VERSION 5.8 ;
BUSBITCHARS "[]" ;
DIVIDERCHAR "/" ;
UNITS
    DATABASE MICRONS 1000 ;
END UNITS

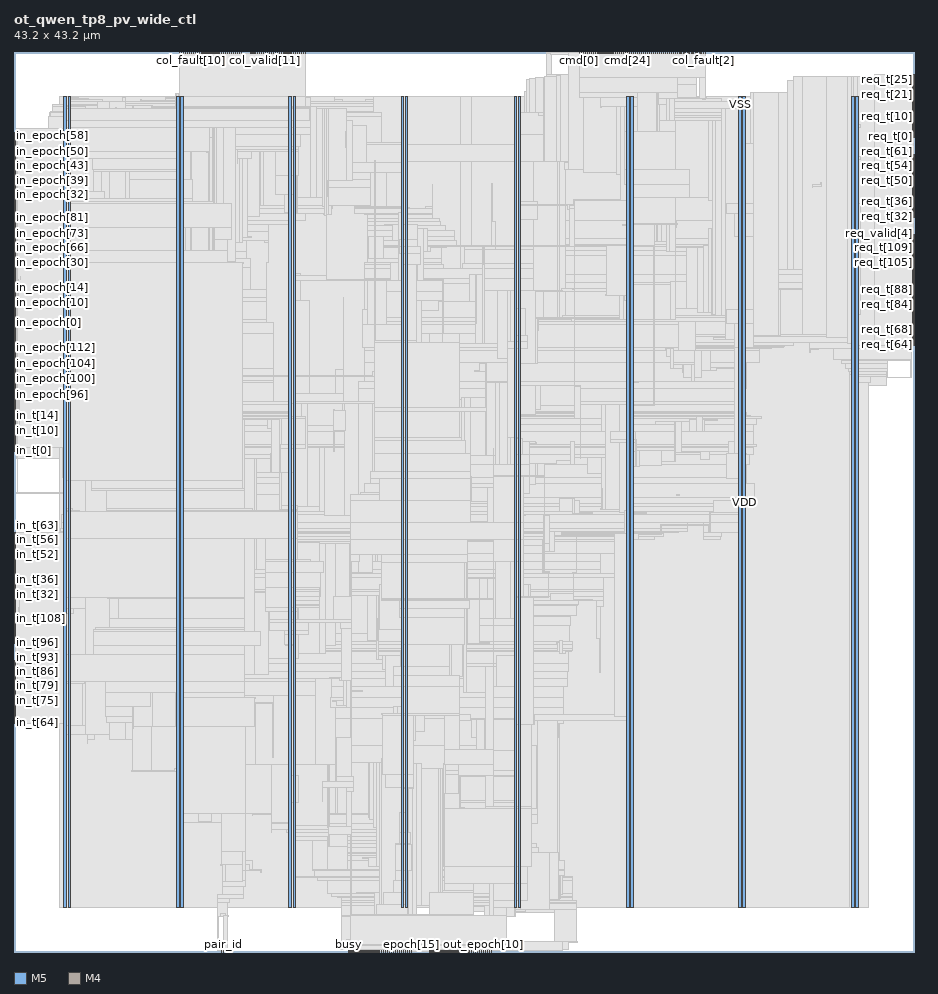
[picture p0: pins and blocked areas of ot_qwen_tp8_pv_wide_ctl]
MACRO ot_qwen_tp8_pv_wide_ctl
  FOREIGN ot_qwen_tp8_pv_wide_ctl 0 0 ;
  CLASS BLOCK ;
  SIZE 43.2 BY 43.2 ;
  PIN busy
    DIRECTION OUTPUT ;
    USE SIGNAL ;
    PORT
      LAYER M5 ;
        RECT  16.08 0 16.104 0.084 ;
    END
  END busy
  PIN clk
    DIRECTION INPUT ;
    USE SIGNAL ;
    PORT
      LAYER M5 ;
        RECT  16.176 0 16.2 0.084 ;
    END
  END clk
  PIN cmd[0]
    DIRECTION OUTPUT ;
    USE SIGNAL ;
    PORT
      LAYER M5 ;
        RECT  27.12 43.116 27.144 43.2 ;
    END
  END cmd[0]
  PIN cmd[10]
    DIRECTION OUTPUT ;
    USE SIGNAL ;
    PORT
      LAYER M5 ;
        RECT  28.08 43.116 28.104 43.2 ;
    END
  END cmd[10]
  PIN cmd[11]
    DIRECTION OUTPUT ;
    USE SIGNAL ;
    PORT
      LAYER M5 ;
        RECT  28.176 43.116 28.2 43.2 ;
    END
  END cmd[11]
  PIN cmd[12]
    DIRECTION OUTPUT ;
    USE SIGNAL ;
    PORT
      LAYER M5 ;
        RECT  28.272 43.116 28.296 43.2 ;
    END
  END cmd[12]
  PIN cmd[13]
    DIRECTION OUTPUT ;
    USE SIGNAL ;
    PORT
      LAYER M5 ;
        RECT  28.368 43.116 28.392 43.2 ;
    END
  END cmd[13]
  PIN cmd[14]
    DIRECTION OUTPUT ;
    USE SIGNAL ;
    PORT
      LAYER M5 ;
        RECT  28.464 43.116 28.488 43.2 ;
    END
  END cmd[14]
  PIN cmd[15]
    DIRECTION OUTPUT ;
    USE SIGNAL ;
    PORT
      LAYER M5 ;
        RECT  28.56 43.116 28.584 43.2 ;
    END
  END cmd[15]
  PIN cmd[16]
    DIRECTION OUTPUT ;
    USE SIGNAL ;
    PORT
      LAYER M5 ;
        RECT  28.656 43.116 28.68 43.2 ;
    END
  END cmd[16]
  PIN cmd[17]
    DIRECTION OUTPUT ;
    USE SIGNAL ;
    PORT
      LAYER M5 ;
        RECT  28.752 43.116 28.776 43.2 ;
    END
  END cmd[17]
  PIN cmd[18]
    DIRECTION OUTPUT ;
    USE SIGNAL ;
    PORT
      LAYER M5 ;
        RECT  28.848 43.116 28.872 43.2 ;
    END
  END cmd[18]
  PIN cmd[19]
    DIRECTION OUTPUT ;
    USE SIGNAL ;
    PORT
      LAYER M5 ;
        RECT  28.944 43.116 28.968 43.2 ;
    END
  END cmd[19]
  PIN cmd[1]
    DIRECTION OUTPUT ;
    USE SIGNAL ;
    PORT
      LAYER M5 ;
        RECT  27.216 43.116 27.24 43.2 ;
    END
  END cmd[1]
  PIN cmd[20]
    DIRECTION OUTPUT ;
    USE SIGNAL ;
    PORT
      LAYER M5 ;
        RECT  29.04 43.116 29.064 43.2 ;
    END
  END cmd[20]
  PIN cmd[21]
    DIRECTION OUTPUT ;
    USE SIGNAL ;
    PORT
      LAYER M5 ;
        RECT  29.136 43.116 29.16 43.2 ;
    END
  END cmd[21]
  PIN cmd[22]
    DIRECTION OUTPUT ;
    USE SIGNAL ;
    PORT
      LAYER M5 ;
        RECT  29.232 43.116 29.256 43.2 ;
    END
  END cmd[22]
  PIN cmd[23]
    DIRECTION OUTPUT ;
    USE SIGNAL ;
    PORT
      LAYER M5 ;
        RECT  29.328 43.116 29.352 43.2 ;
    END
  END cmd[23]
  PIN cmd[24]
    DIRECTION OUTPUT ;
    USE SIGNAL ;
    PORT
      LAYER M5 ;
        RECT  29.424 43.116 29.448 43.2 ;
    END
  END cmd[24]
  PIN cmd[25]
    DIRECTION OUTPUT ;
    USE SIGNAL ;
    PORT
      LAYER M5 ;
        RECT  29.52 43.116 29.544 43.2 ;
    END
  END cmd[25]
  PIN cmd[26]
    DIRECTION OUTPUT ;
    USE SIGNAL ;
    PORT
      LAYER M5 ;
        RECT  29.616 43.116 29.64 43.2 ;
    END
  END cmd[26]
  PIN cmd[27]
    DIRECTION OUTPUT ;
    USE SIGNAL ;
    PORT
      LAYER M5 ;
        RECT  29.712 43.116 29.736 43.2 ;
    END
  END cmd[27]
  PIN cmd[28]
    DIRECTION OUTPUT ;
    USE SIGNAL ;
    PORT
      LAYER M5 ;
        RECT  29.808 43.116 29.832 43.2 ;
    END
  END cmd[28]
  PIN cmd[29]
    DIRECTION OUTPUT ;
    USE SIGNAL ;
    PORT
      LAYER M5 ;
        RECT  29.904 43.116 29.928 43.2 ;
    END
  END cmd[29]
  PIN cmd[2]
    DIRECTION OUTPUT ;
    USE SIGNAL ;
    PORT
      LAYER M5 ;
        RECT  27.312 43.116 27.336 43.2 ;
    END
  END cmd[2]
  PIN cmd[30]
    DIRECTION OUTPUT ;
    USE SIGNAL ;
    PORT
      LAYER M5 ;
        RECT  30 43.116 30.024 43.2 ;
    END
  END cmd[30]
  PIN cmd[31]
    DIRECTION OUTPUT ;
    USE SIGNAL ;
    PORT
      LAYER M5 ;
        RECT  30.096 43.116 30.12 43.2 ;
    END
  END cmd[31]
  PIN cmd[32]
    DIRECTION OUTPUT ;
    USE SIGNAL ;
    PORT
      LAYER M5 ;
        RECT  30.192 43.116 30.216 43.2 ;
    END
  END cmd[32]
  PIN cmd[33]
    DIRECTION OUTPUT ;
    USE SIGNAL ;
    PORT
      LAYER M5 ;
        RECT  30.288 43.116 30.312 43.2 ;
    END
  END cmd[33]
  PIN cmd[34]
    DIRECTION OUTPUT ;
    USE SIGNAL ;
    PORT
      LAYER M5 ;
        RECT  30.384 43.116 30.408 43.2 ;
    END
  END cmd[34]
  PIN cmd[35]
    DIRECTION OUTPUT ;
    USE SIGNAL ;
    PORT
      LAYER M5 ;
        RECT  30.48 43.116 30.504 43.2 ;
    END
  END cmd[35]
  PIN cmd[36]
    DIRECTION OUTPUT ;
    USE SIGNAL ;
    PORT
      LAYER M5 ;
        RECT  30.576 43.116 30.6 43.2 ;
    END
  END cmd[36]
  PIN cmd[37]
    DIRECTION OUTPUT ;
    USE SIGNAL ;
    PORT
      LAYER M5 ;
        RECT  30.672 43.116 30.696 43.2 ;
    END
  END cmd[37]
  PIN cmd[38]
    DIRECTION OUTPUT ;
    USE SIGNAL ;
    PORT
      LAYER M5 ;
        RECT  30.768 43.116 30.792 43.2 ;
    END
  END cmd[38]
  PIN cmd[39]
    DIRECTION OUTPUT ;
    USE SIGNAL ;
    PORT
      LAYER M5 ;
        RECT  30.864 43.116 30.888 43.2 ;
    END
  END cmd[39]
  PIN cmd[3]
    DIRECTION OUTPUT ;
    USE SIGNAL ;
    PORT
      LAYER M5 ;
        RECT  27.408 43.116 27.432 43.2 ;
    END
  END cmd[3]
  PIN cmd[40]
    DIRECTION OUTPUT ;
    USE SIGNAL ;
    PORT
      LAYER M5 ;
        RECT  30.96 43.116 30.984 43.2 ;
    END
  END cmd[40]
  PIN cmd[41]
    DIRECTION OUTPUT ;
    USE SIGNAL ;
    PORT
      LAYER M5 ;
        RECT  31.056 43.116 31.08 43.2 ;
    END
  END cmd[41]
  PIN cmd[42]
    DIRECTION OUTPUT ;
    USE SIGNAL ;
    PORT
      LAYER M5 ;
        RECT  31.152 43.116 31.176 43.2 ;
    END
  END cmd[42]
  PIN cmd[43]
    DIRECTION OUTPUT ;
    USE SIGNAL ;
    PORT
      LAYER M5 ;
        RECT  31.248 43.116 31.272 43.2 ;
    END
  END cmd[43]
  PIN cmd[44]
    DIRECTION OUTPUT ;
    USE SIGNAL ;
    PORT
      LAYER M5 ;
        RECT  31.344 43.116 31.368 43.2 ;
    END
  END cmd[44]
  PIN cmd[45]
    DIRECTION OUTPUT ;
    USE SIGNAL ;
    PORT
      LAYER M5 ;
        RECT  31.44 43.116 31.464 43.2 ;
    END
  END cmd[45]
  PIN cmd[46]
    DIRECTION OUTPUT ;
    USE SIGNAL ;
    PORT
      LAYER M5 ;
        RECT  31.536 43.116 31.56 43.2 ;
    END
  END cmd[46]
  PIN cmd[47]
    DIRECTION OUTPUT ;
    USE SIGNAL ;
    PORT
      LAYER M5 ;
        RECT  31.632 43.116 31.656 43.2 ;
    END
  END cmd[47]
  PIN cmd[48]
    DIRECTION OUTPUT ;
    USE SIGNAL ;
    PORT
      LAYER M5 ;
        RECT  31.728 43.116 31.752 43.2 ;
    END
  END cmd[48]
  PIN cmd[49]
    DIRECTION OUTPUT ;
    USE SIGNAL ;
    PORT
      LAYER M5 ;
        RECT  31.824 43.116 31.848 43.2 ;
    END
  END cmd[49]
  PIN cmd[4]
    DIRECTION OUTPUT ;
    USE SIGNAL ;
    PORT
      LAYER M5 ;
        RECT  27.504 43.116 27.528 43.2 ;
    END
  END cmd[4]
  PIN cmd[50]
    DIRECTION OUTPUT ;
    USE SIGNAL ;
    PORT
      LAYER M5 ;
        RECT  31.92 43.116 31.944 43.2 ;
    END
  END cmd[50]
  PIN cmd[51]
    DIRECTION OUTPUT ;
    USE SIGNAL ;
    PORT
      LAYER M5 ;
        RECT  32.016 43.116 32.04 43.2 ;
    END
  END cmd[51]
  PIN cmd[52]
    DIRECTION OUTPUT ;
    USE SIGNAL ;
    PORT
      LAYER M5 ;
        RECT  32.112 43.116 32.136 43.2 ;
    END
  END cmd[52]
  PIN cmd[53]
    DIRECTION OUTPUT ;
    USE SIGNAL ;
    PORT
      LAYER M5 ;
        RECT  32.208 43.116 32.232 43.2 ;
    END
  END cmd[53]
  PIN cmd[54]
    DIRECTION OUTPUT ;
    USE SIGNAL ;
    PORT
      LAYER M5 ;
        RECT  32.304 43.116 32.328 43.2 ;
    END
  END cmd[54]
  PIN cmd[55]
    DIRECTION OUTPUT ;
    USE SIGNAL ;
    PORT
      LAYER M5 ;
        RECT  32.4 43.116 32.424 43.2 ;
    END
  END cmd[55]
  PIN cmd[56]
    DIRECTION OUTPUT ;
    USE SIGNAL ;
    PORT
      LAYER M5 ;
        RECT  32.496 43.116 32.52 43.2 ;
    END
  END cmd[56]
  PIN cmd[57]
    DIRECTION OUTPUT ;
    USE SIGNAL ;
    PORT
      LAYER M5 ;
        RECT  32.592 43.116 32.616 43.2 ;
    END
  END cmd[57]
  PIN cmd[58]
    DIRECTION OUTPUT ;
    USE SIGNAL ;
    PORT
      LAYER M5 ;
        RECT  32.688 43.116 32.712 43.2 ;
    END
  END cmd[58]
  PIN cmd[59]
    DIRECTION OUTPUT ;
    USE SIGNAL ;
    PORT
      LAYER M5 ;
        RECT  32.784 43.116 32.808 43.2 ;
    END
  END cmd[59]
  PIN cmd[5]
    DIRECTION OUTPUT ;
    USE SIGNAL ;
    PORT
      LAYER M5 ;
        RECT  27.6 43.116 27.624 43.2 ;
    END
  END cmd[5]
  PIN cmd[6]
    DIRECTION OUTPUT ;
    USE SIGNAL ;
    PORT
      LAYER M5 ;
        RECT  27.696 43.116 27.72 43.2 ;
    END
  END cmd[6]
  PIN cmd[7]
    DIRECTION OUTPUT ;
    USE SIGNAL ;
    PORT
      LAYER M5 ;
        RECT  27.792 43.116 27.816 43.2 ;
    END
  END cmd[7]
  PIN cmd[8]
    DIRECTION OUTPUT ;
    USE SIGNAL ;
    PORT
      LAYER M5 ;
        RECT  27.888 43.116 27.912 43.2 ;
    END
  END cmd[8]
  PIN cmd[9]
    DIRECTION OUTPUT ;
    USE SIGNAL ;
    PORT
      LAYER M5 ;
        RECT  27.984 43.116 28.008 43.2 ;
    END
  END cmd[9]
  PIN col_fault[0]
    DIRECTION INPUT ;
    USE SIGNAL ;
    PORT
      LAYER M5 ;
        RECT  32.88 43.116 32.904 43.2 ;
    END
  END col_fault[0]
  PIN col_fault[10]
    DIRECTION INPUT ;
    USE SIGNAL ;
    PORT
      LAYER M5 ;
        RECT  8.496 43.116 8.52 43.2 ;
    END
  END col_fault[10]
  PIN col_fault[11]
    DIRECTION INPUT ;
    USE SIGNAL ;
    PORT
      LAYER M5 ;
        RECT  8.592 43.116 8.616 43.2 ;
    END
  END col_fault[11]
  PIN col_fault[12]
    DIRECTION INPUT ;
    USE SIGNAL ;
    PORT
      LAYER M5 ;
        RECT  8.688 43.116 8.712 43.2 ;
    END
  END col_fault[12]
  PIN col_fault[13]
    DIRECTION INPUT ;
    USE SIGNAL ;
    PORT
      LAYER M5 ;
        RECT  8.784 43.116 8.808 43.2 ;
    END
  END col_fault[13]
  PIN col_fault[14]
    DIRECTION INPUT ;
    USE SIGNAL ;
    PORT
      LAYER M5 ;
        RECT  8.88 43.116 8.904 43.2 ;
    END
  END col_fault[14]
  PIN col_fault[15]
    DIRECTION INPUT ;
    USE SIGNAL ;
    PORT
      LAYER M5 ;
        RECT  8.976 43.116 9 43.2 ;
    END
  END col_fault[15]
  PIN col_fault[16]
    DIRECTION INPUT ;
    USE SIGNAL ;
    PORT
      LAYER M5 ;
        RECT  9.072 43.116 9.096 43.2 ;
    END
  END col_fault[16]
  PIN col_fault[17]
    DIRECTION INPUT ;
    USE SIGNAL ;
    PORT
      LAYER M5 ;
        RECT  9.168 43.116 9.192 43.2 ;
    END
  END col_fault[17]
  PIN col_fault[18]
    DIRECTION INPUT ;
    USE SIGNAL ;
    PORT
      LAYER M5 ;
        RECT  9.264 43.116 9.288 43.2 ;
    END
  END col_fault[18]
  PIN col_fault[19]
    DIRECTION INPUT ;
    USE SIGNAL ;
    PORT
      LAYER M5 ;
        RECT  9.36 43.116 9.384 43.2 ;
    END
  END col_fault[19]
  PIN col_fault[1]
    DIRECTION INPUT ;
    USE SIGNAL ;
    PORT
      LAYER M5 ;
        RECT  32.976 43.116 33 43.2 ;
    END
  END col_fault[1]
  PIN col_fault[20]
    DIRECTION INPUT ;
    USE SIGNAL ;
    PORT
      LAYER M5 ;
        RECT  9.456 43.116 9.48 43.2 ;
    END
  END col_fault[20]
  PIN col_fault[21]
    DIRECTION INPUT ;
    USE SIGNAL ;
    PORT
      LAYER M5 ;
        RECT  9.552 43.116 9.576 43.2 ;
    END
  END col_fault[21]
  PIN col_fault[22]
    DIRECTION INPUT ;
    USE SIGNAL ;
    PORT
      LAYER M5 ;
        RECT  9.648 43.116 9.672 43.2 ;
    END
  END col_fault[22]
  PIN col_fault[23]
    DIRECTION INPUT ;
    USE SIGNAL ;
    PORT
      LAYER M5 ;
        RECT  9.744 43.116 9.768 43.2 ;
    END
  END col_fault[23]
  PIN col_fault[24]
    DIRECTION INPUT ;
    USE SIGNAL ;
    PORT
      LAYER M5 ;
        RECT  9.84 43.116 9.864 43.2 ;
    END
  END col_fault[24]
  PIN col_fault[25]
    DIRECTION INPUT ;
    USE SIGNAL ;
    PORT
      LAYER M5 ;
        RECT  9.936 43.116 9.96 43.2 ;
    END
  END col_fault[25]
  PIN col_fault[26]
    DIRECTION INPUT ;
    USE SIGNAL ;
    PORT
      LAYER M5 ;
        RECT  10.032 43.116 10.056 43.2 ;
    END
  END col_fault[26]
  PIN col_fault[27]
    DIRECTION INPUT ;
    USE SIGNAL ;
    PORT
      LAYER M5 ;
        RECT  10.128 43.116 10.152 43.2 ;
    END
  END col_fault[27]
  PIN col_fault[28]
    DIRECTION INPUT ;
    USE SIGNAL ;
    PORT
      LAYER M5 ;
        RECT  10.224 43.116 10.248 43.2 ;
    END
  END col_fault[28]
  PIN col_fault[29]
    DIRECTION INPUT ;
    USE SIGNAL ;
    PORT
      LAYER M5 ;
        RECT  10.32 43.116 10.344 43.2 ;
    END
  END col_fault[29]
  PIN col_fault[2]
    DIRECTION INPUT ;
    USE SIGNAL ;
    PORT
      LAYER M5 ;
        RECT  33.072 43.116 33.096 43.2 ;
    END
  END col_fault[2]
  PIN col_fault[30]
    DIRECTION INPUT ;
    USE SIGNAL ;
    PORT
      LAYER M5 ;
        RECT  10.416 43.116 10.44 43.2 ;
    END
  END col_fault[30]
  PIN col_fault[31]
    DIRECTION INPUT ;
    USE SIGNAL ;
    PORT
      LAYER M5 ;
        RECT  10.512 43.116 10.536 43.2 ;
    END
  END col_fault[31]
  PIN col_fault[3]
    DIRECTION INPUT ;
    USE SIGNAL ;
    PORT
      LAYER M5 ;
        RECT  33.168 43.116 33.192 43.2 ;
    END
  END col_fault[3]
  PIN col_fault[4]
    DIRECTION INPUT ;
    USE SIGNAL ;
    PORT
      LAYER M5 ;
        RECT  7.92 43.116 7.944 43.2 ;
    END
  END col_fault[4]
  PIN col_fault[5]
    DIRECTION INPUT ;
    USE SIGNAL ;
    PORT
      LAYER M5 ;
        RECT  8.016 43.116 8.04 43.2 ;
    END
  END col_fault[5]
  PIN col_fault[6]
    DIRECTION INPUT ;
    USE SIGNAL ;
    PORT
      LAYER M5 ;
        RECT  8.112 43.116 8.136 43.2 ;
    END
  END col_fault[6]
  PIN col_fault[7]
    DIRECTION INPUT ;
    USE SIGNAL ;
    PORT
      LAYER M5 ;
        RECT  8.208 43.116 8.232 43.2 ;
    END
  END col_fault[7]
  PIN col_fault[8]
    DIRECTION INPUT ;
    USE SIGNAL ;
    PORT
      LAYER M5 ;
        RECT  8.304 43.116 8.328 43.2 ;
    END
  END col_fault[8]
  PIN col_fault[9]
    DIRECTION INPUT ;
    USE SIGNAL ;
    PORT
      LAYER M5 ;
        RECT  8.4 43.116 8.424 43.2 ;
    END
  END col_fault[9]
  PIN col_valid[0]
    DIRECTION INPUT ;
    USE SIGNAL ;
    PORT
      LAYER M5 ;
        RECT  10.608 43.116 10.632 43.2 ;
    END
  END col_valid[0]
  PIN col_valid[10]
    DIRECTION INPUT ;
    USE SIGNAL ;
    PORT
      LAYER M5 ;
        RECT  11.952 43.116 11.976 43.2 ;
    END
  END col_valid[10]
  PIN col_valid[11]
    DIRECTION INPUT ;
    USE SIGNAL ;
    PORT
      LAYER M5 ;
        RECT  12.048 43.116 12.072 43.2 ;
    END
  END col_valid[11]
  PIN col_valid[12]
    DIRECTION INPUT ;
    USE SIGNAL ;
    PORT
      LAYER M5 ;
        RECT  12.144 43.116 12.168 43.2 ;
    END
  END col_valid[12]
  PIN col_valid[13]
    DIRECTION INPUT ;
    USE SIGNAL ;
    PORT
      LAYER M5 ;
        RECT  12.24 43.116 12.264 43.2 ;
    END
  END col_valid[13]
  PIN col_valid[14]
    DIRECTION INPUT ;
    USE SIGNAL ;
    PORT
      LAYER M5 ;
        RECT  12.336 43.116 12.36 43.2 ;
    END
  END col_valid[14]
  PIN col_valid[15]
    DIRECTION INPUT ;
    USE SIGNAL ;
    PORT
      LAYER M5 ;
        RECT  12.432 43.116 12.456 43.2 ;
    END
  END col_valid[15]
  PIN col_valid[16]
    DIRECTION INPUT ;
    USE SIGNAL ;
    PORT
      LAYER M5 ;
        RECT  12.528 43.116 12.552 43.2 ;
    END
  END col_valid[16]
  PIN col_valid[17]
    DIRECTION INPUT ;
    USE SIGNAL ;
    PORT
      LAYER M5 ;
        RECT  12.624 43.116 12.648 43.2 ;
    END
  END col_valid[17]
  PIN col_valid[18]
    DIRECTION INPUT ;
    USE SIGNAL ;
    PORT
      LAYER M5 ;
        RECT  12.72 43.116 12.744 43.2 ;
    END
  END col_valid[18]
  PIN col_valid[19]
    DIRECTION INPUT ;
    USE SIGNAL ;
    PORT
      LAYER M5 ;
        RECT  12.816 43.116 12.84 43.2 ;
    END
  END col_valid[19]
  PIN col_valid[1]
    DIRECTION INPUT ;
    USE SIGNAL ;
    PORT
      LAYER M5 ;
        RECT  10.704 43.116 10.728 43.2 ;
    END
  END col_valid[1]
  PIN col_valid[20]
    DIRECTION INPUT ;
    USE SIGNAL ;
    PORT
      LAYER M5 ;
        RECT  12.912 43.116 12.936 43.2 ;
    END
  END col_valid[20]
  PIN col_valid[21]
    DIRECTION INPUT ;
    USE SIGNAL ;
    PORT
      LAYER M5 ;
        RECT  13.008 43.116 13.032 43.2 ;
    END
  END col_valid[21]
  PIN col_valid[22]
    DIRECTION INPUT ;
    USE SIGNAL ;
    PORT
      LAYER M5 ;
        RECT  13.104 43.116 13.128 43.2 ;
    END
  END col_valid[22]
  PIN col_valid[23]
    DIRECTION INPUT ;
    USE SIGNAL ;
    PORT
      LAYER M5 ;
        RECT  13.2 43.116 13.224 43.2 ;
    END
  END col_valid[23]
  PIN col_valid[24]
    DIRECTION INPUT ;
    USE SIGNAL ;
    PORT
      LAYER M5 ;
        RECT  13.296 43.116 13.32 43.2 ;
    END
  END col_valid[24]
  PIN col_valid[25]
    DIRECTION INPUT ;
    USE SIGNAL ;
    PORT
      LAYER M5 ;
        RECT  13.392 43.116 13.416 43.2 ;
    END
  END col_valid[25]
  PIN col_valid[26]
    DIRECTION INPUT ;
    USE SIGNAL ;
    PORT
      LAYER M5 ;
        RECT  13.488 43.116 13.512 43.2 ;
    END
  END col_valid[26]
  PIN col_valid[27]
    DIRECTION INPUT ;
    USE SIGNAL ;
    PORT
      LAYER M5 ;
        RECT  13.584 43.116 13.608 43.2 ;
    END
  END col_valid[27]
  PIN col_valid[28]
    DIRECTION INPUT ;
    USE SIGNAL ;
    PORT
      LAYER M5 ;
        RECT  13.68 43.116 13.704 43.2 ;
    END
  END col_valid[28]
  PIN col_valid[29]
    DIRECTION INPUT ;
    USE SIGNAL ;
    PORT
      LAYER M5 ;
        RECT  13.776 43.116 13.8 43.2 ;
    END
  END col_valid[29]
  PIN col_valid[2]
    DIRECTION INPUT ;
    USE SIGNAL ;
    PORT
      LAYER M5 ;
        RECT  10.8 43.116 10.824 43.2 ;
    END
  END col_valid[2]
  PIN col_valid[30]
    DIRECTION INPUT ;
    USE SIGNAL ;
    PORT
      LAYER M5 ;
        RECT  13.872 43.116 13.896 43.2 ;
    END
  END col_valid[30]
  PIN col_valid[31]
    DIRECTION INPUT ;
    USE SIGNAL ;
    PORT
      LAYER M5 ;
        RECT  13.968 43.116 13.992 43.2 ;
    END
  END col_valid[31]
  PIN col_valid[3]
    DIRECTION INPUT ;
    USE SIGNAL ;
    PORT
      LAYER M5 ;
        RECT  10.896 43.116 10.92 43.2 ;
    END
  END col_valid[3]
  PIN col_valid[4]
    DIRECTION INPUT ;
    USE SIGNAL ;
    PORT
      LAYER M5 ;
        RECT  11.376 43.116 11.4 43.2 ;
    END
  END col_valid[4]
  PIN col_valid[5]
    DIRECTION INPUT ;
    USE SIGNAL ;
    PORT
      LAYER M5 ;
        RECT  11.472 43.116 11.496 43.2 ;
    END
  END col_valid[5]
  PIN col_valid[6]
    DIRECTION INPUT ;
    USE SIGNAL ;
    PORT
      LAYER M5 ;
        RECT  11.568 43.116 11.592 43.2 ;
    END
  END col_valid[6]
  PIN col_valid[7]
    DIRECTION INPUT ;
    USE SIGNAL ;
    PORT
      LAYER M5 ;
        RECT  11.664 43.116 11.688 43.2 ;
    END
  END col_valid[7]
  PIN col_valid[8]
    DIRECTION INPUT ;
    USE SIGNAL ;
    PORT
      LAYER M5 ;
        RECT  11.76 43.116 11.784 43.2 ;
    END
  END col_valid[8]
  PIN col_valid[9]
    DIRECTION INPUT ;
    USE SIGNAL ;
    PORT
      LAYER M5 ;
        RECT  11.856 43.116 11.88 43.2 ;
    END
  END col_valid[9]
  PIN context_len[0]
    DIRECTION INPUT ;
    USE SIGNAL ;
    PORT
      LAYER M5 ;
        RECT  16.272 0 16.296 0.084 ;
    END
  END context_len[0]
  PIN context_len[10]
    DIRECTION INPUT ;
    USE SIGNAL ;
    PORT
      LAYER M5 ;
        RECT  17.232 0 17.256 0.084 ;
    END
  END context_len[10]
  PIN context_len[11]
    DIRECTION INPUT ;
    USE SIGNAL ;
    PORT
      LAYER M5 ;
        RECT  17.328 0 17.352 0.084 ;
    END
  END context_len[11]
  PIN context_len[12]
    DIRECTION INPUT ;
    USE SIGNAL ;
    PORT
      LAYER M5 ;
        RECT  17.424 0 17.448 0.084 ;
    END
  END context_len[12]
  PIN context_len[13]
    DIRECTION INPUT ;
    USE SIGNAL ;
    PORT
      LAYER M5 ;
        RECT  17.52 0 17.544 0.084 ;
    END
  END context_len[13]
  PIN context_len[1]
    DIRECTION INPUT ;
    USE SIGNAL ;
    PORT
      LAYER M5 ;
        RECT  16.368 0 16.392 0.084 ;
    END
  END context_len[1]
  PIN context_len[2]
    DIRECTION INPUT ;
    USE SIGNAL ;
    PORT
      LAYER M5 ;
        RECT  16.464 0 16.488 0.084 ;
    END
  END context_len[2]
  PIN context_len[3]
    DIRECTION INPUT ;
    USE SIGNAL ;
    PORT
      LAYER M5 ;
        RECT  16.56 0 16.584 0.084 ;
    END
  END context_len[3]
  PIN context_len[4]
    DIRECTION INPUT ;
    USE SIGNAL ;
    PORT
      LAYER M5 ;
        RECT  16.656 0 16.68 0.084 ;
    END
  END context_len[4]
  PIN context_len[5]
    DIRECTION INPUT ;
    USE SIGNAL ;
    PORT
      LAYER M5 ;
        RECT  16.752 0 16.776 0.084 ;
    END
  END context_len[5]
  PIN context_len[6]
    DIRECTION INPUT ;
    USE SIGNAL ;
    PORT
      LAYER M5 ;
        RECT  16.848 0 16.872 0.084 ;
    END
  END context_len[6]
  PIN context_len[7]
    DIRECTION INPUT ;
    USE SIGNAL ;
    PORT
      LAYER M5 ;
        RECT  16.944 0 16.968 0.084 ;
    END
  END context_len[7]
  PIN context_len[8]
    DIRECTION INPUT ;
    USE SIGNAL ;
    PORT
      LAYER M5 ;
        RECT  17.04 0 17.064 0.084 ;
    END
  END context_len[8]
  PIN context_len[9]
    DIRECTION INPUT ;
    USE SIGNAL ;
    PORT
      LAYER M5 ;
        RECT  17.136 0 17.16 0.084 ;
    END
  END context_len[9]
  PIN epoch[0]
    DIRECTION INPUT ;
    USE SIGNAL ;
    PORT
      LAYER M5 ;
        RECT  17.616 0 17.64 0.084 ;
    END
  END epoch[0]
  PIN epoch[10]
    DIRECTION INPUT ;
    USE SIGNAL ;
    PORT
      LAYER M5 ;
        RECT  18.576 0 18.6 0.084 ;
    END
  END epoch[10]
  PIN epoch[11]
    DIRECTION INPUT ;
    USE SIGNAL ;
    PORT
      LAYER M5 ;
        RECT  18.672 0 18.696 0.084 ;
    END
  END epoch[11]
  PIN epoch[12]
    DIRECTION INPUT ;
    USE SIGNAL ;
    PORT
      LAYER M5 ;
        RECT  18.768 0 18.792 0.084 ;
    END
  END epoch[12]
  PIN epoch[13]
    DIRECTION INPUT ;
    USE SIGNAL ;
    PORT
      LAYER M5 ;
        RECT  18.864 0 18.888 0.084 ;
    END
  END epoch[13]
  PIN epoch[14]
    DIRECTION INPUT ;
    USE SIGNAL ;
    PORT
      LAYER M5 ;
        RECT  18.96 0 18.984 0.084 ;
    END
  END epoch[14]
  PIN epoch[15]
    DIRECTION INPUT ;
    USE SIGNAL ;
    PORT
      LAYER M5 ;
        RECT  19.056 0 19.08 0.084 ;
    END
  END epoch[15]
  PIN epoch[1]
    DIRECTION INPUT ;
    USE SIGNAL ;
    PORT
      LAYER M5 ;
        RECT  17.712 0 17.736 0.084 ;
    END
  END epoch[1]
  PIN epoch[2]
    DIRECTION INPUT ;
    USE SIGNAL ;
    PORT
      LAYER M5 ;
        RECT  17.808 0 17.832 0.084 ;
    END
  END epoch[2]
  PIN epoch[3]
    DIRECTION INPUT ;
    USE SIGNAL ;
    PORT
      LAYER M5 ;
        RECT  17.904 0 17.928 0.084 ;
    END
  END epoch[3]
  PIN epoch[4]
    DIRECTION INPUT ;
    USE SIGNAL ;
    PORT
      LAYER M5 ;
        RECT  18 0 18.024 0.084 ;
    END
  END epoch[4]
  PIN epoch[5]
    DIRECTION INPUT ;
    USE SIGNAL ;
    PORT
      LAYER M5 ;
        RECT  18.096 0 18.12 0.084 ;
    END
  END epoch[5]
  PIN epoch[6]
    DIRECTION INPUT ;
    USE SIGNAL ;
    PORT
      LAYER M5 ;
        RECT  18.192 0 18.216 0.084 ;
    END
  END epoch[6]
  PIN epoch[7]
    DIRECTION INPUT ;
    USE SIGNAL ;
    PORT
      LAYER M5 ;
        RECT  18.288 0 18.312 0.084 ;
    END
  END epoch[7]
  PIN epoch[8]
    DIRECTION INPUT ;
    USE SIGNAL ;
    PORT
      LAYER M5 ;
        RECT  18.384 0 18.408 0.084 ;
    END
  END epoch[8]
  PIN epoch[9]
    DIRECTION INPUT ;
    USE SIGNAL ;
    PORT
      LAYER M5 ;
        RECT  18.48 0 18.504 0.084 ;
    END
  END epoch[9]
  PIN fault
    DIRECTION OUTPUT ;
    USE SIGNAL ;
    PORT
      LAYER M5 ;
        RECT  19.92 0 19.944 0.084 ;
    END
  END fault
  PIN in_epoch[0]
    DIRECTION INPUT ;
    USE SIGNAL ;
    PORT
      LAYER M4 ;
        RECT  0 30.192 0.084 30.216 ;
    END
  END in_epoch[0]
  PIN in_epoch[100]
    DIRECTION INPUT ;
    USE SIGNAL ;
    PORT
      LAYER M4 ;
        RECT  0 27.504 0.084 27.528 ;
    END
  END in_epoch[100]
  PIN in_epoch[101]
    DIRECTION INPUT ;
    USE SIGNAL ;
    PORT
      LAYER M4 ;
        RECT  0 27.6 0.084 27.624 ;
    END
  END in_epoch[101]
  PIN in_epoch[102]
    DIRECTION INPUT ;
    USE SIGNAL ;
    PORT
      LAYER M4 ;
        RECT  0 27.696 0.084 27.72 ;
    END
  END in_epoch[102]
  PIN in_epoch[103]
    DIRECTION INPUT ;
    USE SIGNAL ;
    PORT
      LAYER M4 ;
        RECT  0 27.792 0.084 27.816 ;
    END
  END in_epoch[103]
  PIN in_epoch[104]
    DIRECTION INPUT ;
    USE SIGNAL ;
    PORT
      LAYER M4 ;
        RECT  0 27.888 0.084 27.912 ;
    END
  END in_epoch[104]
  PIN in_epoch[105]
    DIRECTION INPUT ;
    USE SIGNAL ;
    PORT
      LAYER M4 ;
        RECT  0 27.984 0.084 28.008 ;
    END
  END in_epoch[105]
  PIN in_epoch[106]
    DIRECTION INPUT ;
    USE SIGNAL ;
    PORT
      LAYER M4 ;
        RECT  0 28.08 0.084 28.104 ;
    END
  END in_epoch[106]
  PIN in_epoch[107]
    DIRECTION INPUT ;
    USE SIGNAL ;
    PORT
      LAYER M4 ;
        RECT  0 28.176 0.084 28.2 ;
    END
  END in_epoch[107]
  PIN in_epoch[108]
    DIRECTION INPUT ;
    USE SIGNAL ;
    PORT
      LAYER M4 ;
        RECT  0 28.272 0.084 28.296 ;
    END
  END in_epoch[108]
  PIN in_epoch[109]
    DIRECTION INPUT ;
    USE SIGNAL ;
    PORT
      LAYER M4 ;
        RECT  0 28.368 0.084 28.392 ;
    END
  END in_epoch[109]
  PIN in_epoch[10]
    DIRECTION INPUT ;
    USE SIGNAL ;
    PORT
      LAYER M4 ;
        RECT  0 31.152 0.084 31.176 ;
    END
  END in_epoch[10]
  PIN in_epoch[110]
    DIRECTION INPUT ;
    USE SIGNAL ;
    PORT
      LAYER M4 ;
        RECT  0 28.464 0.084 28.488 ;
    END
  END in_epoch[110]
  PIN in_epoch[111]
    DIRECTION INPUT ;
    USE SIGNAL ;
    PORT
      LAYER M4 ;
        RECT  0 28.56 0.084 28.584 ;
    END
  END in_epoch[111]
  PIN in_epoch[112]
    DIRECTION INPUT ;
    USE SIGNAL ;
    PORT
      LAYER M4 ;
        RECT  0 28.656 0.084 28.68 ;
    END
  END in_epoch[112]
  PIN in_epoch[113]
    DIRECTION INPUT ;
    USE SIGNAL ;
    PORT
      LAYER M4 ;
        RECT  0 28.752 0.084 28.776 ;
    END
  END in_epoch[113]
  PIN in_epoch[114]
    DIRECTION INPUT ;
    USE SIGNAL ;
    PORT
      LAYER M4 ;
        RECT  0 28.848 0.084 28.872 ;
    END
  END in_epoch[114]
  PIN in_epoch[115]
    DIRECTION INPUT ;
    USE SIGNAL ;
    PORT
      LAYER M4 ;
        RECT  0 28.944 0.084 28.968 ;
    END
  END in_epoch[115]
  PIN in_epoch[116]
    DIRECTION INPUT ;
    USE SIGNAL ;
    PORT
      LAYER M4 ;
        RECT  0 29.04 0.084 29.064 ;
    END
  END in_epoch[116]
  PIN in_epoch[117]
    DIRECTION INPUT ;
    USE SIGNAL ;
    PORT
      LAYER M4 ;
        RECT  0 29.136 0.084 29.16 ;
    END
  END in_epoch[117]
  PIN in_epoch[118]
    DIRECTION INPUT ;
    USE SIGNAL ;
    PORT
      LAYER M4 ;
        RECT  0 29.232 0.084 29.256 ;
    END
  END in_epoch[118]
  PIN in_epoch[119]
    DIRECTION INPUT ;
    USE SIGNAL ;
    PORT
      LAYER M4 ;
        RECT  0 29.328 0.084 29.352 ;
    END
  END in_epoch[119]
  PIN in_epoch[11]
    DIRECTION INPUT ;
    USE SIGNAL ;
    PORT
      LAYER M4 ;
        RECT  0 31.248 0.084 31.272 ;
    END
  END in_epoch[11]
  PIN in_epoch[120]
    DIRECTION INPUT ;
    USE SIGNAL ;
    PORT
      LAYER M4 ;
        RECT  0 29.424 0.084 29.448 ;
    END
  END in_epoch[120]
  PIN in_epoch[121]
    DIRECTION INPUT ;
    USE SIGNAL ;
    PORT
      LAYER M4 ;
        RECT  0 29.52 0.084 29.544 ;
    END
  END in_epoch[121]
  PIN in_epoch[122]
    DIRECTION INPUT ;
    USE SIGNAL ;
    PORT
      LAYER M4 ;
        RECT  0 29.616 0.084 29.64 ;
    END
  END in_epoch[122]
  PIN in_epoch[123]
    DIRECTION INPUT ;
    USE SIGNAL ;
    PORT
      LAYER M4 ;
        RECT  0 29.712 0.084 29.736 ;
    END
  END in_epoch[123]
  PIN in_epoch[124]
    DIRECTION INPUT ;
    USE SIGNAL ;
    PORT
      LAYER M4 ;
        RECT  0 29.808 0.084 29.832 ;
    END
  END in_epoch[124]
  PIN in_epoch[125]
    DIRECTION INPUT ;
    USE SIGNAL ;
    PORT
      LAYER M4 ;
        RECT  0 29.904 0.084 29.928 ;
    END
  END in_epoch[125]
  PIN in_epoch[126]
    DIRECTION INPUT ;
    USE SIGNAL ;
    PORT
      LAYER M4 ;
        RECT  0 30 0.084 30.024 ;
    END
  END in_epoch[126]
  PIN in_epoch[127]
    DIRECTION INPUT ;
    USE SIGNAL ;
    PORT
      LAYER M4 ;
        RECT  0 30.096 0.084 30.12 ;
    END
  END in_epoch[127]
  PIN in_epoch[12]
    DIRECTION INPUT ;
    USE SIGNAL ;
    PORT
      LAYER M4 ;
        RECT  0 31.344 0.084 31.368 ;
    END
  END in_epoch[12]
  PIN in_epoch[13]
    DIRECTION INPUT ;
    USE SIGNAL ;
    PORT
      LAYER M4 ;
        RECT  0 31.44 0.084 31.464 ;
    END
  END in_epoch[13]
  PIN in_epoch[14]
    DIRECTION INPUT ;
    USE SIGNAL ;
    PORT
      LAYER M4 ;
        RECT  0 31.536 0.084 31.56 ;
    END
  END in_epoch[14]
  PIN in_epoch[15]
    DIRECTION INPUT ;
    USE SIGNAL ;
    PORT
      LAYER M4 ;
        RECT  0 31.632 0.084 31.656 ;
    END
  END in_epoch[15]
  PIN in_epoch[16]
    DIRECTION INPUT ;
    USE SIGNAL ;
    PORT
      LAYER M4 ;
        RECT  0 31.728 0.084 31.752 ;
    END
  END in_epoch[16]
  PIN in_epoch[17]
    DIRECTION INPUT ;
    USE SIGNAL ;
    PORT
      LAYER M4 ;
        RECT  0 31.824 0.084 31.848 ;
    END
  END in_epoch[17]
  PIN in_epoch[18]
    DIRECTION INPUT ;
    USE SIGNAL ;
    PORT
      LAYER M4 ;
        RECT  0 31.92 0.084 31.944 ;
    END
  END in_epoch[18]
  PIN in_epoch[19]
    DIRECTION INPUT ;
    USE SIGNAL ;
    PORT
      LAYER M4 ;
        RECT  0 32.016 0.084 32.04 ;
    END
  END in_epoch[19]
  PIN in_epoch[1]
    DIRECTION INPUT ;
    USE SIGNAL ;
    PORT
      LAYER M4 ;
        RECT  0 30.288 0.084 30.312 ;
    END
  END in_epoch[1]
  PIN in_epoch[20]
    DIRECTION INPUT ;
    USE SIGNAL ;
    PORT
      LAYER M4 ;
        RECT  0 32.112 0.084 32.136 ;
    END
  END in_epoch[20]
  PIN in_epoch[21]
    DIRECTION INPUT ;
    USE SIGNAL ;
    PORT
      LAYER M4 ;
        RECT  0 32.208 0.084 32.232 ;
    END
  END in_epoch[21]
  PIN in_epoch[22]
    DIRECTION INPUT ;
    USE SIGNAL ;
    PORT
      LAYER M4 ;
        RECT  0 32.304 0.084 32.328 ;
    END
  END in_epoch[22]
  PIN in_epoch[23]
    DIRECTION INPUT ;
    USE SIGNAL ;
    PORT
      LAYER M4 ;
        RECT  0 32.4 0.084 32.424 ;
    END
  END in_epoch[23]
  PIN in_epoch[24]
    DIRECTION INPUT ;
    USE SIGNAL ;
    PORT
      LAYER M4 ;
        RECT  0 32.496 0.084 32.52 ;
    END
  END in_epoch[24]
  PIN in_epoch[25]
    DIRECTION INPUT ;
    USE SIGNAL ;
    PORT
      LAYER M4 ;
        RECT  0 32.592 0.084 32.616 ;
    END
  END in_epoch[25]
  PIN in_epoch[26]
    DIRECTION INPUT ;
    USE SIGNAL ;
    PORT
      LAYER M4 ;
        RECT  0 32.688 0.084 32.712 ;
    END
  END in_epoch[26]
  PIN in_epoch[27]
    DIRECTION INPUT ;
    USE SIGNAL ;
    PORT
      LAYER M4 ;
        RECT  0 32.784 0.084 32.808 ;
    END
  END in_epoch[27]
  PIN in_epoch[28]
    DIRECTION INPUT ;
    USE SIGNAL ;
    PORT
      LAYER M4 ;
        RECT  0 32.88 0.084 32.904 ;
    END
  END in_epoch[28]
  PIN in_epoch[29]
    DIRECTION INPUT ;
    USE SIGNAL ;
    PORT
      LAYER M4 ;
        RECT  0 32.976 0.084 33 ;
    END
  END in_epoch[29]
  PIN in_epoch[2]
    DIRECTION INPUT ;
    USE SIGNAL ;
    PORT
      LAYER M4 ;
        RECT  0 30.384 0.084 30.408 ;
    END
  END in_epoch[2]
  PIN in_epoch[30]
    DIRECTION INPUT ;
    USE SIGNAL ;
    PORT
      LAYER M4 ;
        RECT  0 33.072 0.084 33.096 ;
    END
  END in_epoch[30]
  PIN in_epoch[31]
    DIRECTION INPUT ;
    USE SIGNAL ;
    PORT
      LAYER M4 ;
        RECT  0 33.168 0.084 33.192 ;
    END
  END in_epoch[31]
  PIN in_epoch[32]
    DIRECTION INPUT ;
    USE SIGNAL ;
    PORT
      LAYER M4 ;
        RECT  0 36.336 0.084 36.36 ;
    END
  END in_epoch[32]
  PIN in_epoch[33]
    DIRECTION INPUT ;
    USE SIGNAL ;
    PORT
      LAYER M4 ;
        RECT  0 36.432 0.084 36.456 ;
    END
  END in_epoch[33]
  PIN in_epoch[34]
    DIRECTION INPUT ;
    USE SIGNAL ;
    PORT
      LAYER M4 ;
        RECT  0 36.528 0.084 36.552 ;
    END
  END in_epoch[34]
  PIN in_epoch[35]
    DIRECTION INPUT ;
    USE SIGNAL ;
    PORT
      LAYER M4 ;
        RECT  0 36.624 0.084 36.648 ;
    END
  END in_epoch[35]
  PIN in_epoch[36]
    DIRECTION INPUT ;
    USE SIGNAL ;
    PORT
      LAYER M4 ;
        RECT  0 36.72 0.084 36.744 ;
    END
  END in_epoch[36]
  PIN in_epoch[37]
    DIRECTION INPUT ;
    USE SIGNAL ;
    PORT
      LAYER M4 ;
        RECT  0 36.816 0.084 36.84 ;
    END
  END in_epoch[37]
  PIN in_epoch[38]
    DIRECTION INPUT ;
    USE SIGNAL ;
    PORT
      LAYER M4 ;
        RECT  0 36.912 0.084 36.936 ;
    END
  END in_epoch[38]
  PIN in_epoch[39]
    DIRECTION INPUT ;
    USE SIGNAL ;
    PORT
      LAYER M4 ;
        RECT  0 37.008 0.084 37.032 ;
    END
  END in_epoch[39]
  PIN in_epoch[3]
    DIRECTION INPUT ;
    USE SIGNAL ;
    PORT
      LAYER M4 ;
        RECT  0 30.48 0.084 30.504 ;
    END
  END in_epoch[3]
  PIN in_epoch[40]
    DIRECTION INPUT ;
    USE SIGNAL ;
    PORT
      LAYER M4 ;
        RECT  0 37.104 0.084 37.128 ;
    END
  END in_epoch[40]
  PIN in_epoch[41]
    DIRECTION INPUT ;
    USE SIGNAL ;
    PORT
      LAYER M4 ;
        RECT  0 37.2 0.084 37.224 ;
    END
  END in_epoch[41]
  PIN in_epoch[42]
    DIRECTION INPUT ;
    USE SIGNAL ;
    PORT
      LAYER M4 ;
        RECT  0 37.296 0.084 37.32 ;
    END
  END in_epoch[42]
  PIN in_epoch[43]
    DIRECTION INPUT ;
    USE SIGNAL ;
    PORT
      LAYER M4 ;
        RECT  0 37.392 0.084 37.416 ;
    END
  END in_epoch[43]
  PIN in_epoch[44]
    DIRECTION INPUT ;
    USE SIGNAL ;
    PORT
      LAYER M4 ;
        RECT  0 37.488 0.084 37.512 ;
    END
  END in_epoch[44]
  PIN in_epoch[45]
    DIRECTION INPUT ;
    USE SIGNAL ;
    PORT
      LAYER M4 ;
        RECT  0 37.584 0.084 37.608 ;
    END
  END in_epoch[45]
  PIN in_epoch[46]
    DIRECTION INPUT ;
    USE SIGNAL ;
    PORT
      LAYER M4 ;
        RECT  0 37.68 0.084 37.704 ;
    END
  END in_epoch[46]
  PIN in_epoch[47]
    DIRECTION INPUT ;
    USE SIGNAL ;
    PORT
      LAYER M4 ;
        RECT  0 37.776 0.084 37.8 ;
    END
  END in_epoch[47]
  PIN in_epoch[48]
    DIRECTION INPUT ;
    USE SIGNAL ;
    PORT
      LAYER M4 ;
        RECT  0 37.872 0.084 37.896 ;
    END
  END in_epoch[48]
  PIN in_epoch[49]
    DIRECTION INPUT ;
    USE SIGNAL ;
    PORT
      LAYER M4 ;
        RECT  0 37.968 0.084 37.992 ;
    END
  END in_epoch[49]
  PIN in_epoch[4]
    DIRECTION INPUT ;
    USE SIGNAL ;
    PORT
      LAYER M4 ;
        RECT  0 30.576 0.084 30.6 ;
    END
  END in_epoch[4]
  PIN in_epoch[50]
    DIRECTION INPUT ;
    USE SIGNAL ;
    PORT
      LAYER M4 ;
        RECT  0 38.064 0.084 38.088 ;
    END
  END in_epoch[50]
  PIN in_epoch[51]
    DIRECTION INPUT ;
    USE SIGNAL ;
    PORT
      LAYER M4 ;
        RECT  0 38.16 0.084 38.184 ;
    END
  END in_epoch[51]
  PIN in_epoch[52]
    DIRECTION INPUT ;
    USE SIGNAL ;
    PORT
      LAYER M4 ;
        RECT  0 38.256 0.084 38.28 ;
    END
  END in_epoch[52]
  PIN in_epoch[53]
    DIRECTION INPUT ;
    USE SIGNAL ;
    PORT
      LAYER M4 ;
        RECT  0 38.352 0.084 38.376 ;
    END
  END in_epoch[53]
  PIN in_epoch[54]
    DIRECTION INPUT ;
    USE SIGNAL ;
    PORT
      LAYER M4 ;
        RECT  0 38.448 0.084 38.472 ;
    END
  END in_epoch[54]
  PIN in_epoch[55]
    DIRECTION INPUT ;
    USE SIGNAL ;
    PORT
      LAYER M4 ;
        RECT  0 38.544 0.084 38.568 ;
    END
  END in_epoch[55]
  PIN in_epoch[56]
    DIRECTION INPUT ;
    USE SIGNAL ;
    PORT
      LAYER M4 ;
        RECT  0 38.64 0.084 38.664 ;
    END
  END in_epoch[56]
  PIN in_epoch[57]
    DIRECTION INPUT ;
    USE SIGNAL ;
    PORT
      LAYER M4 ;
        RECT  0 38.736 0.084 38.76 ;
    END
  END in_epoch[57]
  PIN in_epoch[58]
    DIRECTION INPUT ;
    USE SIGNAL ;
    PORT
      LAYER M4 ;
        RECT  0 38.832 0.084 38.856 ;
    END
  END in_epoch[58]
  PIN in_epoch[59]
    DIRECTION INPUT ;
    USE SIGNAL ;
    PORT
      LAYER M4 ;
        RECT  0 38.928 0.084 38.952 ;
    END
  END in_epoch[59]
  PIN in_epoch[5]
    DIRECTION INPUT ;
    USE SIGNAL ;
    PORT
      LAYER M4 ;
        RECT  0 30.672 0.084 30.696 ;
    END
  END in_epoch[5]
  PIN in_epoch[60]
    DIRECTION INPUT ;
    USE SIGNAL ;
    PORT
      LAYER M4 ;
        RECT  0 39.024 0.084 39.048 ;
    END
  END in_epoch[60]
  PIN in_epoch[61]
    DIRECTION INPUT ;
    USE SIGNAL ;
    PORT
      LAYER M4 ;
        RECT  0 39.12 0.084 39.144 ;
    END
  END in_epoch[61]
  PIN in_epoch[62]
    DIRECTION INPUT ;
    USE SIGNAL ;
    PORT
      LAYER M4 ;
        RECT  0 39.216 0.084 39.24 ;
    END
  END in_epoch[62]
  PIN in_epoch[63]
    DIRECTION INPUT ;
    USE SIGNAL ;
    PORT
      LAYER M4 ;
        RECT  0 39.312 0.084 39.336 ;
    END
  END in_epoch[63]
  PIN in_epoch[64]
    DIRECTION INPUT ;
    USE SIGNAL ;
    PORT
      LAYER M4 ;
        RECT  0 33.264 0.084 33.288 ;
    END
  END in_epoch[64]
  PIN in_epoch[65]
    DIRECTION INPUT ;
    USE SIGNAL ;
    PORT
      LAYER M4 ;
        RECT  0 33.36 0.084 33.384 ;
    END
  END in_epoch[65]
  PIN in_epoch[66]
    DIRECTION INPUT ;
    USE SIGNAL ;
    PORT
      LAYER M4 ;
        RECT  0 33.456 0.084 33.48 ;
    END
  END in_epoch[66]
  PIN in_epoch[67]
    DIRECTION INPUT ;
    USE SIGNAL ;
    PORT
      LAYER M4 ;
        RECT  0 33.552 0.084 33.576 ;
    END
  END in_epoch[67]
  PIN in_epoch[68]
    DIRECTION INPUT ;
    USE SIGNAL ;
    PORT
      LAYER M4 ;
        RECT  0 33.648 0.084 33.672 ;
    END
  END in_epoch[68]
  PIN in_epoch[69]
    DIRECTION INPUT ;
    USE SIGNAL ;
    PORT
      LAYER M4 ;
        RECT  0 33.744 0.084 33.768 ;
    END
  END in_epoch[69]
  PIN in_epoch[6]
    DIRECTION INPUT ;
    USE SIGNAL ;
    PORT
      LAYER M4 ;
        RECT  0 30.768 0.084 30.792 ;
    END
  END in_epoch[6]
  PIN in_epoch[70]
    DIRECTION INPUT ;
    USE SIGNAL ;
    PORT
      LAYER M4 ;
        RECT  0 33.84 0.084 33.864 ;
    END
  END in_epoch[70]
  PIN in_epoch[71]
    DIRECTION INPUT ;
    USE SIGNAL ;
    PORT
      LAYER M4 ;
        RECT  0 33.936 0.084 33.96 ;
    END
  END in_epoch[71]
  PIN in_epoch[72]
    DIRECTION INPUT ;
    USE SIGNAL ;
    PORT
      LAYER M4 ;
        RECT  0 34.032 0.084 34.056 ;
    END
  END in_epoch[72]
  PIN in_epoch[73]
    DIRECTION INPUT ;
    USE SIGNAL ;
    PORT
      LAYER M4 ;
        RECT  0 34.128 0.084 34.152 ;
    END
  END in_epoch[73]
  PIN in_epoch[74]
    DIRECTION INPUT ;
    USE SIGNAL ;
    PORT
      LAYER M4 ;
        RECT  0 34.224 0.084 34.248 ;
    END
  END in_epoch[74]
  PIN in_epoch[75]
    DIRECTION INPUT ;
    USE SIGNAL ;
    PORT
      LAYER M4 ;
        RECT  0 34.32 0.084 34.344 ;
    END
  END in_epoch[75]
  PIN in_epoch[76]
    DIRECTION INPUT ;
    USE SIGNAL ;
    PORT
      LAYER M4 ;
        RECT  0 34.416 0.084 34.44 ;
    END
  END in_epoch[76]
  PIN in_epoch[77]
    DIRECTION INPUT ;
    USE SIGNAL ;
    PORT
      LAYER M4 ;
        RECT  0 34.512 0.084 34.536 ;
    END
  END in_epoch[77]
  PIN in_epoch[78]
    DIRECTION INPUT ;
    USE SIGNAL ;
    PORT
      LAYER M4 ;
        RECT  0 34.608 0.084 34.632 ;
    END
  END in_epoch[78]
  PIN in_epoch[79]
    DIRECTION INPUT ;
    USE SIGNAL ;
    PORT
      LAYER M4 ;
        RECT  0 34.704 0.084 34.728 ;
    END
  END in_epoch[79]
  PIN in_epoch[7]
    DIRECTION INPUT ;
    USE SIGNAL ;
    PORT
      LAYER M4 ;
        RECT  0 30.864 0.084 30.888 ;
    END
  END in_epoch[7]
  PIN in_epoch[80]
    DIRECTION INPUT ;
    USE SIGNAL ;
    PORT
      LAYER M4 ;
        RECT  0 34.8 0.084 34.824 ;
    END
  END in_epoch[80]
  PIN in_epoch[81]
    DIRECTION INPUT ;
    USE SIGNAL ;
    PORT
      LAYER M4 ;
        RECT  0 34.896 0.084 34.92 ;
    END
  END in_epoch[81]
  PIN in_epoch[82]
    DIRECTION INPUT ;
    USE SIGNAL ;
    PORT
      LAYER M4 ;
        RECT  0 34.992 0.084 35.016 ;
    END
  END in_epoch[82]
  PIN in_epoch[83]
    DIRECTION INPUT ;
    USE SIGNAL ;
    PORT
      LAYER M4 ;
        RECT  0 35.088 0.084 35.112 ;
    END
  END in_epoch[83]
  PIN in_epoch[84]
    DIRECTION INPUT ;
    USE SIGNAL ;
    PORT
      LAYER M4 ;
        RECT  0 35.184 0.084 35.208 ;
    END
  END in_epoch[84]
  PIN in_epoch[85]
    DIRECTION INPUT ;
    USE SIGNAL ;
    PORT
      LAYER M4 ;
        RECT  0 35.28 0.084 35.304 ;
    END
  END in_epoch[85]
  PIN in_epoch[86]
    DIRECTION INPUT ;
    USE SIGNAL ;
    PORT
      LAYER M4 ;
        RECT  0 35.376 0.084 35.4 ;
    END
  END in_epoch[86]
  PIN in_epoch[87]
    DIRECTION INPUT ;
    USE SIGNAL ;
    PORT
      LAYER M4 ;
        RECT  0 35.472 0.084 35.496 ;
    END
  END in_epoch[87]
  PIN in_epoch[88]
    DIRECTION INPUT ;
    USE SIGNAL ;
    PORT
      LAYER M4 ;
        RECT  0 35.568 0.084 35.592 ;
    END
  END in_epoch[88]
  PIN in_epoch[89]
    DIRECTION INPUT ;
    USE SIGNAL ;
    PORT
      LAYER M4 ;
        RECT  0 35.664 0.084 35.688 ;
    END
  END in_epoch[89]
  PIN in_epoch[8]
    DIRECTION INPUT ;
    USE SIGNAL ;
    PORT
      LAYER M4 ;
        RECT  0 30.96 0.084 30.984 ;
    END
  END in_epoch[8]
  PIN in_epoch[90]
    DIRECTION INPUT ;
    USE SIGNAL ;
    PORT
      LAYER M4 ;
        RECT  0 35.76 0.084 35.784 ;
    END
  END in_epoch[90]
  PIN in_epoch[91]
    DIRECTION INPUT ;
    USE SIGNAL ;
    PORT
      LAYER M4 ;
        RECT  0 35.856 0.084 35.88 ;
    END
  END in_epoch[91]
  PIN in_epoch[92]
    DIRECTION INPUT ;
    USE SIGNAL ;
    PORT
      LAYER M4 ;
        RECT  0 35.952 0.084 35.976 ;
    END
  END in_epoch[92]
  PIN in_epoch[93]
    DIRECTION INPUT ;
    USE SIGNAL ;
    PORT
      LAYER M4 ;
        RECT  0 36.048 0.084 36.072 ;
    END
  END in_epoch[93]
  PIN in_epoch[94]
    DIRECTION INPUT ;
    USE SIGNAL ;
    PORT
      LAYER M4 ;
        RECT  0 36.144 0.084 36.168 ;
    END
  END in_epoch[94]
  PIN in_epoch[95]
    DIRECTION INPUT ;
    USE SIGNAL ;
    PORT
      LAYER M4 ;
        RECT  0 36.24 0.084 36.264 ;
    END
  END in_epoch[95]
  PIN in_epoch[96]
    DIRECTION INPUT ;
    USE SIGNAL ;
    PORT
      LAYER M4 ;
        RECT  0 27.12 0.084 27.144 ;
    END
  END in_epoch[96]
  PIN in_epoch[97]
    DIRECTION INPUT ;
    USE SIGNAL ;
    PORT
      LAYER M4 ;
        RECT  0 27.216 0.084 27.24 ;
    END
  END in_epoch[97]
  PIN in_epoch[98]
    DIRECTION INPUT ;
    USE SIGNAL ;
    PORT
      LAYER M4 ;
        RECT  0 27.312 0.084 27.336 ;
    END
  END in_epoch[98]
  PIN in_epoch[99]
    DIRECTION INPUT ;
    USE SIGNAL ;
    PORT
      LAYER M4 ;
        RECT  0 27.408 0.084 27.432 ;
    END
  END in_epoch[99]
  PIN in_epoch[9]
    DIRECTION INPUT ;
    USE SIGNAL ;
    PORT
      LAYER M4 ;
        RECT  0 31.056 0.084 31.08 ;
    END
  END in_epoch[9]
  PIN in_t[0]
    DIRECTION INPUT ;
    USE SIGNAL ;
    PORT
      LAYER M4 ;
        RECT  0 24.048 0.084 24.072 ;
    END
  END in_t[0]
  PIN in_t[100]
    DIRECTION INPUT ;
    USE SIGNAL ;
    PORT
      LAYER M4 ;
        RECT  0 15.216 0.084 15.24 ;
    END
  END in_t[100]
  PIN in_t[101]
    DIRECTION INPUT ;
    USE SIGNAL ;
    PORT
      LAYER M4 ;
        RECT  0 15.312 0.084 15.336 ;
    END
  END in_t[101]
  PIN in_t[102]
    DIRECTION INPUT ;
    USE SIGNAL ;
    PORT
      LAYER M4 ;
        RECT  0 15.408 0.084 15.432 ;
    END
  END in_t[102]
  PIN in_t[103]
    DIRECTION INPUT ;
    USE SIGNAL ;
    PORT
      LAYER M4 ;
        RECT  0 15.504 0.084 15.528 ;
    END
  END in_t[103]
  PIN in_t[104]
    DIRECTION INPUT ;
    USE SIGNAL ;
    PORT
      LAYER M4 ;
        RECT  0 15.6 0.084 15.624 ;
    END
  END in_t[104]
  PIN in_t[105]
    DIRECTION INPUT ;
    USE SIGNAL ;
    PORT
      LAYER M4 ;
        RECT  0 15.696 0.084 15.72 ;
    END
  END in_t[105]
  PIN in_t[106]
    DIRECTION INPUT ;
    USE SIGNAL ;
    PORT
      LAYER M4 ;
        RECT  0 15.792 0.084 15.816 ;
    END
  END in_t[106]
  PIN in_t[107]
    DIRECTION INPUT ;
    USE SIGNAL ;
    PORT
      LAYER M4 ;
        RECT  0 15.888 0.084 15.912 ;
    END
  END in_t[107]
  PIN in_t[108]
    DIRECTION INPUT ;
    USE SIGNAL ;
    PORT
      LAYER M4 ;
        RECT  0 15.984 0.084 16.008 ;
    END
  END in_t[108]
  PIN in_t[109]
    DIRECTION INPUT ;
    USE SIGNAL ;
    PORT
      LAYER M4 ;
        RECT  0 16.08 0.084 16.104 ;
    END
  END in_t[109]
  PIN in_t[10]
    DIRECTION INPUT ;
    USE SIGNAL ;
    PORT
      LAYER M4 ;
        RECT  0 25.008 0.084 25.032 ;
    END
  END in_t[10]
  PIN in_t[110]
    DIRECTION INPUT ;
    USE SIGNAL ;
    PORT
      LAYER M4 ;
        RECT  0 16.176 0.084 16.2 ;
    END
  END in_t[110]
  PIN in_t[111]
    DIRECTION INPUT ;
    USE SIGNAL ;
    PORT
      LAYER M4 ;
        RECT  0 16.272 0.084 16.296 ;
    END
  END in_t[111]
  PIN in_t[11]
    DIRECTION INPUT ;
    USE SIGNAL ;
    PORT
      LAYER M4 ;
        RECT  0 25.104 0.084 25.128 ;
    END
  END in_t[11]
  PIN in_t[12]
    DIRECTION INPUT ;
    USE SIGNAL ;
    PORT
      LAYER M4 ;
        RECT  0 25.2 0.084 25.224 ;
    END
  END in_t[12]
  PIN in_t[13]
    DIRECTION INPUT ;
    USE SIGNAL ;
    PORT
      LAYER M4 ;
        RECT  0 25.296 0.084 25.32 ;
    END
  END in_t[13]
  PIN in_t[14]
    DIRECTION INPUT ;
    USE SIGNAL ;
    PORT
      LAYER M4 ;
        RECT  0 25.392 0.084 25.416 ;
    END
  END in_t[14]
  PIN in_t[15]
    DIRECTION INPUT ;
    USE SIGNAL ;
    PORT
      LAYER M4 ;
        RECT  0 25.488 0.084 25.512 ;
    END
  END in_t[15]
  PIN in_t[16]
    DIRECTION INPUT ;
    USE SIGNAL ;
    PORT
      LAYER M4 ;
        RECT  0 25.584 0.084 25.608 ;
    END
  END in_t[16]
  PIN in_t[17]
    DIRECTION INPUT ;
    USE SIGNAL ;
    PORT
      LAYER M4 ;
        RECT  0 25.68 0.084 25.704 ;
    END
  END in_t[17]
  PIN in_t[18]
    DIRECTION INPUT ;
    USE SIGNAL ;
    PORT
      LAYER M4 ;
        RECT  0 25.776 0.084 25.8 ;
    END
  END in_t[18]
  PIN in_t[19]
    DIRECTION INPUT ;
    USE SIGNAL ;
    PORT
      LAYER M4 ;
        RECT  0 25.872 0.084 25.896 ;
    END
  END in_t[19]
  PIN in_t[1]
    DIRECTION INPUT ;
    USE SIGNAL ;
    PORT
      LAYER M4 ;
        RECT  0 24.144 0.084 24.168 ;
    END
  END in_t[1]
  PIN in_t[20]
    DIRECTION INPUT ;
    USE SIGNAL ;
    PORT
      LAYER M4 ;
        RECT  0 25.968 0.084 25.992 ;
    END
  END in_t[20]
  PIN in_t[21]
    DIRECTION INPUT ;
    USE SIGNAL ;
    PORT
      LAYER M4 ;
        RECT  0 26.064 0.084 26.088 ;
    END
  END in_t[21]
  PIN in_t[22]
    DIRECTION INPUT ;
    USE SIGNAL ;
    PORT
      LAYER M4 ;
        RECT  0 26.16 0.084 26.184 ;
    END
  END in_t[22]
  PIN in_t[23]
    DIRECTION INPUT ;
    USE SIGNAL ;
    PORT
      LAYER M4 ;
        RECT  0 26.256 0.084 26.28 ;
    END
  END in_t[23]
  PIN in_t[24]
    DIRECTION INPUT ;
    USE SIGNAL ;
    PORT
      LAYER M4 ;
        RECT  0 26.352 0.084 26.376 ;
    END
  END in_t[24]
  PIN in_t[25]
    DIRECTION INPUT ;
    USE SIGNAL ;
    PORT
      LAYER M4 ;
        RECT  0 26.448 0.084 26.472 ;
    END
  END in_t[25]
  PIN in_t[26]
    DIRECTION INPUT ;
    USE SIGNAL ;
    PORT
      LAYER M4 ;
        RECT  0 26.544 0.084 26.568 ;
    END
  END in_t[26]
  PIN in_t[27]
    DIRECTION INPUT ;
    USE SIGNAL ;
    PORT
      LAYER M4 ;
        RECT  0 26.64 0.084 26.664 ;
    END
  END in_t[27]
  PIN in_t[28]
    DIRECTION INPUT ;
    USE SIGNAL ;
    PORT
      LAYER M4 ;
        RECT  0 26.736 0.084 26.76 ;
    END
  END in_t[28]
  PIN in_t[29]
    DIRECTION INPUT ;
    USE SIGNAL ;
    PORT
      LAYER M4 ;
        RECT  0 26.832 0.084 26.856 ;
    END
  END in_t[29]
  PIN in_t[2]
    DIRECTION INPUT ;
    USE SIGNAL ;
    PORT
      LAYER M4 ;
        RECT  0 24.24 0.084 24.264 ;
    END
  END in_t[2]
  PIN in_t[30]
    DIRECTION INPUT ;
    USE SIGNAL ;
    PORT
      LAYER M4 ;
        RECT  0 26.928 0.084 26.952 ;
    END
  END in_t[30]
  PIN in_t[31]
    DIRECTION INPUT ;
    USE SIGNAL ;
    PORT
      LAYER M4 ;
        RECT  0 27.024 0.084 27.048 ;
    END
  END in_t[31]
  PIN in_t[32]
    DIRECTION INPUT ;
    USE SIGNAL ;
    PORT
      LAYER M4 ;
        RECT  0 17.136 0.084 17.16 ;
    END
  END in_t[32]
  PIN in_t[33]
    DIRECTION INPUT ;
    USE SIGNAL ;
    PORT
      LAYER M4 ;
        RECT  0 17.232 0.084 17.256 ;
    END
  END in_t[33]
  PIN in_t[34]
    DIRECTION INPUT ;
    USE SIGNAL ;
    PORT
      LAYER M4 ;
        RECT  0 17.328 0.084 17.352 ;
    END
  END in_t[34]
  PIN in_t[35]
    DIRECTION INPUT ;
    USE SIGNAL ;
    PORT
      LAYER M4 ;
        RECT  0 17.424 0.084 17.448 ;
    END
  END in_t[35]
  PIN in_t[36]
    DIRECTION INPUT ;
    USE SIGNAL ;
    PORT
      LAYER M4 ;
        RECT  0 17.52 0.084 17.544 ;
    END
  END in_t[36]
  PIN in_t[37]
    DIRECTION INPUT ;
    USE SIGNAL ;
    PORT
      LAYER M4 ;
        RECT  0 17.616 0.084 17.64 ;
    END
  END in_t[37]
  PIN in_t[38]
    DIRECTION INPUT ;
    USE SIGNAL ;
    PORT
      LAYER M4 ;
        RECT  0 17.712 0.084 17.736 ;
    END
  END in_t[38]
  PIN in_t[39]
    DIRECTION INPUT ;
    USE SIGNAL ;
    PORT
      LAYER M4 ;
        RECT  0 17.808 0.084 17.832 ;
    END
  END in_t[39]
  PIN in_t[3]
    DIRECTION INPUT ;
    USE SIGNAL ;
    PORT
      LAYER M4 ;
        RECT  0 24.336 0.084 24.36 ;
    END
  END in_t[3]
  PIN in_t[40]
    DIRECTION INPUT ;
    USE SIGNAL ;
    PORT
      LAYER M4 ;
        RECT  0 17.904 0.084 17.928 ;
    END
  END in_t[40]
  PIN in_t[41]
    DIRECTION INPUT ;
    USE SIGNAL ;
    PORT
      LAYER M4 ;
        RECT  0 18 0.084 18.024 ;
    END
  END in_t[41]
  PIN in_t[42]
    DIRECTION INPUT ;
    USE SIGNAL ;
    PORT
      LAYER M4 ;
        RECT  0 18.096 0.084 18.12 ;
    END
  END in_t[42]
  PIN in_t[43]
    DIRECTION INPUT ;
    USE SIGNAL ;
    PORT
      LAYER M4 ;
        RECT  0 18.192 0.084 18.216 ;
    END
  END in_t[43]
  PIN in_t[44]
    DIRECTION INPUT ;
    USE SIGNAL ;
    PORT
      LAYER M4 ;
        RECT  0 18.288 0.084 18.312 ;
    END
  END in_t[44]
  PIN in_t[45]
    DIRECTION INPUT ;
    USE SIGNAL ;
    PORT
      LAYER M4 ;
        RECT  0 18.384 0.084 18.408 ;
    END
  END in_t[45]
  PIN in_t[46]
    DIRECTION INPUT ;
    USE SIGNAL ;
    PORT
      LAYER M4 ;
        RECT  0 18.48 0.084 18.504 ;
    END
  END in_t[46]
  PIN in_t[47]
    DIRECTION INPUT ;
    USE SIGNAL ;
    PORT
      LAYER M4 ;
        RECT  0 18.576 0.084 18.6 ;
    END
  END in_t[47]
  PIN in_t[48]
    DIRECTION INPUT ;
    USE SIGNAL ;
    PORT
      LAYER M4 ;
        RECT  0 18.672 0.084 18.696 ;
    END
  END in_t[48]
  PIN in_t[49]
    DIRECTION INPUT ;
    USE SIGNAL ;
    PORT
      LAYER M4 ;
        RECT  0 18.768 0.084 18.792 ;
    END
  END in_t[49]
  PIN in_t[4]
    DIRECTION INPUT ;
    USE SIGNAL ;
    PORT
      LAYER M4 ;
        RECT  0 24.432 0.084 24.456 ;
    END
  END in_t[4]
  PIN in_t[50]
    DIRECTION INPUT ;
    USE SIGNAL ;
    PORT
      LAYER M4 ;
        RECT  0 18.864 0.084 18.888 ;
    END
  END in_t[50]
  PIN in_t[51]
    DIRECTION INPUT ;
    USE SIGNAL ;
    PORT
      LAYER M4 ;
        RECT  0 18.96 0.084 18.984 ;
    END
  END in_t[51]
  PIN in_t[52]
    DIRECTION INPUT ;
    USE SIGNAL ;
    PORT
      LAYER M4 ;
        RECT  0 19.056 0.084 19.08 ;
    END
  END in_t[52]
  PIN in_t[53]
    DIRECTION INPUT ;
    USE SIGNAL ;
    PORT
      LAYER M4 ;
        RECT  0 19.152 0.084 19.176 ;
    END
  END in_t[53]
  PIN in_t[54]
    DIRECTION INPUT ;
    USE SIGNAL ;
    PORT
      LAYER M4 ;
        RECT  0 19.248 0.084 19.272 ;
    END
  END in_t[54]
  PIN in_t[55]
    DIRECTION INPUT ;
    USE SIGNAL ;
    PORT
      LAYER M4 ;
        RECT  0 19.344 0.084 19.368 ;
    END
  END in_t[55]
  PIN in_t[56]
    DIRECTION INPUT ;
    USE SIGNAL ;
    PORT
      LAYER M4 ;
        RECT  0 19.44 0.084 19.464 ;
    END
  END in_t[56]
  PIN in_t[57]
    DIRECTION INPUT ;
    USE SIGNAL ;
    PORT
      LAYER M4 ;
        RECT  0 19.536 0.084 19.56 ;
    END
  END in_t[57]
  PIN in_t[58]
    DIRECTION INPUT ;
    USE SIGNAL ;
    PORT
      LAYER M4 ;
        RECT  0 19.632 0.084 19.656 ;
    END
  END in_t[58]
  PIN in_t[59]
    DIRECTION INPUT ;
    USE SIGNAL ;
    PORT
      LAYER M4 ;
        RECT  0 19.728 0.084 19.752 ;
    END
  END in_t[59]
  PIN in_t[5]
    DIRECTION INPUT ;
    USE SIGNAL ;
    PORT
      LAYER M4 ;
        RECT  0 24.528 0.084 24.552 ;
    END
  END in_t[5]
  PIN in_t[60]
    DIRECTION INPUT ;
    USE SIGNAL ;
    PORT
      LAYER M4 ;
        RECT  0 19.824 0.084 19.848 ;
    END
  END in_t[60]
  PIN in_t[61]
    DIRECTION INPUT ;
    USE SIGNAL ;
    PORT
      LAYER M4 ;
        RECT  0 19.92 0.084 19.944 ;
    END
  END in_t[61]
  PIN in_t[62]
    DIRECTION INPUT ;
    USE SIGNAL ;
    PORT
      LAYER M4 ;
        RECT  0 20.016 0.084 20.04 ;
    END
  END in_t[62]
  PIN in_t[63]
    DIRECTION INPUT ;
    USE SIGNAL ;
    PORT
      LAYER M4 ;
        RECT  0 20.112 0.084 20.136 ;
    END
  END in_t[63]
  PIN in_t[64]
    DIRECTION INPUT ;
    USE SIGNAL ;
    PORT
      LAYER M4 ;
        RECT  0 10.992 0.084 11.016 ;
    END
  END in_t[64]
  PIN in_t[65]
    DIRECTION INPUT ;
    USE SIGNAL ;
    PORT
      LAYER M4 ;
        RECT  0 11.088 0.084 11.112 ;
    END
  END in_t[65]
  PIN in_t[66]
    DIRECTION INPUT ;
    USE SIGNAL ;
    PORT
      LAYER M4 ;
        RECT  0 11.184 0.084 11.208 ;
    END
  END in_t[66]
  PIN in_t[67]
    DIRECTION INPUT ;
    USE SIGNAL ;
    PORT
      LAYER M4 ;
        RECT  0 11.28 0.084 11.304 ;
    END
  END in_t[67]
  PIN in_t[68]
    DIRECTION INPUT ;
    USE SIGNAL ;
    PORT
      LAYER M4 ;
        RECT  0 11.376 0.084 11.4 ;
    END
  END in_t[68]
  PIN in_t[69]
    DIRECTION INPUT ;
    USE SIGNAL ;
    PORT
      LAYER M4 ;
        RECT  0 11.472 0.084 11.496 ;
    END
  END in_t[69]
  PIN in_t[6]
    DIRECTION INPUT ;
    USE SIGNAL ;
    PORT
      LAYER M4 ;
        RECT  0 24.624 0.084 24.648 ;
    END
  END in_t[6]
  PIN in_t[70]
    DIRECTION INPUT ;
    USE SIGNAL ;
    PORT
      LAYER M4 ;
        RECT  0 11.568 0.084 11.592 ;
    END
  END in_t[70]
  PIN in_t[71]
    DIRECTION INPUT ;
    USE SIGNAL ;
    PORT
      LAYER M4 ;
        RECT  0 11.664 0.084 11.688 ;
    END
  END in_t[71]
  PIN in_t[72]
    DIRECTION INPUT ;
    USE SIGNAL ;
    PORT
      LAYER M4 ;
        RECT  0 11.76 0.084 11.784 ;
    END
  END in_t[72]
  PIN in_t[73]
    DIRECTION INPUT ;
    USE SIGNAL ;
    PORT
      LAYER M4 ;
        RECT  0 11.856 0.084 11.88 ;
    END
  END in_t[73]
  PIN in_t[74]
    DIRECTION INPUT ;
    USE SIGNAL ;
    PORT
      LAYER M4 ;
        RECT  0 11.952 0.084 11.976 ;
    END
  END in_t[74]
  PIN in_t[75]
    DIRECTION INPUT ;
    USE SIGNAL ;
    PORT
      LAYER M4 ;
        RECT  0 12.048 0.084 12.072 ;
    END
  END in_t[75]
  PIN in_t[76]
    DIRECTION INPUT ;
    USE SIGNAL ;
    PORT
      LAYER M4 ;
        RECT  0 12.144 0.084 12.168 ;
    END
  END in_t[76]
  PIN in_t[77]
    DIRECTION INPUT ;
    USE SIGNAL ;
    PORT
      LAYER M4 ;
        RECT  0 12.24 0.084 12.264 ;
    END
  END in_t[77]
  PIN in_t[78]
    DIRECTION INPUT ;
    USE SIGNAL ;
    PORT
      LAYER M4 ;
        RECT  0 12.336 0.084 12.36 ;
    END
  END in_t[78]
  PIN in_t[79]
    DIRECTION INPUT ;
    USE SIGNAL ;
    PORT
      LAYER M4 ;
        RECT  0 12.432 0.084 12.456 ;
    END
  END in_t[79]
  PIN in_t[7]
    DIRECTION INPUT ;
    USE SIGNAL ;
    PORT
      LAYER M4 ;
        RECT  0 24.72 0.084 24.744 ;
    END
  END in_t[7]
  PIN in_t[80]
    DIRECTION INPUT ;
    USE SIGNAL ;
    PORT
      LAYER M4 ;
        RECT  0 12.528 0.084 12.552 ;
    END
  END in_t[80]
  PIN in_t[81]
    DIRECTION INPUT ;
    USE SIGNAL ;
    PORT
      LAYER M4 ;
        RECT  0 12.624 0.084 12.648 ;
    END
  END in_t[81]
  PIN in_t[82]
    DIRECTION INPUT ;
    USE SIGNAL ;
    PORT
      LAYER M4 ;
        RECT  0 12.72 0.084 12.744 ;
    END
  END in_t[82]
  PIN in_t[83]
    DIRECTION INPUT ;
    USE SIGNAL ;
    PORT
      LAYER M4 ;
        RECT  0 12.816 0.084 12.84 ;
    END
  END in_t[83]
  PIN in_t[84]
    DIRECTION INPUT ;
    USE SIGNAL ;
    PORT
      LAYER M4 ;
        RECT  0 12.912 0.084 12.936 ;
    END
  END in_t[84]
  PIN in_t[85]
    DIRECTION INPUT ;
    USE SIGNAL ;
    PORT
      LAYER M4 ;
        RECT  0 13.008 0.084 13.032 ;
    END
  END in_t[85]
  PIN in_t[86]
    DIRECTION INPUT ;
    USE SIGNAL ;
    PORT
      LAYER M4 ;
        RECT  0 13.104 0.084 13.128 ;
    END
  END in_t[86]
  PIN in_t[87]
    DIRECTION INPUT ;
    USE SIGNAL ;
    PORT
      LAYER M4 ;
        RECT  0 13.2 0.084 13.224 ;
    END
  END in_t[87]
  PIN in_t[88]
    DIRECTION INPUT ;
    USE SIGNAL ;
    PORT
      LAYER M4 ;
        RECT  0 13.296 0.084 13.32 ;
    END
  END in_t[88]
  PIN in_t[89]
    DIRECTION INPUT ;
    USE SIGNAL ;
    PORT
      LAYER M4 ;
        RECT  0 13.392 0.084 13.416 ;
    END
  END in_t[89]
  PIN in_t[8]
    DIRECTION INPUT ;
    USE SIGNAL ;
    PORT
      LAYER M4 ;
        RECT  0 24.816 0.084 24.84 ;
    END
  END in_t[8]
  PIN in_t[90]
    DIRECTION INPUT ;
    USE SIGNAL ;
    PORT
      LAYER M4 ;
        RECT  0 13.488 0.084 13.512 ;
    END
  END in_t[90]
  PIN in_t[91]
    DIRECTION INPUT ;
    USE SIGNAL ;
    PORT
      LAYER M4 ;
        RECT  0 13.584 0.084 13.608 ;
    END
  END in_t[91]
  PIN in_t[92]
    DIRECTION INPUT ;
    USE SIGNAL ;
    PORT
      LAYER M4 ;
        RECT  0 13.68 0.084 13.704 ;
    END
  END in_t[92]
  PIN in_t[93]
    DIRECTION INPUT ;
    USE SIGNAL ;
    PORT
      LAYER M4 ;
        RECT  0 13.776 0.084 13.8 ;
    END
  END in_t[93]
  PIN in_t[94]
    DIRECTION INPUT ;
    USE SIGNAL ;
    PORT
      LAYER M4 ;
        RECT  0 13.872 0.084 13.896 ;
    END
  END in_t[94]
  PIN in_t[95]
    DIRECTION INPUT ;
    USE SIGNAL ;
    PORT
      LAYER M4 ;
        RECT  0 13.968 0.084 13.992 ;
    END
  END in_t[95]
  PIN in_t[96]
    DIRECTION INPUT ;
    USE SIGNAL ;
    PORT
      LAYER M4 ;
        RECT  0 14.832 0.084 14.856 ;
    END
  END in_t[96]
  PIN in_t[97]
    DIRECTION INPUT ;
    USE SIGNAL ;
    PORT
      LAYER M4 ;
        RECT  0 14.928 0.084 14.952 ;
    END
  END in_t[97]
  PIN in_t[98]
    DIRECTION INPUT ;
    USE SIGNAL ;
    PORT
      LAYER M4 ;
        RECT  0 15.024 0.084 15.048 ;
    END
  END in_t[98]
  PIN in_t[99]
    DIRECTION INPUT ;
    USE SIGNAL ;
    PORT
      LAYER M4 ;
        RECT  0 15.12 0.084 15.144 ;
    END
  END in_t[99]
  PIN in_t[9]
    DIRECTION INPUT ;
    USE SIGNAL ;
    PORT
      LAYER M4 ;
        RECT  0 24.912 0.084 24.936 ;
    END
  END in_t[9]
  PIN in_valid[0]
    DIRECTION INPUT ;
    USE SIGNAL ;
    PORT
      LAYER M4 ;
        RECT  0 16.368 0.084 16.392 ;
    END
  END in_valid[0]
  PIN in_valid[1]
    DIRECTION INPUT ;
    USE SIGNAL ;
    PORT
      LAYER M4 ;
        RECT  0 16.464 0.084 16.488 ;
    END
  END in_valid[1]
  PIN in_valid[2]
    DIRECTION INPUT ;
    USE SIGNAL ;
    PORT
      LAYER M4 ;
        RECT  0 16.56 0.084 16.584 ;
    END
  END in_valid[2]
  PIN in_valid[3]
    DIRECTION INPUT ;
    USE SIGNAL ;
    PORT
      LAYER M4 ;
        RECT  0 16.656 0.084 16.68 ;
    END
  END in_valid[3]
  PIN in_valid[4]
    DIRECTION INPUT ;
    USE SIGNAL ;
    PORT
      LAYER M4 ;
        RECT  0 16.752 0.084 16.776 ;
    END
  END in_valid[4]
  PIN in_valid[5]
    DIRECTION INPUT ;
    USE SIGNAL ;
    PORT
      LAYER M4 ;
        RECT  0 16.848 0.084 16.872 ;
    END
  END in_valid[5]
  PIN in_valid[6]
    DIRECTION INPUT ;
    USE SIGNAL ;
    PORT
      LAYER M4 ;
        RECT  0 16.944 0.084 16.968 ;
    END
  END in_valid[6]
  PIN in_valid[7]
    DIRECTION INPUT ;
    USE SIGNAL ;
    PORT
      LAYER M4 ;
        RECT  0 17.04 0.084 17.064 ;
    END
  END in_valid[7]
  PIN out_age[0]
    DIRECTION OUTPUT ;
    USE SIGNAL ;
    PORT
      LAYER M5 ;
        RECT  20.016 0 20.04 0.084 ;
    END
  END out_age[0]
  PIN out_age[10]
    DIRECTION OUTPUT ;
    USE SIGNAL ;
    PORT
      LAYER M5 ;
        RECT  20.976 0 21 0.084 ;
    END
  END out_age[10]
  PIN out_age[11]
    DIRECTION OUTPUT ;
    USE SIGNAL ;
    PORT
      LAYER M5 ;
        RECT  21.072 0 21.096 0.084 ;
    END
  END out_age[11]
  PIN out_age[12]
    DIRECTION OUTPUT ;
    USE SIGNAL ;
    PORT
      LAYER M5 ;
        RECT  21.168 0 21.192 0.084 ;
    END
  END out_age[12]
  PIN out_age[13]
    DIRECTION OUTPUT ;
    USE SIGNAL ;
    PORT
      LAYER M5 ;
        RECT  21.264 0 21.288 0.084 ;
    END
  END out_age[13]
  PIN out_age[14]
    DIRECTION OUTPUT ;
    USE SIGNAL ;
    PORT
      LAYER M5 ;
        RECT  21.36 0 21.384 0.084 ;
    END
  END out_age[14]
  PIN out_age[15]
    DIRECTION OUTPUT ;
    USE SIGNAL ;
    PORT
      LAYER M5 ;
        RECT  21.456 0 21.48 0.084 ;
    END
  END out_age[15]
  PIN out_age[1]
    DIRECTION OUTPUT ;
    USE SIGNAL ;
    PORT
      LAYER M5 ;
        RECT  20.112 0 20.136 0.084 ;
    END
  END out_age[1]
  PIN out_age[2]
    DIRECTION OUTPUT ;
    USE SIGNAL ;
    PORT
      LAYER M5 ;
        RECT  20.208 0 20.232 0.084 ;
    END
  END out_age[2]
  PIN out_age[3]
    DIRECTION OUTPUT ;
    USE SIGNAL ;
    PORT
      LAYER M5 ;
        RECT  20.304 0 20.328 0.084 ;
    END
  END out_age[3]
  PIN out_age[4]
    DIRECTION OUTPUT ;
    USE SIGNAL ;
    PORT
      LAYER M5 ;
        RECT  20.4 0 20.424 0.084 ;
    END
  END out_age[4]
  PIN out_age[5]
    DIRECTION OUTPUT ;
    USE SIGNAL ;
    PORT
      LAYER M5 ;
        RECT  20.496 0 20.52 0.084 ;
    END
  END out_age[5]
  PIN out_age[6]
    DIRECTION OUTPUT ;
    USE SIGNAL ;
    PORT
      LAYER M5 ;
        RECT  20.592 0 20.616 0.084 ;
    END
  END out_age[6]
  PIN out_age[7]
    DIRECTION OUTPUT ;
    USE SIGNAL ;
    PORT
      LAYER M5 ;
        RECT  20.688 0 20.712 0.084 ;
    END
  END out_age[7]
  PIN out_age[8]
    DIRECTION OUTPUT ;
    USE SIGNAL ;
    PORT
      LAYER M5 ;
        RECT  20.784 0 20.808 0.084 ;
    END
  END out_age[8]
  PIN out_age[9]
    DIRECTION OUTPUT ;
    USE SIGNAL ;
    PORT
      LAYER M5 ;
        RECT  20.88 0 20.904 0.084 ;
    END
  END out_age[9]
  PIN out_epoch[0]
    DIRECTION OUTPUT ;
    USE SIGNAL ;
    PORT
      LAYER M5 ;
        RECT  21.552 0 21.576 0.084 ;
    END
  END out_epoch[0]
  PIN out_epoch[10]
    DIRECTION OUTPUT ;
    USE SIGNAL ;
    PORT
      LAYER M5 ;
        RECT  22.512 0 22.536 0.084 ;
    END
  END out_epoch[10]
  PIN out_epoch[11]
    DIRECTION OUTPUT ;
    USE SIGNAL ;
    PORT
      LAYER M5 ;
        RECT  22.608 0 22.632 0.084 ;
    END
  END out_epoch[11]
  PIN out_epoch[12]
    DIRECTION OUTPUT ;
    USE SIGNAL ;
    PORT
      LAYER M5 ;
        RECT  22.704 0 22.728 0.084 ;
    END
  END out_epoch[12]
  PIN out_epoch[13]
    DIRECTION OUTPUT ;
    USE SIGNAL ;
    PORT
      LAYER M5 ;
        RECT  22.8 0 22.824 0.084 ;
    END
  END out_epoch[13]
  PIN out_epoch[14]
    DIRECTION OUTPUT ;
    USE SIGNAL ;
    PORT
      LAYER M5 ;
        RECT  22.896 0 22.92 0.084 ;
    END
  END out_epoch[14]
  PIN out_epoch[15]
    DIRECTION OUTPUT ;
    USE SIGNAL ;
    PORT
      LAYER M5 ;
        RECT  9.936 0 9.96 0.084 ;
    END
  END out_epoch[15]
  PIN out_epoch[1]
    DIRECTION OUTPUT ;
    USE SIGNAL ;
    PORT
      LAYER M5 ;
        RECT  21.648 0 21.672 0.084 ;
    END
  END out_epoch[1]
  PIN out_epoch[2]
    DIRECTION OUTPUT ;
    USE SIGNAL ;
    PORT
      LAYER M5 ;
        RECT  21.744 0 21.768 0.084 ;
    END
  END out_epoch[2]
  PIN out_epoch[3]
    DIRECTION OUTPUT ;
    USE SIGNAL ;
    PORT
      LAYER M5 ;
        RECT  21.84 0 21.864 0.084 ;
    END
  END out_epoch[3]
  PIN out_epoch[4]
    DIRECTION OUTPUT ;
    USE SIGNAL ;
    PORT
      LAYER M5 ;
        RECT  21.936 0 21.96 0.084 ;
    END
  END out_epoch[4]
  PIN out_epoch[5]
    DIRECTION OUTPUT ;
    USE SIGNAL ;
    PORT
      LAYER M5 ;
        RECT  22.032 0 22.056 0.084 ;
    END
  END out_epoch[5]
  PIN out_epoch[6]
    DIRECTION OUTPUT ;
    USE SIGNAL ;
    PORT
      LAYER M5 ;
        RECT  22.128 0 22.152 0.084 ;
    END
  END out_epoch[6]
  PIN out_epoch[7]
    DIRECTION OUTPUT ;
    USE SIGNAL ;
    PORT
      LAYER M5 ;
        RECT  22.224 0 22.248 0.084 ;
    END
  END out_epoch[7]
  PIN out_epoch[8]
    DIRECTION OUTPUT ;
    USE SIGNAL ;
    PORT
      LAYER M5 ;
        RECT  22.32 0 22.344 0.084 ;
    END
  END out_epoch[8]
  PIN out_epoch[9]
    DIRECTION OUTPUT ;
    USE SIGNAL ;
    PORT
      LAYER M5 ;
        RECT  22.416 0 22.44 0.084 ;
    END
  END out_epoch[9]
  PIN pair_id
    DIRECTION INPUT ;
    USE SIGNAL ;
    PORT
      LAYER M5 ;
        RECT  10.032 0 10.056 0.084 ;
    END
  END pair_id
  PIN req_t[0]
    DIRECTION OUTPUT ;
    USE SIGNAL ;
    PORT
      LAYER M4 ;
        RECT  43.116 39.12 43.2 39.144 ;
    END
  END req_t[0]
  PIN req_t[100]
    DIRECTION OUTPUT ;
    USE SIGNAL ;
    PORT
      LAYER M4 ;
        RECT  43.116 32.592 43.2 32.616 ;
    END
  END req_t[100]
  PIN req_t[101]
    DIRECTION OUTPUT ;
    USE SIGNAL ;
    PORT
      LAYER M4 ;
        RECT  43.116 32.688 43.2 32.712 ;
    END
  END req_t[101]
  PIN req_t[102]
    DIRECTION OUTPUT ;
    USE SIGNAL ;
    PORT
      LAYER M4 ;
        RECT  43.116 32.784 43.2 32.808 ;
    END
  END req_t[102]
  PIN req_t[103]
    DIRECTION OUTPUT ;
    USE SIGNAL ;
    PORT
      LAYER M4 ;
        RECT  43.116 32.88 43.2 32.904 ;
    END
  END req_t[103]
  PIN req_t[104]
    DIRECTION OUTPUT ;
    USE SIGNAL ;
    PORT
      LAYER M4 ;
        RECT  43.116 32.976 43.2 33 ;
    END
  END req_t[104]
  PIN req_t[105]
    DIRECTION OUTPUT ;
    USE SIGNAL ;
    PORT
      LAYER M4 ;
        RECT  43.116 33.072 43.2 33.096 ;
    END
  END req_t[105]
  PIN req_t[106]
    DIRECTION OUTPUT ;
    USE SIGNAL ;
    PORT
      LAYER M4 ;
        RECT  43.116 33.168 43.2 33.192 ;
    END
  END req_t[106]
  PIN req_t[107]
    DIRECTION OUTPUT ;
    USE SIGNAL ;
    PORT
      LAYER M4 ;
        RECT  43.116 33.264 43.2 33.288 ;
    END
  END req_t[107]
  PIN req_t[108]
    DIRECTION OUTPUT ;
    USE SIGNAL ;
    PORT
      LAYER M4 ;
        RECT  43.116 33.36 43.2 33.384 ;
    END
  END req_t[108]
  PIN req_t[109]
    DIRECTION OUTPUT ;
    USE SIGNAL ;
    PORT
      LAYER M4 ;
        RECT  43.116 33.456 43.2 33.48 ;
    END
  END req_t[109]
  PIN req_t[10]
    DIRECTION OUTPUT ;
    USE SIGNAL ;
    PORT
      LAYER M4 ;
        RECT  43.116 40.08 43.2 40.104 ;
    END
  END req_t[10]
  PIN req_t[110]
    DIRECTION OUTPUT ;
    USE SIGNAL ;
    PORT
      LAYER M4 ;
        RECT  43.116 33.552 43.2 33.576 ;
    END
  END req_t[110]
  PIN req_t[111]
    DIRECTION OUTPUT ;
    USE SIGNAL ;
    PORT
      LAYER M4 ;
        RECT  43.116 33.648 43.2 33.672 ;
    END
  END req_t[111]
  PIN req_t[11]
    DIRECTION OUTPUT ;
    USE SIGNAL ;
    PORT
      LAYER M4 ;
        RECT  43.116 40.176 43.2 40.2 ;
    END
  END req_t[11]
  PIN req_t[12]
    DIRECTION OUTPUT ;
    USE SIGNAL ;
    PORT
      LAYER M4 ;
        RECT  43.116 40.272 43.2 40.296 ;
    END
  END req_t[12]
  PIN req_t[13]
    DIRECTION OUTPUT ;
    USE SIGNAL ;
    PORT
      LAYER M4 ;
        RECT  43.116 40.368 43.2 40.392 ;
    END
  END req_t[13]
  PIN req_t[14]
    DIRECTION OUTPUT ;
    USE SIGNAL ;
    PORT
      LAYER M4 ;
        RECT  43.116 40.464 43.2 40.488 ;
    END
  END req_t[14]
  PIN req_t[15]
    DIRECTION OUTPUT ;
    USE SIGNAL ;
    PORT
      LAYER M4 ;
        RECT  43.116 40.56 43.2 40.584 ;
    END
  END req_t[15]
  PIN req_t[16]
    DIRECTION OUTPUT ;
    USE SIGNAL ;
    PORT
      LAYER M4 ;
        RECT  43.116 40.656 43.2 40.68 ;
    END
  END req_t[16]
  PIN req_t[17]
    DIRECTION OUTPUT ;
    USE SIGNAL ;
    PORT
      LAYER M4 ;
        RECT  43.116 40.752 43.2 40.776 ;
    END
  END req_t[17]
  PIN req_t[18]
    DIRECTION OUTPUT ;
    USE SIGNAL ;
    PORT
      LAYER M4 ;
        RECT  43.116 40.848 43.2 40.872 ;
    END
  END req_t[18]
  PIN req_t[19]
    DIRECTION OUTPUT ;
    USE SIGNAL ;
    PORT
      LAYER M4 ;
        RECT  43.116 40.944 43.2 40.968 ;
    END
  END req_t[19]
  PIN req_t[1]
    DIRECTION OUTPUT ;
    USE SIGNAL ;
    PORT
      LAYER M4 ;
        RECT  43.116 39.216 43.2 39.24 ;
    END
  END req_t[1]
  PIN req_t[20]
    DIRECTION OUTPUT ;
    USE SIGNAL ;
    PORT
      LAYER M4 ;
        RECT  43.116 41.04 43.2 41.064 ;
    END
  END req_t[20]
  PIN req_t[21]
    DIRECTION OUTPUT ;
    USE SIGNAL ;
    PORT
      LAYER M4 ;
        RECT  43.116 41.136 43.2 41.16 ;
    END
  END req_t[21]
  PIN req_t[22]
    DIRECTION OUTPUT ;
    USE SIGNAL ;
    PORT
      LAYER M4 ;
        RECT  43.116 41.232 43.2 41.256 ;
    END
  END req_t[22]
  PIN req_t[23]
    DIRECTION OUTPUT ;
    USE SIGNAL ;
    PORT
      LAYER M4 ;
        RECT  43.116 41.328 43.2 41.352 ;
    END
  END req_t[23]
  PIN req_t[24]
    DIRECTION OUTPUT ;
    USE SIGNAL ;
    PORT
      LAYER M4 ;
        RECT  43.116 41.424 43.2 41.448 ;
    END
  END req_t[24]
  PIN req_t[25]
    DIRECTION OUTPUT ;
    USE SIGNAL ;
    PORT
      LAYER M4 ;
        RECT  43.116 41.52 43.2 41.544 ;
    END
  END req_t[25]
  PIN req_t[26]
    DIRECTION OUTPUT ;
    USE SIGNAL ;
    PORT
      LAYER M4 ;
        RECT  43.116 41.616 43.2 41.64 ;
    END
  END req_t[26]
  PIN req_t[27]
    DIRECTION OUTPUT ;
    USE SIGNAL ;
    PORT
      LAYER M4 ;
        RECT  43.116 41.712 43.2 41.736 ;
    END
  END req_t[27]
  PIN req_t[28]
    DIRECTION OUTPUT ;
    USE SIGNAL ;
    PORT
      LAYER M4 ;
        RECT  43.116 41.808 43.2 41.832 ;
    END
  END req_t[28]
  PIN req_t[29]
    DIRECTION OUTPUT ;
    USE SIGNAL ;
    PORT
      LAYER M4 ;
        RECT  43.116 41.904 43.2 41.928 ;
    END
  END req_t[29]
  PIN req_t[2]
    DIRECTION OUTPUT ;
    USE SIGNAL ;
    PORT
      LAYER M4 ;
        RECT  43.116 39.312 43.2 39.336 ;
    END
  END req_t[2]
  PIN req_t[30]
    DIRECTION OUTPUT ;
    USE SIGNAL ;
    PORT
      LAYER M4 ;
        RECT  43.116 42 43.2 42.024 ;
    END
  END req_t[30]
  PIN req_t[31]
    DIRECTION OUTPUT ;
    USE SIGNAL ;
    PORT
      LAYER M4 ;
        RECT  43.116 42.096 43.2 42.12 ;
    END
  END req_t[31]
  PIN req_t[32]
    DIRECTION OUTPUT ;
    USE SIGNAL ;
    PORT
      LAYER M4 ;
        RECT  43.116 35.28 43.2 35.304 ;
    END
  END req_t[32]
  PIN req_t[33]
    DIRECTION OUTPUT ;
    USE SIGNAL ;
    PORT
      LAYER M4 ;
        RECT  43.116 35.376 43.2 35.4 ;
    END
  END req_t[33]
  PIN req_t[34]
    DIRECTION OUTPUT ;
    USE SIGNAL ;
    PORT
      LAYER M4 ;
        RECT  43.116 35.472 43.2 35.496 ;
    END
  END req_t[34]
  PIN req_t[35]
    DIRECTION OUTPUT ;
    USE SIGNAL ;
    PORT
      LAYER M4 ;
        RECT  43.116 35.568 43.2 35.592 ;
    END
  END req_t[35]
  PIN req_t[36]
    DIRECTION OUTPUT ;
    USE SIGNAL ;
    PORT
      LAYER M4 ;
        RECT  43.116 35.664 43.2 35.688 ;
    END
  END req_t[36]
  PIN req_t[37]
    DIRECTION OUTPUT ;
    USE SIGNAL ;
    PORT
      LAYER M4 ;
        RECT  43.116 35.76 43.2 35.784 ;
    END
  END req_t[37]
  PIN req_t[38]
    DIRECTION OUTPUT ;
    USE SIGNAL ;
    PORT
      LAYER M4 ;
        RECT  43.116 35.856 43.2 35.88 ;
    END
  END req_t[38]
  PIN req_t[39]
    DIRECTION OUTPUT ;
    USE SIGNAL ;
    PORT
      LAYER M4 ;
        RECT  43.116 35.952 43.2 35.976 ;
    END
  END req_t[39]
  PIN req_t[3]
    DIRECTION OUTPUT ;
    USE SIGNAL ;
    PORT
      LAYER M4 ;
        RECT  43.116 39.408 43.2 39.432 ;
    END
  END req_t[3]
  PIN req_t[40]
    DIRECTION OUTPUT ;
    USE SIGNAL ;
    PORT
      LAYER M4 ;
        RECT  43.116 36.048 43.2 36.072 ;
    END
  END req_t[40]
  PIN req_t[41]
    DIRECTION OUTPUT ;
    USE SIGNAL ;
    PORT
      LAYER M4 ;
        RECT  43.116 36.144 43.2 36.168 ;
    END
  END req_t[41]
  PIN req_t[42]
    DIRECTION OUTPUT ;
    USE SIGNAL ;
    PORT
      LAYER M4 ;
        RECT  43.116 36.24 43.2 36.264 ;
    END
  END req_t[42]
  PIN req_t[43]
    DIRECTION OUTPUT ;
    USE SIGNAL ;
    PORT
      LAYER M4 ;
        RECT  43.116 36.336 43.2 36.36 ;
    END
  END req_t[43]
  PIN req_t[44]
    DIRECTION OUTPUT ;
    USE SIGNAL ;
    PORT
      LAYER M4 ;
        RECT  43.116 36.432 43.2 36.456 ;
    END
  END req_t[44]
  PIN req_t[45]
    DIRECTION OUTPUT ;
    USE SIGNAL ;
    PORT
      LAYER M4 ;
        RECT  43.116 36.528 43.2 36.552 ;
    END
  END req_t[45]
  PIN req_t[46]
    DIRECTION OUTPUT ;
    USE SIGNAL ;
    PORT
      LAYER M4 ;
        RECT  43.116 36.624 43.2 36.648 ;
    END
  END req_t[46]
  PIN req_t[47]
    DIRECTION OUTPUT ;
    USE SIGNAL ;
    PORT
      LAYER M4 ;
        RECT  43.116 36.72 43.2 36.744 ;
    END
  END req_t[47]
  PIN req_t[48]
    DIRECTION OUTPUT ;
    USE SIGNAL ;
    PORT
      LAYER M4 ;
        RECT  43.116 36.816 43.2 36.84 ;
    END
  END req_t[48]
  PIN req_t[49]
    DIRECTION OUTPUT ;
    USE SIGNAL ;
    PORT
      LAYER M4 ;
        RECT  43.116 36.912 43.2 36.936 ;
    END
  END req_t[49]
  PIN req_t[4]
    DIRECTION OUTPUT ;
    USE SIGNAL ;
    PORT
      LAYER M4 ;
        RECT  43.116 39.504 43.2 39.528 ;
    END
  END req_t[4]
  PIN req_t[50]
    DIRECTION OUTPUT ;
    USE SIGNAL ;
    PORT
      LAYER M4 ;
        RECT  43.116 37.008 43.2 37.032 ;
    END
  END req_t[50]
  PIN req_t[51]
    DIRECTION OUTPUT ;
    USE SIGNAL ;
    PORT
      LAYER M4 ;
        RECT  43.116 37.104 43.2 37.128 ;
    END
  END req_t[51]
  PIN req_t[52]
    DIRECTION OUTPUT ;
    USE SIGNAL ;
    PORT
      LAYER M4 ;
        RECT  43.116 37.2 43.2 37.224 ;
    END
  END req_t[52]
  PIN req_t[53]
    DIRECTION OUTPUT ;
    USE SIGNAL ;
    PORT
      LAYER M4 ;
        RECT  43.116 37.296 43.2 37.32 ;
    END
  END req_t[53]
  PIN req_t[54]
    DIRECTION OUTPUT ;
    USE SIGNAL ;
    PORT
      LAYER M4 ;
        RECT  43.116 37.392 43.2 37.416 ;
    END
  END req_t[54]
  PIN req_t[55]
    DIRECTION OUTPUT ;
    USE SIGNAL ;
    PORT
      LAYER M4 ;
        RECT  43.116 37.488 43.2 37.512 ;
    END
  END req_t[55]
  PIN req_t[56]
    DIRECTION OUTPUT ;
    USE SIGNAL ;
    PORT
      LAYER M4 ;
        RECT  43.116 37.584 43.2 37.608 ;
    END
  END req_t[56]
  PIN req_t[57]
    DIRECTION OUTPUT ;
    USE SIGNAL ;
    PORT
      LAYER M4 ;
        RECT  43.116 37.68 43.2 37.704 ;
    END
  END req_t[57]
  PIN req_t[58]
    DIRECTION OUTPUT ;
    USE SIGNAL ;
    PORT
      LAYER M4 ;
        RECT  43.116 37.776 43.2 37.8 ;
    END
  END req_t[58]
  PIN req_t[59]
    DIRECTION OUTPUT ;
    USE SIGNAL ;
    PORT
      LAYER M4 ;
        RECT  43.116 37.872 43.2 37.896 ;
    END
  END req_t[59]
  PIN req_t[5]
    DIRECTION OUTPUT ;
    USE SIGNAL ;
    PORT
      LAYER M4 ;
        RECT  43.116 39.6 43.2 39.624 ;
    END
  END req_t[5]
  PIN req_t[60]
    DIRECTION OUTPUT ;
    USE SIGNAL ;
    PORT
      LAYER M4 ;
        RECT  43.116 37.968 43.2 37.992 ;
    END
  END req_t[60]
  PIN req_t[61]
    DIRECTION OUTPUT ;
    USE SIGNAL ;
    PORT
      LAYER M4 ;
        RECT  43.116 38.064 43.2 38.088 ;
    END
  END req_t[61]
  PIN req_t[62]
    DIRECTION OUTPUT ;
    USE SIGNAL ;
    PORT
      LAYER M4 ;
        RECT  43.116 38.16 43.2 38.184 ;
    END
  END req_t[62]
  PIN req_t[63]
    DIRECTION OUTPUT ;
    USE SIGNAL ;
    PORT
      LAYER M4 ;
        RECT  43.116 38.256 43.2 38.28 ;
    END
  END req_t[63]
  PIN req_t[64]
    DIRECTION OUTPUT ;
    USE SIGNAL ;
    PORT
      LAYER M4 ;
        RECT  43.116 29.136 43.2 29.16 ;
    END
  END req_t[64]
  PIN req_t[65]
    DIRECTION OUTPUT ;
    USE SIGNAL ;
    PORT
      LAYER M4 ;
        RECT  43.116 29.232 43.2 29.256 ;
    END
  END req_t[65]
  PIN req_t[66]
    DIRECTION OUTPUT ;
    USE SIGNAL ;
    PORT
      LAYER M4 ;
        RECT  43.116 29.328 43.2 29.352 ;
    END
  END req_t[66]
  PIN req_t[67]
    DIRECTION OUTPUT ;
    USE SIGNAL ;
    PORT
      LAYER M4 ;
        RECT  43.116 29.424 43.2 29.448 ;
    END
  END req_t[67]
  PIN req_t[68]
    DIRECTION OUTPUT ;
    USE SIGNAL ;
    PORT
      LAYER M4 ;
        RECT  43.116 29.52 43.2 29.544 ;
    END
  END req_t[68]
  PIN req_t[69]
    DIRECTION OUTPUT ;
    USE SIGNAL ;
    PORT
      LAYER M4 ;
        RECT  43.116 29.616 43.2 29.64 ;
    END
  END req_t[69]
  PIN req_t[6]
    DIRECTION OUTPUT ;
    USE SIGNAL ;
    PORT
      LAYER M4 ;
        RECT  43.116 39.696 43.2 39.72 ;
    END
  END req_t[6]
  PIN req_t[70]
    DIRECTION OUTPUT ;
    USE SIGNAL ;
    PORT
      LAYER M4 ;
        RECT  43.116 29.712 43.2 29.736 ;
    END
  END req_t[70]
  PIN req_t[71]
    DIRECTION OUTPUT ;
    USE SIGNAL ;
    PORT
      LAYER M4 ;
        RECT  43.116 29.808 43.2 29.832 ;
    END
  END req_t[71]
  PIN req_t[72]
    DIRECTION OUTPUT ;
    USE SIGNAL ;
    PORT
      LAYER M4 ;
        RECT  43.116 29.904 43.2 29.928 ;
    END
  END req_t[72]
  PIN req_t[73]
    DIRECTION OUTPUT ;
    USE SIGNAL ;
    PORT
      LAYER M4 ;
        RECT  43.116 30 43.2 30.024 ;
    END
  END req_t[73]
  PIN req_t[74]
    DIRECTION OUTPUT ;
    USE SIGNAL ;
    PORT
      LAYER M4 ;
        RECT  43.116 30.096 43.2 30.12 ;
    END
  END req_t[74]
  PIN req_t[75]
    DIRECTION OUTPUT ;
    USE SIGNAL ;
    PORT
      LAYER M4 ;
        RECT  43.116 30.192 43.2 30.216 ;
    END
  END req_t[75]
  PIN req_t[76]
    DIRECTION OUTPUT ;
    USE SIGNAL ;
    PORT
      LAYER M4 ;
        RECT  43.116 30.288 43.2 30.312 ;
    END
  END req_t[76]
  PIN req_t[77]
    DIRECTION OUTPUT ;
    USE SIGNAL ;
    PORT
      LAYER M4 ;
        RECT  43.116 30.384 43.2 30.408 ;
    END
  END req_t[77]
  PIN req_t[78]
    DIRECTION OUTPUT ;
    USE SIGNAL ;
    PORT
      LAYER M4 ;
        RECT  43.116 30.48 43.2 30.504 ;
    END
  END req_t[78]
  PIN req_t[79]
    DIRECTION OUTPUT ;
    USE SIGNAL ;
    PORT
      LAYER M4 ;
        RECT  43.116 30.576 43.2 30.6 ;
    END
  END req_t[79]
  PIN req_t[7]
    DIRECTION OUTPUT ;
    USE SIGNAL ;
    PORT
      LAYER M4 ;
        RECT  43.116 39.792 43.2 39.816 ;
    END
  END req_t[7]
  PIN req_t[80]
    DIRECTION OUTPUT ;
    USE SIGNAL ;
    PORT
      LAYER M4 ;
        RECT  43.116 30.672 43.2 30.696 ;
    END
  END req_t[80]
  PIN req_t[81]
    DIRECTION OUTPUT ;
    USE SIGNAL ;
    PORT
      LAYER M4 ;
        RECT  43.116 30.768 43.2 30.792 ;
    END
  END req_t[81]
  PIN req_t[82]
    DIRECTION OUTPUT ;
    USE SIGNAL ;
    PORT
      LAYER M4 ;
        RECT  43.116 30.864 43.2 30.888 ;
    END
  END req_t[82]
  PIN req_t[83]
    DIRECTION OUTPUT ;
    USE SIGNAL ;
    PORT
      LAYER M4 ;
        RECT  43.116 30.96 43.2 30.984 ;
    END
  END req_t[83]
  PIN req_t[84]
    DIRECTION OUTPUT ;
    USE SIGNAL ;
    PORT
      LAYER M4 ;
        RECT  43.116 31.056 43.2 31.08 ;
    END
  END req_t[84]
  PIN req_t[85]
    DIRECTION OUTPUT ;
    USE SIGNAL ;
    PORT
      LAYER M4 ;
        RECT  43.116 31.152 43.2 31.176 ;
    END
  END req_t[85]
  PIN req_t[86]
    DIRECTION OUTPUT ;
    USE SIGNAL ;
    PORT
      LAYER M4 ;
        RECT  43.116 31.248 43.2 31.272 ;
    END
  END req_t[86]
  PIN req_t[87]
    DIRECTION OUTPUT ;
    USE SIGNAL ;
    PORT
      LAYER M4 ;
        RECT  43.116 31.344 43.2 31.368 ;
    END
  END req_t[87]
  PIN req_t[88]
    DIRECTION OUTPUT ;
    USE SIGNAL ;
    PORT
      LAYER M4 ;
        RECT  43.116 31.44 43.2 31.464 ;
    END
  END req_t[88]
  PIN req_t[89]
    DIRECTION OUTPUT ;
    USE SIGNAL ;
    PORT
      LAYER M4 ;
        RECT  43.116 31.536 43.2 31.56 ;
    END
  END req_t[89]
  PIN req_t[8]
    DIRECTION OUTPUT ;
    USE SIGNAL ;
    PORT
      LAYER M4 ;
        RECT  43.116 39.888 43.2 39.912 ;
    END
  END req_t[8]
  PIN req_t[90]
    DIRECTION OUTPUT ;
    USE SIGNAL ;
    PORT
      LAYER M4 ;
        RECT  43.116 31.632 43.2 31.656 ;
    END
  END req_t[90]
  PIN req_t[91]
    DIRECTION OUTPUT ;
    USE SIGNAL ;
    PORT
      LAYER M4 ;
        RECT  43.116 31.728 43.2 31.752 ;
    END
  END req_t[91]
  PIN req_t[92]
    DIRECTION OUTPUT ;
    USE SIGNAL ;
    PORT
      LAYER M4 ;
        RECT  43.116 31.824 43.2 31.848 ;
    END
  END req_t[92]
  PIN req_t[93]
    DIRECTION OUTPUT ;
    USE SIGNAL ;
    PORT
      LAYER M4 ;
        RECT  43.116 31.92 43.2 31.944 ;
    END
  END req_t[93]
  PIN req_t[94]
    DIRECTION OUTPUT ;
    USE SIGNAL ;
    PORT
      LAYER M4 ;
        RECT  43.116 32.016 43.2 32.04 ;
    END
  END req_t[94]
  PIN req_t[95]
    DIRECTION OUTPUT ;
    USE SIGNAL ;
    PORT
      LAYER M4 ;
        RECT  43.116 32.112 43.2 32.136 ;
    END
  END req_t[95]
  PIN req_t[96]
    DIRECTION OUTPUT ;
    USE SIGNAL ;
    PORT
      LAYER M4 ;
        RECT  43.116 32.208 43.2 32.232 ;
    END
  END req_t[96]
  PIN req_t[97]
    DIRECTION OUTPUT ;
    USE SIGNAL ;
    PORT
      LAYER M4 ;
        RECT  43.116 32.304 43.2 32.328 ;
    END
  END req_t[97]
  PIN req_t[98]
    DIRECTION OUTPUT ;
    USE SIGNAL ;
    PORT
      LAYER M4 ;
        RECT  43.116 32.4 43.2 32.424 ;
    END
  END req_t[98]
  PIN req_t[99]
    DIRECTION OUTPUT ;
    USE SIGNAL ;
    PORT
      LAYER M4 ;
        RECT  43.116 32.496 43.2 32.52 ;
    END
  END req_t[99]
  PIN req_t[9]
    DIRECTION OUTPUT ;
    USE SIGNAL ;
    PORT
      LAYER M4 ;
        RECT  43.116 39.984 43.2 40.008 ;
    END
  END req_t[9]
  PIN req_valid[0]
    DIRECTION OUTPUT ;
    USE SIGNAL ;
    PORT
      LAYER M4 ;
        RECT  43.116 33.744 43.2 33.768 ;
    END
  END req_valid[0]
  PIN req_valid[1]
    DIRECTION OUTPUT ;
    USE SIGNAL ;
    PORT
      LAYER M4 ;
        RECT  43.116 33.84 43.2 33.864 ;
    END
  END req_valid[1]
  PIN req_valid[2]
    DIRECTION OUTPUT ;
    USE SIGNAL ;
    PORT
      LAYER M4 ;
        RECT  43.116 33.936 43.2 33.96 ;
    END
  END req_valid[2]
  PIN req_valid[3]
    DIRECTION OUTPUT ;
    USE SIGNAL ;
    PORT
      LAYER M4 ;
        RECT  43.116 34.032 43.2 34.056 ;
    END
  END req_valid[3]
  PIN req_valid[4]
    DIRECTION OUTPUT ;
    USE SIGNAL ;
    PORT
      LAYER M4 ;
        RECT  43.116 34.128 43.2 34.152 ;
    END
  END req_valid[4]
  PIN req_valid[5]
    DIRECTION OUTPUT ;
    USE SIGNAL ;
    PORT
      LAYER M4 ;
        RECT  43.116 34.224 43.2 34.248 ;
    END
  END req_valid[5]
  PIN req_valid[6]
    DIRECTION OUTPUT ;
    USE SIGNAL ;
    PORT
      LAYER M4 ;
        RECT  43.116 34.32 43.2 34.344 ;
    END
  END req_valid[6]
  PIN req_valid[7]
    DIRECTION OUTPUT ;
    USE SIGNAL ;
    PORT
      LAYER M4 ;
        RECT  43.116 34.416 43.2 34.44 ;
    END
  END req_valid[7]
  PIN rst_n
    DIRECTION INPUT ;
    USE SIGNAL ;
    PORT
      LAYER M5 ;
        RECT  10.128 0 10.152 0.084 ;
    END
  END rst_n
  PIN start
    DIRECTION INPUT ;
    USE SIGNAL ;
    PORT
      LAYER M5 ;
        RECT  10.224 0 10.248 0.084 ;
    END
  END start
  PIN VDD
    DIRECTION INOUT ;
    USE POWER ;
    PORT
      LAYER M5 ;
        RECT  40.392 2.151 40.512 41.049 ;
        RECT  34.992 2.151 35.112 41.049 ;
        RECT  29.592 2.151 29.712 41.049 ;
        RECT  24.192 2.151 24.312 41.049 ;
        RECT  18.792 2.151 18.912 41.049 ;
        RECT  13.392 2.151 13.512 41.049 ;
        RECT  7.992 2.151 8.112 41.049 ;
        RECT  2.592 2.151 2.712 41.049 ;
    END
  END VDD
  PIN VSS
    DIRECTION INOUT ;
    USE GROUND ;
    PORT
      LAYER M5 ;
        RECT  40.2 2.137 40.32 41.063 ;
        RECT  34.8 2.137 34.92 41.063 ;
        RECT  29.4 2.137 29.52 41.063 ;
        RECT  24 2.137 24.12 41.063 ;
        RECT  18.6 2.137 18.72 41.063 ;
        RECT  13.2 2.137 13.32 41.063 ;
        RECT  7.8 2.137 7.92 41.063 ;
        RECT  2.4 2.137 2.52 41.063 ;
    END
  END VSS
  OBS
    LAYER RVTN ;
     RECT  2.16 2.16 41.04 2.295 ;
     RECT  2.16 2.565 41.04 2.835 ;
     RECT  2.16 3.105 41.04 3.375 ;
     RECT  2.16 3.645 41.04 3.915 ;
     RECT  2.16 4.185 41.04 4.455 ;
     RECT  2.16 4.725 41.04 4.995 ;
     RECT  2.16 5.265 41.04 5.535 ;
     RECT  2.16 5.805 41.04 6.075 ;
     RECT  2.16 6.345 41.04 6.615 ;
     RECT  2.16 6.885 41.04 7.155 ;
     RECT  2.16 7.425 41.04 7.695 ;
     RECT  2.16 7.965 41.04 8.235 ;
     RECT  2.16 8.505 41.04 8.775 ;
     RECT  2.16 9.045 41.04 9.315 ;
     RECT  2.16 9.585 41.04 9.855 ;
     RECT  2.16 10.125 41.04 10.395 ;
     RECT  2.16 10.665 41.04 10.935 ;
     RECT  2.16 11.205 41.04 11.475 ;
     RECT  2.16 11.745 41.04 12.015 ;
     RECT  2.16 12.285 41.04 12.555 ;
     RECT  2.16 12.825 41.04 13.095 ;
     RECT  2.16 13.365 41.04 13.635 ;
     RECT  2.16 13.905 41.04 14.175 ;
     RECT  2.16 14.445 41.04 14.715 ;
     RECT  2.16 14.985 41.04 15.255 ;
     RECT  2.16 15.525 41.04 15.795 ;
     RECT  2.16 16.065 41.04 16.335 ;
     RECT  2.16 16.605 41.04 16.875 ;
     RECT  2.16 17.145 41.04 17.415 ;
     RECT  2.16 17.685 41.04 17.955 ;
     RECT  2.16 18.225 41.04 18.495 ;
     RECT  2.16 18.765 41.04 19.035 ;
     RECT  2.16 19.305 41.04 19.575 ;
     RECT  2.16 19.845 41.04 20.115 ;
     RECT  2.16 20.385 41.04 20.655 ;
     RECT  2.16 20.925 41.04 21.195 ;
     RECT  2.16 21.465 41.04 21.735 ;
     RECT  2.16 22.005 41.04 22.275 ;
     RECT  2.16 22.545 41.04 22.815 ;
     RECT  2.16 23.085 41.04 23.355 ;
     RECT  2.16 23.625 41.04 23.895 ;
     RECT  2.16 24.165 41.04 24.435 ;
     RECT  2.16 24.705 41.04 24.975 ;
     RECT  2.16 25.245 41.04 25.515 ;
     RECT  2.16 25.785 41.04 26.055 ;
     RECT  2.16 26.325 41.04 26.595 ;
     RECT  2.16 26.865 41.04 27.135 ;
     RECT  2.16 27.405 41.04 27.675 ;
     RECT  2.16 27.945 41.04 28.215 ;
     RECT  2.16 28.485 41.04 28.755 ;
     RECT  2.16 29.025 41.04 29.295 ;
     RECT  2.16 29.565 41.04 29.835 ;
     RECT  2.16 30.105 41.04 30.375 ;
     RECT  2.16 30.645 41.04 30.915 ;
     RECT  2.16 31.185 41.04 31.455 ;
     RECT  2.16 31.725 41.04 31.995 ;
     RECT  2.16 32.265 41.04 32.535 ;
     RECT  2.16 32.805 41.04 33.075 ;
     RECT  2.16 33.345 41.04 33.615 ;
     RECT  2.16 33.885 41.04 34.155 ;
     RECT  2.16 34.425 41.04 34.695 ;
     RECT  2.16 34.965 41.04 35.235 ;
     RECT  2.16 35.505 41.04 35.775 ;
     RECT  2.16 36.045 41.04 36.315 ;
     RECT  2.16 36.585 41.04 36.855 ;
     RECT  2.16 37.125 41.04 37.395 ;
     RECT  2.16 37.665 41.04 37.935 ;
     RECT  2.16 38.205 41.04 38.475 ;
     RECT  2.16 38.745 41.04 39.015 ;
     RECT  2.16 39.285 41.04 39.555 ;
     RECT  2.16 39.825 41.04 40.095 ;
     RECT  2.16 40.365 41.04 40.635 ;
     RECT  2.16 40.905 41.04 41.04 ;
    LAYER RVTP ;
     RECT  2.16 2.295 41.04 2.565 ;
     RECT  2.16 2.835 41.04 3.105 ;
     RECT  2.16 3.375 41.04 3.645 ;
     RECT  2.16 3.915 41.04 4.185 ;
     RECT  2.16 4.455 41.04 4.725 ;
     RECT  2.16 4.995 41.04 5.265 ;
     RECT  2.16 5.535 41.04 5.805 ;
     RECT  2.16 6.075 41.04 6.345 ;
     RECT  2.16 6.615 41.04 6.885 ;
     RECT  2.16 7.155 41.04 7.425 ;
     RECT  2.16 7.695 41.04 7.965 ;
     RECT  2.16 8.235 41.04 8.505 ;
     RECT  2.16 8.775 41.04 9.045 ;
     RECT  2.16 9.315 41.04 9.585 ;
     RECT  2.16 9.855 41.04 10.125 ;
     RECT  2.16 10.395 41.04 10.665 ;
     RECT  2.16 10.935 41.04 11.205 ;
     RECT  2.16 11.475 41.04 11.745 ;
     RECT  2.16 12.015 41.04 12.285 ;
     RECT  2.16 12.555 41.04 12.825 ;
     RECT  2.16 13.095 41.04 13.365 ;
     RECT  2.16 13.635 41.04 13.905 ;
     RECT  2.16 14.175 41.04 14.445 ;
     RECT  2.16 14.715 41.04 14.985 ;
     RECT  2.16 15.255 41.04 15.525 ;
     RECT  2.16 15.795 41.04 16.065 ;
     RECT  2.16 16.335 41.04 16.605 ;
     RECT  2.16 16.875 41.04 17.145 ;
     RECT  2.16 17.415 41.04 17.685 ;
     RECT  2.16 17.955 41.04 18.225 ;
     RECT  2.16 18.495 41.04 18.765 ;
     RECT  2.16 19.035 41.04 19.305 ;
     RECT  2.16 19.575 41.04 19.845 ;
     RECT  2.16 20.115 41.04 20.385 ;
     RECT  2.16 20.655 41.04 20.925 ;
     RECT  2.16 21.195 41.04 21.465 ;
     RECT  2.16 21.735 41.04 22.005 ;
     RECT  2.16 22.275 41.04 22.545 ;
     RECT  2.16 22.815 41.04 23.085 ;
     RECT  2.16 23.355 41.04 23.625 ;
     RECT  2.16 23.895 41.04 24.165 ;
     RECT  2.16 24.435 41.04 24.705 ;
     RECT  2.16 24.975 41.04 25.245 ;
     RECT  2.16 25.515 41.04 25.785 ;
     RECT  2.16 26.055 41.04 26.325 ;
     RECT  2.16 26.595 41.04 26.865 ;
     RECT  2.16 27.135 41.04 27.405 ;
     RECT  2.16 27.675 41.04 27.945 ;
     RECT  2.16 28.215 41.04 28.485 ;
     RECT  2.16 28.755 41.04 29.025 ;
     RECT  2.16 29.295 41.04 29.565 ;
     RECT  2.16 29.835 41.04 30.105 ;
     RECT  2.16 30.375 41.04 30.645 ;
     RECT  2.16 30.915 41.04 31.185 ;
     RECT  2.16 31.455 41.04 31.725 ;
     RECT  2.16 31.995 41.04 32.265 ;
     RECT  2.16 32.535 41.04 32.805 ;
     RECT  2.16 33.075 41.04 33.345 ;
     RECT  2.16 33.615 41.04 33.885 ;
     RECT  2.16 34.155 41.04 34.425 ;
     RECT  2.16 34.695 41.04 34.965 ;
     RECT  2.16 35.235 41.04 35.505 ;
     RECT  2.16 35.775 41.04 36.045 ;
     RECT  2.16 36.315 41.04 36.585 ;
     RECT  2.16 36.855 41.04 37.125 ;
     RECT  2.16 37.395 41.04 37.665 ;
     RECT  2.16 37.935 41.04 38.205 ;
     RECT  2.16 38.475 41.04 38.745 ;
     RECT  2.16 39.015 41.04 39.285 ;
     RECT  2.16 39.555 41.04 39.825 ;
     RECT  2.16 40.095 41.04 40.365 ;
     RECT  2.16 40.635 41.04 40.905 ;
    LAYER M1 ;
     RECT  2.16 2.151 41.04 41.049 ;
    LAYER M2 ;
     RECT  0.103 23.904 0.139 24.498 ;
     RECT  0.103 27.882 0.175 27.9 ;
     RECT  0.103 26.1 0.211 26.118 ;
     RECT  0.103 37.566 0.239 37.584 ;
     RECT  0.103 16.002 0.347 16.362 ;
     RECT  0.139 23.67 0.535 24.498 ;
     RECT  0.211 26.1 0.535 26.586 ;
     RECT  0.175 27.342 0.535 27.9 ;
     RECT  0.103 28.962 0.535 28.98 ;
     RECT  0.103 32.238 0.535 32.256 ;
     RECT  1.651 40.104 1.687 40.122 ;
     RECT  1.687 39.564 1.723 40.122 ;
     RECT  1.723 39.564 1.831 40.32 ;
     RECT  0.103 14.76 2.16 14.778 ;
     RECT  0.535 23.67 2.16 25.038 ;
     RECT  0.535 26.1 2.16 28.98 ;
     RECT  0.535 32.238 2.16 32.328 ;
     RECT  1.831 39.564 2.16 40.662 ;
     RECT  2.16 2.151 21.415 41.049 ;
     RECT  21.415 1.998 21.955 41.049 ;
     RECT  21.955 1.962 24.151 41.049 ;
     RECT  24.151 1.881 26.087 41.049 ;
     RECT  26.087 2.106 26.195 41.049 ;
     RECT  26.195 2.151 40.099 41.049 ;
     RECT  40.099 2.151 40.415 41.094 ;
     RECT  40.415 2.151 41.04 41.049 ;
     RECT  41.04 33.12 41.639 34.254 ;
     RECT  41.04 27.18 41.891 32.364 ;
     RECT  41.891 27.576 41.927 32.184 ;
     RECT  41.04 35.01 42.035 38.466 ;
     RECT  42.035 35.01 42.107 38.196 ;
     RECT  41.639 33.156 42.143 34.254 ;
     RECT  41.04 40.266 42.143 40.554 ;
     RECT  42.143 33.426 42.179 34.254 ;
     RECT  42.107 35.01 42.179 35.154 ;
     RECT  42.143 40.266 42.179 40.284 ;
     RECT  41.927 28.386 42.215 32.184 ;
     RECT  42.179 33.426 42.215 33.678 ;
     RECT  42.215 28.386 42.251 31.716 ;
     RECT  42.215 33.66 42.251 33.678 ;
     RECT  42.251 28.386 42.323 30.096 ;
     RECT  42.323 28.386 42.359 28.674 ;
     RECT  42.251 30.996 42.431 31.716 ;
     RECT  42.359 28.656 43.043 28.674 ;
     RECT  42.107 36.018 43.051 38.196 ;
     RECT  41.927 27.576 43.079 27.594 ;
     RECT  42.323 29.538 43.079 30.096 ;
     RECT  42.179 35.01 43.079 35.064 ;
     RECT  43.079 29.538 43.115 29.556 ;
     RECT  42.431 31.698 43.115 31.716 ;
     RECT  43.015 34.164 43.115 34.182 ;
     RECT  43.051 36.018 43.115 38.772 ;
     RECT  43.115 36.594 43.151 36.612 ;
     RECT  43.115 38.754 43.151 38.772 ;
     RECT  43.079 35.01 43.187 35.028 ;
     RECT  43.087 39.762 43.187 39.78 ;
    LAYER M3 ;
     RECT  16.092 0.091 16.47 0.139 ;
     RECT  21.06 0.091 21.294 0.139 ;
     RECT  26.28 0.091 26.298 0.139 ;
     RECT  26.28 0.139 26.586 0.187 ;
     RECT  21.06 0.139 21.906 0.427 ;
     RECT  25.956 0.187 26.586 0.475 ;
     RECT  15.696 0.139 16.47 0.523 ;
     RECT  20.808 0.427 21.906 0.571 ;
     RECT  23.58 0.523 23.598 0.571 ;
     RECT  20.088 0.571 21.906 1.147 ;
     RECT  9.792 0.091 9.81 1.723 ;
     RECT  15.696 0.523 16.65 1.723 ;
     RECT  19.044 0.571 19.062 1.723 ;
     RECT  23.436 0.571 23.598 1.723 ;
     RECT  15.696 1.723 19.062 1.771 ;
     RECT  23.436 1.723 24.066 1.876 ;
     RECT  20.052 1.147 21.906 1.957 ;
     RECT  23.436 1.876 24.174 1.957 ;
     RECT  25.956 0.475 27.018 2.029 ;
     RECT  23.436 1.957 24.534 2.059 ;
     RECT  15.696 1.771 19.314 2.251 ;
     RECT  20.052 1.957 21.978 2.251 ;
     RECT  22.824 2.059 24.534 2.335 ;
     RECT  25.308 2.029 27.018 2.335 ;
     RECT  9.792 1.723 10.242 2.371 ;
     RECT  15.696 2.251 21.978 2.371 ;
     RECT  22.824 2.335 27.018 2.371 ;
     RECT  2.415 2.143 2.505 2.413 ;
     RECT  7.815 2.143 7.905 2.413 ;
     RECT  13.215 2.143 13.305 2.413 ;
     RECT  29.415 2.143 29.505 2.413 ;
     RECT  34.815 2.143 34.905 2.413 ;
     RECT  40.215 2.143 40.305 2.413 ;
     RECT  15.696 2.371 27.018 2.489 ;
     RECT  9.792 2.371 10.35 2.569 ;
     RECT  15.696 2.489 26.802 2.605 ;
     RECT  15.516 2.605 26.802 2.641 ;
     RECT  9.792 2.569 11.034 2.759 ;
     RECT  15.264 2.641 26.802 2.803 ;
     RECT  10.008 2.759 11.034 3.145 ;
     RECT  10.008 3.145 11.106 3.437 ;
     RECT  15.048 2.803 26.802 3.451 ;
     RECT  14.544 3.451 26.802 3.577 ;
     RECT  14.4 3.577 26.802 3.641 ;
     RECT  13.215 2.413 13.497 3.811 ;
     RECT  14.4 3.641 26.406 3.919 ;
     RECT  10.26 3.437 11.106 3.931 ;
     RECT  11.844 3.811 11.862 3.931 ;
     RECT  10.26 3.931 11.862 3.965 ;
     RECT  14.328 3.919 26.406 3.983 ;
     RECT  10.26 3.965 11.466 4.379 ;
     RECT  15.984 3.983 26.406 4.379 ;
     RECT  10.26 4.379 11.322 4.415 ;
     RECT  15.984 4.379 26.154 4.649 ;
     RECT  15.984 4.649 25.398 4.721 ;
     RECT  26.136 4.649 26.154 4.781 ;
     RECT  15.984 4.721 25.29 4.793 ;
     RECT  10.26 4.415 11.106 4.801 ;
     RECT  10.152 4.801 11.106 4.877 ;
     RECT  15.984 4.793 25.182 5.027 ;
     RECT  15.984 5.027 25.074 5.189 ;
     RECT  13.176 3.811 13.497 5.341 ;
     RECT  14.328 3.983 15.066 5.341 ;
     RECT  15.984 5.189 24.822 5.341 ;
     RECT  13.176 5.341 15.066 5.539 ;
     RECT  15.912 5.341 24.822 5.539 ;
     RECT  13.176 5.539 24.822 5.737 ;
     RECT  12.348 5.737 12.366 5.881 ;
     RECT  13.104 5.737 24.822 5.881 ;
     RECT  12.348 5.881 24.822 6.151 ;
     RECT  10.62 4.877 10.638 6.232 ;
     RECT  10.62 6.232 11.106 6.235 ;
     RECT  9.936 6.235 11.106 6.269 ;
     RECT  9.936 6.269 10.638 6.275 ;
     RECT  11.448 6.547 11.466 6.619 ;
     RECT  12.348 6.151 25.11 6.619 ;
     RECT  9.72 6.385 9.738 6.781 ;
     RECT  11.448 6.619 25.11 6.881 ;
     RECT  9 6.781 9.738 7.087 ;
     RECT  10.62 6.275 10.638 7.159 ;
     RECT  11.448 6.881 24.297 7.159 ;
     RECT  10.62 7.159 24.297 7.259 ;
     RECT  10.62 7.259 11.97 7.325 ;
     RECT  10.764 7.325 11.97 7.349 ;
     RECT  10.98 7.349 11.646 7.385 ;
     RECT  11.052 7.385 11.646 7.421 ;
     RECT  11.592 7.421 11.646 7.427 ;
     RECT  11.592 7.427 11.61 8.311 ;
     RECT  7.815 2.413 8.097 8.401 ;
     RECT  9 7.087 9.882 8.401 ;
     RECT  13.215 7.259 24.297 8.437 ;
     RECT  13.212 8.437 24.297 8.477 ;
     RECT  7.815 8.401 9.882 8.683 ;
     RECT  13.215 8.477 24.297 8.699 ;
     RECT  10.872 8.311 11.61 8.743 ;
     RECT  7.704 8.683 9.882 8.813 ;
     RECT  10.62 8.743 11.61 8.843 ;
     RECT  13.215 8.699 14.49 8.843 ;
     RECT  15.444 8.699 24.297 9.931 ;
     RECT  25.092 6.881 25.11 9.931 ;
     RECT  3.528 10.021 3.546 10.201 ;
     RECT  3.528 10.201 3.87 10.435 ;
     RECT  4.608 10.201 4.626 10.435 ;
     RECT  3.528 10.435 4.626 10.471 ;
     RECT  3.528 10.471 5.166 10.741 ;
     RECT  2.415 2.413 2.697 10.831 ;
     RECT  3.528 10.741 5.706 10.831 ;
     RECT  6.588 8.707 6.606 10.831 ;
     RECT  2.415 10.831 6.606 10.975 ;
     RECT  26.1 10.291 26.118 10.975 ;
     RECT  2.304 10.975 6.606 11.209 ;
     RECT  7.815 8.813 9.882 11.209 ;
     RECT  15.444 9.931 25.11 11.209 ;
     RECT  26.1 10.975 26.37 11.209 ;
     RECT  2.304 11.209 9.882 11.245 ;
     RECT  28.476 11.128 28.494 11.281 ;
     RECT  29.415 2.413 29.697 11.281 ;
     RECT  28.476 11.281 29.697 11.399 ;
     RECT  28.476 11.399 28.494 11.408 ;
     RECT  11.124 8.843 11.61 11.419 ;
     RECT  15.444 11.209 26.37 11.749 ;
     RECT  2.268 11.245 9.882 11.785 ;
     RECT  11.052 11.419 11.61 11.785 ;
     RECT  2.268 11.785 11.61 11.899 ;
     RECT  2.232 11.899 11.61 11.947 ;
     RECT  12.42 9.355 12.438 11.947 ;
     RECT  2.232 11.947 12.438 11.975 ;
     RECT  15.192 11.749 26.37 12.209 ;
     RECT  2.304 11.975 12.438 12.289 ;
     RECT  13.215 8.843 14.454 12.289 ;
     RECT  15.264 12.209 26.37 12.757 ;
     RECT  2.304 12.289 14.454 13.003 ;
     RECT  2.268 13.003 14.454 13.135 ;
     RECT  15.264 12.757 26.55 13.135 ;
     RECT  2.268 13.135 26.55 13.441 ;
     RECT  2.268 13.441 26.622 13.865 ;
     RECT  0.144 12.907 0.162 13.949 ;
     RECT  6.048 13.865 26.622 14.413 ;
     RECT  6.048 14.413 26.73 14.485 ;
     RECT  6.048 14.485 26.802 14.587 ;
     RECT  2.268 13.865 5.274 14.779 ;
     RECT  6.012 14.587 26.802 14.779 ;
     RECT  0.108 14.755 0.126 14.861 ;
     RECT  2.268 14.779 26.802 14.909 ;
     RECT  28.116 13.405 28.134 15.061 ;
     RECT  2.268 14.909 26.658 15.691 ;
     RECT  0.108 15.979 0.126 15.997 ;
     RECT  2.268 15.691 26.694 16.105 ;
     RECT  2.268 16.105 26.73 16.141 ;
     RECT  0.108 15.997 0.342 16.367 ;
     RECT  0.144 16.367 0.342 16.397 ;
     RECT  27.972 15.061 28.134 16.573 ;
     RECT  2.268 16.141 26.982 16.645 ;
     RECT  2.268 16.645 27.054 16.681 ;
     RECT  2.268 16.681 27.09 16.891 ;
     RECT  27.972 16.573 28.314 16.891 ;
     RECT  0.144 16.397 0.234 16.925 ;
     RECT  2.268 16.891 28.314 17.069 ;
     RECT  0.216 16.925 0.234 17.117 ;
     RECT  29.415 11.399 29.697 17.311 ;
     RECT  2.268 17.069 28.278 17.323 ;
     RECT  2.232 17.323 28.278 17.411 ;
     RECT  2.268 17.411 28.278 17.959 ;
     RECT  29.088 17.311 29.697 17.959 ;
     RECT  2.268 17.959 29.697 18.149 ;
     RECT  2.268 18.149 28.134 18.379 ;
     RECT  2.232 18.379 28.134 18.725 ;
     RECT  0.144 18.571 0.162 18.749 ;
     RECT  2.268 18.725 28.134 19.111 ;
     RECT  28.944 18.149 29.697 19.111 ;
     RECT  0.324 19.531 0.342 19.661 ;
     RECT  2.268 19.111 29.697 19.723 ;
     RECT  2.196 19.723 29.697 19.777 ;
     RECT  2.196 19.777 29.97 19.813 ;
     RECT  30.744 19.777 30.762 19.813 ;
     RECT  33.12 19.777 33.786 19.813 ;
     RECT  2.196 19.813 30.762 19.921 ;
     RECT  33.12 19.813 33.93 19.921 ;
     RECT  2.196 19.921 31.194 20.075 ;
     RECT  2.232 20.075 31.194 20.119 ;
     RECT  33.084 19.921 33.966 20.155 ;
     RECT  34.815 2.413 35.097 20.155 ;
     RECT  2.232 20.119 31.914 20.191 ;
     RECT  2.232 20.191 32.31 20.345 ;
     RECT  2.304 20.345 32.31 20.623 ;
     RECT  33.084 20.155 35.097 20.623 ;
     RECT  2.304 20.623 35.097 20.993 ;
     RECT  2.376 20.993 35.097 21.155 ;
     RECT  2.415 21.155 35.097 21.397 ;
     RECT  2.415 21.397 35.478 21.541 ;
     RECT  2.415 21.541 35.586 21.803 ;
     RECT  2.415 21.803 35.55 22.469 ;
     RECT  2.415 22.469 35.154 22.783 ;
     RECT  2.34 22.783 35.154 23.395 ;
     RECT  0.144 23.665 0.162 23.827 ;
     RECT  0.144 23.827 0.234 23.899 ;
     RECT  2.34 23.395 35.298 23.899 ;
     RECT  2.34 23.899 35.514 24.205 ;
     RECT  2.268 24.205 35.514 24.241 ;
     RECT  2.268 24.241 35.622 24.359 ;
     RECT  2.268 24.359 35.514 25.007 ;
     RECT  0.108 23.899 0.234 25.015 ;
     RECT  2.304 25.007 35.514 25.321 ;
     RECT  2.304 25.321 35.658 25.591 ;
     RECT  0.108 25.015 0.558 25.613 ;
     RECT  2.304 25.591 35.874 25.709 ;
     RECT  2.304 25.709 35.334 25.745 ;
     RECT  2.304 25.745 35.154 25.867 ;
     RECT  2.268 25.867 35.154 25.889 ;
     RECT  2.268 25.889 35.097 25.963 ;
     RECT  2.232 25.963 35.097 26.285 ;
     RECT  2.268 26.285 35.097 26.429 ;
     RECT  0.108 25.613 0.126 26.563 ;
     RECT  13.215 26.429 15.822 26.789 ;
     RECT  0.108 26.563 0.234 26.957 ;
     RECT  16.56 26.429 35.097 27.031 ;
     RECT  0.18 26.957 0.234 27.175 ;
     RECT  1.152 26.059 1.17 27.175 ;
     RECT  2.268 26.429 12.438 27.337 ;
     RECT  40.215 2.413 40.497 27.337 ;
     RECT  16.56 27.031 35.154 27.365 ;
     RECT  2.232 27.337 12.438 27.437 ;
     RECT  40.215 27.337 41.13 27.643 ;
     RECT  41.868 27.175 41.886 27.643 ;
     RECT  40.215 27.643 41.886 27.715 ;
     RECT  40.104 27.715 41.886 27.841 ;
     RECT  0.18 27.175 1.17 27.877 ;
     RECT  40.104 27.841 41.922 27.877 ;
     RECT  15.444 26.789 15.822 27.977 ;
     RECT  2.268 27.437 12.438 28.013 ;
     RECT  40.068 27.877 41.922 28.021 ;
     RECT  0.108 27.877 1.17 28.109 ;
     RECT  39.924 28.021 41.922 28.255 ;
     RECT  16.812 27.365 35.154 28.291 ;
     RECT  0.18 28.109 1.17 28.319 ;
     RECT  39.708 28.255 41.922 28.381 ;
     RECT  43.056 27.571 43.074 28.381 ;
     RECT  39.708 28.381 43.074 28.453 ;
     RECT  16.812 28.291 35.766 28.859 ;
     RECT  38.196 28.795 38.214 28.921 ;
     RECT  0.18 28.319 0.558 28.957 ;
     RECT  32.688 28.859 35.766 28.957 ;
     RECT  38.196 28.921 38.61 28.957 ;
     RECT  39.348 28.453 43.074 28.957 ;
     RECT  16.812 28.859 31.914 29.029 ;
     RECT  32.688 28.957 36.342 29.029 ;
     RECT  32.688 29.029 36.918 29.065 ;
     RECT  32.688 29.065 36.99 29.101 ;
     RECT  0.108 28.957 0.558 29.165 ;
     RECT  32.688 29.101 37.422 29.263 ;
     RECT  38.196 28.957 43.074 29.263 ;
     RECT  0.54 29.165 0.558 29.453 ;
     RECT  32.688 29.263 43.074 29.533 ;
     RECT  32.688 29.533 43.11 29.645 ;
     RECT  2.304 28.013 12.438 29.707 ;
     RECT  16.74 29.029 31.914 30.101 ;
     RECT  2.268 29.707 12.438 30.209 ;
     RECT  17.892 30.101 31.914 30.271 ;
     RECT  32.688 29.645 43.074 30.271 ;
     RECT  2.268 30.209 12.114 30.371 ;
     RECT  17.892 30.271 43.074 30.443 ;
     RECT  0.144 30.331 0.162 30.475 ;
     RECT  26.316 30.443 43.074 30.569 ;
     RECT  0.144 30.475 0.342 30.605 ;
     RECT  16.74 30.101 16.974 30.839 ;
     RECT  2.304 30.371 12.114 31.243 ;
     RECT  13.215 26.789 14.166 31.253 ;
     RECT  0.144 30.605 0.198 31.339 ;
     RECT  2.268 31.243 12.114 31.415 ;
     RECT  15.804 27.977 15.822 31.415 ;
     RECT  17.892 30.443 25.398 31.685 ;
     RECT  26.496 30.569 43.074 31.693 ;
     RECT  26.496 31.693 43.11 31.723 ;
     RECT  2.304 31.415 12.114 31.793 ;
     RECT  26.28 31.723 43.11 31.829 ;
     RECT  26.496 31.829 43.11 32.141 ;
     RECT  0.144 31.339 0.342 32.203 ;
     RECT  0.108 32.203 0.342 32.233 ;
     RECT  43.056 32.141 43.11 32.237 ;
     RECT  13.215 31.253 13.734 32.251 ;
     RECT  0.108 32.233 0.522 32.261 ;
     RECT  0.144 32.261 0.522 32.305 ;
     RECT  43.056 32.237 43.074 32.333 ;
     RECT  13.215 32.251 13.986 32.341 ;
     RECT  16.848 30.839 16.974 32.341 ;
     RECT  17.892 31.685 24.93 32.341 ;
     RECT  13.215 32.341 14.166 32.482 ;
     RECT  26.496 32.141 42.21 32.525 ;
     RECT  13.215 32.482 13.734 32.567 ;
     RECT  0.144 32.305 0.558 32.587 ;
     RECT  0.144 32.587 0.63 32.717 ;
     RECT  16.848 32.341 24.93 32.801 ;
     RECT  2.304 31.793 11.358 32.845 ;
     RECT  16.848 32.801 20.61 32.999 ;
     RECT  0.144 32.717 0.162 33.005 ;
     RECT  21.528 32.801 24.93 33.035 ;
     RECT  12.096 31.793 12.114 33.079 ;
     RECT  12.096 33.079 12.222 33.107 ;
     RECT  16.848 32.999 20.538 33.107 ;
     RECT  2.268 32.845 11.358 33.269 ;
     RECT  16.956 33.107 20.538 33.269 ;
     RECT  26.496 32.525 42.174 33.421 ;
     RECT  2.268 33.269 11.142 33.647 ;
     RECT  26.496 33.421 42.21 33.655 ;
     RECT  21.636 33.035 24.93 33.719 ;
     RECT  17.748 33.269 20.538 33.817 ;
     RECT  21.636 33.719 23.13 33.845 ;
     RECT  26.496 33.655 42.246 33.869 ;
     RECT  21.636 33.845 22.05 33.881 ;
     RECT  17.748 33.817 20.754 33.883 ;
     RECT  17.748 33.883 21.474 33.923 ;
     RECT  26.496 33.869 42.21 33.965 ;
     RECT  12.204 33.107 12.222 34.051 ;
     RECT  17.748 33.923 21.258 34.151 ;
     RECT  0.324 33.451 0.342 34.157 ;
     RECT  2.304 33.647 11.142 34.159 ;
     RECT  12.024 34.051 12.222 34.159 ;
     RECT  43.092 34.123 43.11 34.159 ;
     RECT  43.02 34.159 43.11 34.187 ;
     RECT  26.496 33.965 42.174 34.259 ;
     RECT  43.02 34.187 43.074 34.315 ;
     RECT  16.956 33.269 17.01 34.321 ;
     RECT  17.748 34.151 21.15 34.321 ;
     RECT  2.304 34.159 12.222 34.603 ;
     RECT  16.956 34.321 21.15 34.619 ;
     RECT  16.956 34.619 20.718 34.889 ;
     RECT  2.268 34.603 12.222 34.933 ;
     RECT  13.215 32.567 13.497 34.933 ;
     RECT  42.984 34.315 43.074 34.987 ;
     RECT  42.876 34.987 43.074 35.005 ;
     RECT  16.956 34.889 20.466 35.069 ;
     RECT  22.932 33.845 23.13 35.069 ;
     RECT  2.268 34.933 13.497 35.131 ;
     RECT  26.496 34.259 41.994 35.131 ;
     RECT  42.876 35.005 43.182 35.131 ;
     RECT  24.015 33.719 24.93 35.167 ;
     RECT  16.956 35.069 20.43 35.195 ;
     RECT  14.94 35.371 14.958 35.401 ;
     RECT  16.956 35.195 20.106 35.401 ;
     RECT  2.268 35.131 13.986 35.437 ;
     RECT  14.868 35.401 15.246 35.437 ;
     RECT  16.848 35.401 20.106 35.437 ;
     RECT  2.268 35.437 15.246 35.693 ;
     RECT  16.344 35.437 20.106 35.699 ;
     RECT  2.304 35.693 15.246 35.707 ;
     RECT  16.344 35.699 18.99 35.735 ;
     RECT  0.144 35.563 0.162 35.741 ;
     RECT  19.764 35.699 20.106 35.771 ;
     RECT  16.344 35.735 18.897 35.807 ;
     RECT  2.304 35.707 15.282 35.851 ;
     RECT  16.344 35.807 17.118 35.851 ;
     RECT  24.015 35.167 25.11 35.851 ;
     RECT  24.015 35.851 25.542 35.888 ;
     RECT  24.015 35.888 25.11 36.041 ;
     RECT  2.304 35.851 17.118 36.715 ;
     RECT  20.088 35.771 20.106 36.851 ;
     RECT  22.932 35.069 22.95 36.887 ;
     RECT  2.268 36.715 17.118 37.099 ;
     RECT  1.692 37.099 17.118 37.435 ;
     RECT  17.892 35.807 18.897 37.435 ;
     RECT  0.216 37.435 0.234 37.483 ;
     RECT  0.216 37.483 0.342 37.561 ;
     RECT  26.496 35.131 43.182 37.561 ;
     RECT  0.108 37.561 0.342 37.613 ;
     RECT  26.424 37.561 43.182 37.895 ;
     RECT  1.692 37.435 18.897 38.059 ;
     RECT  1.656 38.059 18.897 38.551 ;
     RECT  26.424 37.895 42.174 38.683 ;
     RECT  1.656 38.551 18.954 38.741 ;
     RECT  1.656 38.741 18.897 38.849 ;
     RECT  26.172 38.683 42.174 39.019 ;
     RECT  0.324 38.923 0.342 39.163 ;
     RECT  24.015 36.041 24.93 39.245 ;
     RECT  0.18 39.163 0.342 39.341 ;
     RECT  25.668 39.019 42.174 39.341 ;
     RECT  42.948 37.895 43.182 39.629 ;
     RECT  25.668 39.341 42.102 39.643 ;
     RECT  43.056 39.629 43.182 39.785 ;
     RECT  43.056 39.785 43.11 39.821 ;
     RECT  43.056 39.821 43.074 39.917 ;
     RECT  25.416 39.643 42.102 40.075 ;
     RECT  1.656 38.849 17.622 40.127 ;
     RECT  25.416 40.075 42.174 40.171 ;
     RECT  1.728 40.127 17.622 40.289 ;
     RECT  25.164 40.171 42.174 40.289 ;
     RECT  25.164 40.289 42.138 40.315 ;
     RECT  1.728 40.289 17.262 40.325 ;
     RECT  25.02 40.315 42.138 40.493 ;
     RECT  42.084 40.493 42.138 40.559 ;
     RECT  1.836 40.325 17.262 40.595 ;
     RECT  1.836 40.595 4.338 40.667 ;
     RECT  42.084 40.559 42.102 40.685 ;
     RECT  5.148 40.595 17.262 40.739 ;
     RECT  43.02 40.603 43.038 40.781 ;
     RECT  18.615 38.849 18.897 40.787 ;
     RECT  5.184 40.739 17.262 40.829 ;
     RECT  25.02 40.493 41.346 40.829 ;
     RECT  2.415 40.667 4.338 40.835 ;
     RECT  24.015 39.245 24.297 40.837 ;
     RECT  25.02 40.829 30.222 40.837 ;
     RECT  6.084 40.829 12.15 40.865 ;
     RECT  15.372 40.829 15.75 40.901 ;
     RECT  16.884 40.829 17.262 40.901 ;
     RECT  13.176 40.829 14.238 40.925 ;
     RECT  2.415 40.835 4.266 40.937 ;
     RECT  6.084 40.865 6.102 40.937 ;
     RECT  2.415 40.937 3.582 40.973 ;
     RECT  7.272 40.865 12.15 40.973 ;
     RECT  30.996 40.829 33.966 40.973 ;
     RECT  34.815 40.829 41.346 40.973 ;
     RECT  9.144 40.973 12.15 40.979 ;
     RECT  2.415 40.973 3.078 41.009 ;
     RECT  5.184 40.829 5.346 41.009 ;
     RECT  7.272 40.973 8.406 41.009 ;
     RECT  9.144 40.979 10.422 41.009 ;
     RECT  15.372 40.901 15.39 41.009 ;
     RECT  17.244 40.901 17.262 41.009 ;
     RECT  24.015 40.837 30.222 41.009 ;
     RECT  30.996 40.973 33.246 41.009 ;
     RECT  34.815 40.973 35.838 41.009 ;
     RECT  36.72 40.973 39.222 41.009 ;
     RECT  7.776 41.009 8.37 41.021 ;
     RECT  10.044 41.009 10.422 41.021 ;
     RECT  11.268 40.979 12.15 41.021 ;
     RECT  13.176 40.925 14.202 41.021 ;
     RECT  30.996 41.009 33.174 41.021 ;
     RECT  2.415 41.009 2.505 41.057 ;
     RECT  18.615 40.787 18.705 41.057 ;
     RECT  24.015 41.009 28.53 41.057 ;
     RECT  29.415 41.009 30.222 41.057 ;
     RECT  34.815 41.009 35.37 41.057 ;
     RECT  10.044 41.021 10.062 41.069 ;
     RECT  40.104 40.973 40.41 41.099 ;
     RECT  40.104 41.099 40.122 41.117 ;
     RECT  36.9 41.009 39.222 41.165 ;
     RECT  7.776 41.021 8.298 41.213 ;
     RECT  13.176 41.021 13.986 41.213 ;
     RECT  13.536 41.213 13.986 41.261 ;
     RECT  35.352 41.057 35.37 41.261 ;
     RECT  24.516 41.057 28.53 41.309 ;
     RECT  37.152 41.165 39.222 41.357 ;
     RECT  37.152 41.357 37.962 41.453 ;
     RECT  41.292 40.973 41.346 41.549 ;
     RECT  8.244 41.213 8.298 41.645 ;
     RECT  30.996 41.021 32.778 41.645 ;
     RECT  39.204 41.357 39.222 41.645 ;
     RECT  8.28 41.645 8.298 41.741 ;
     RECT  37.152 41.453 37.926 41.741 ;
     RECT  37.152 41.741 37.53 41.837 ;
     RECT  24.588 41.309 28.53 41.885 ;
     RECT  24.732 41.885 28.53 41.933 ;
     RECT  37.404 41.837 37.53 41.933 ;
     RECT  25.02 41.933 28.53 41.981 ;
     RECT  25.452 41.981 28.53 42.029 ;
     RECT  37.404 41.933 37.422 42.029 ;
     RECT  25.56 42.029 28.53 42.125 ;
     RECT  41.328 41.549 41.346 42.125 ;
     RECT  31.176 41.645 32.778 42.173 ;
     RECT  9.144 41.009 9.162 42.221 ;
     RECT  12.132 41.021 12.15 42.221 ;
     RECT  26.64 42.125 28.53 42.221 ;
     RECT  29.736 41.057 30.222 42.221 ;
     RECT  32.544 42.173 32.778 42.221 ;
     RECT  29.736 42.221 29.862 42.317 ;
     RECT  31.176 42.173 31.662 42.859 ;
     RECT  29.736 42.317 29.826 42.907 ;
     RECT  29.304 42.907 29.826 43.003 ;
     RECT  27.072 42.221 28.458 43.037 ;
     RECT  32.58 42.221 32.778 43.037 ;
     RECT  13.968 41.261 13.986 43.085 ;
     RECT  27.396 43.037 28.458 43.085 ;
     RECT  29.232 43.003 29.826 43.085 ;
     RECT  30.924 42.859 31.662 43.085 ;
     RECT  32.688 43.037 32.706 43.085 ;
     RECT  25.56 42.125 25.794 43.133 ;
     RECT  29.232 43.085 29.538 43.133 ;
     RECT  25.56 43.133 25.578 43.181 ;
     RECT  29.52 43.133 29.538 43.181 ;
    LAYER M4 ;
     RECT  0.06 24.048 0.133 39.336 ;
     RECT  0.133 24.048 0.137 39.528 ;
     RECT  0.137 24.144 0.173 39.528 ;
     RECT  0.06 10.992 2.408 20.136 ;
     RECT  0.133 22.032 2.408 22.056 ;
     RECT  0.173 24.24 2.408 39.528 ;
     RECT  2.408 2.148 2.512 41.052 ;
     RECT  2.512 2.418 2.704 40.782 ;
     RECT  2.704 10.464 3.449 40.632 ;
     RECT  3.449 35.904 3.985 40.632 ;
     RECT  3.449 10.464 4.561 34.776 ;
     RECT  3.985 35.904 4.561 40.824 ;
     RECT  4.561 10.464 4.597 40.824 ;
     RECT  4.597 10.224 5.357 40.824 ;
     RECT  5.357 10.224 5.363 40.632 ;
     RECT  5.363 10.56 5.699 40.632 ;
     RECT  5.699 10.752 5.717 40.632 ;
     RECT  5.717 10.848 6.661 40.632 ;
     RECT  5.653 8.688 7.693 8.712 ;
     RECT  6.661 10.848 7.765 40.584 ;
     RECT  7.693 8.688 7.808 8.808 ;
     RECT  7.765 10.848 7.808 41.208 ;
     RECT  7.808 2.148 7.912 41.208 ;
     RECT  7.912 2.418 8.104 41.208 ;
     RECT  8.104 40.56 8.233 41.208 ;
     RECT  8.233 40.56 8.243 41.64 ;
     RECT  8.243 40.944 8.269 41.64 ;
     RECT  8.101 43.008 8.291 43.032 ;
     RECT  8.104 14.112 8.489 39.432 ;
     RECT  8.489 14.112 8.531 39.288 ;
     RECT  8.269 40.944 9.107 41.736 ;
     RECT  8.104 10.848 9.173 12.552 ;
     RECT  9.133 42.192 9.217 42.216 ;
     RECT  8.531 14.112 9.313 39.096 ;
     RECT  9.313 13.728 9.317 39.096 ;
     RECT  9.173 11.952 9.389 12.552 ;
     RECT  9.317 16.272 9.389 39.096 ;
     RECT  8.104 7.392 9.397 8.808 ;
     RECT  9.389 12.528 9.421 12.552 ;
     RECT  9.317 13.728 9.421 15.24 ;
     RECT  8.104 6.24 9.493 6.264 ;
     RECT  9.397 7.392 9.493 9 ;
     RECT  9.421 12.528 9.497 15.24 ;
     RECT  9.497 12.528 9.505 13.992 ;
     RECT  9.389 16.272 9.539 26.376 ;
     RECT  9.389 27.456 9.541 39.096 ;
     RECT  9.541 27.456 9.565 39.912 ;
     RECT  9.107 40.944 9.565 41.064 ;
     RECT  9.565 27.456 9.569 41.064 ;
     RECT  9.539 16.272 9.587 25.848 ;
     RECT  9.569 27.504 9.635 41.064 ;
     RECT  9.635 27.648 9.713 41.064 ;
     RECT  9.713 27.648 9.785 32.04 ;
     RECT  9.785 27.648 9.821 30.36 ;
     RECT  9.785 31.728 9.857 32.04 ;
     RECT  9.587 16.272 9.893 25.608 ;
     RECT  9.821 27.648 9.893 29.352 ;
     RECT  9.821 30.336 9.893 30.36 ;
     RECT  9.889 1.824 9.925 1.848 ;
     RECT  9.781 0.096 9.971 0.12 ;
     RECT  9.893 27.648 9.971 28.392 ;
     RECT  9.925 4.176 9.997 4.2 ;
     RECT  9.713 33.168 10.073 41.064 ;
     RECT  9.997 3.408 10.141 4.2 ;
     RECT  9.925 1.728 10.163 1.848 ;
     RECT  9.857 32.016 10.217 32.04 ;
     RECT  10.163 1.728 10.297 1.752 ;
     RECT  10.073 33.168 10.649 41.016 ;
     RECT  9.497 15.072 10.681 15.24 ;
     RECT  9.893 16.272 10.681 25.56 ;
     RECT  9.505 13.632 10.789 13.992 ;
     RECT  10.681 15.072 10.789 25.56 ;
     RECT  10.649 34.08 10.835 41.016 ;
     RECT  9.505 12.528 10.861 12.552 ;
     RECT  10.789 13.632 10.861 25.56 ;
     RECT  10.835 34.08 10.973 39.384 ;
     RECT  10.141 3.408 10.979 4.872 ;
     RECT  10.861 12.528 10.979 25.56 ;
     RECT  10.933 33.072 11.017 33.096 ;
     RECT  9.173 10.848 11.041 10.872 ;
     RECT  11.029 11.952 11.041 12.216 ;
     RECT  10.979 13.344 11.045 25.56 ;
     RECT  9.493 6.24 11.117 9 ;
     RECT  10.979 3.936 11.123 4.872 ;
     RECT  11.041 10.848 11.125 12.216 ;
     RECT  10.973 34.32 11.189 39.384 ;
     RECT  11.123 3.936 11.297 4.2 ;
     RECT  11.189 34.32 11.405 34.344 ;
     RECT  11.045 13.344 11.549 23.688 ;
     RECT  11.125 10.848 11.555 10.872 ;
     RECT  11.125 12.192 11.596 12.216 ;
     RECT  11.549 18.384 11.657 23.688 ;
     RECT  11.189 35.328 11.795 39.384 ;
     RECT  11.795 35.856 11.833 39.384 ;
     RECT  10.835 40.464 11.833 41.016 ;
     RECT  11.297 3.936 11.873 3.96 ;
     RECT  11.833 35.856 11.987 41.016 ;
     RECT  11.045 25.296 12.157 25.56 ;
     RECT  11.549 13.344 12.197 17.256 ;
     RECT  12.197 13.344 12.233 17.112 ;
     RECT  11.657 23.04 12.301 23.688 ;
     RECT  11.117 6.672 12.337 9 ;
     RECT  12.301 23.04 12.337 23.928 ;
     RECT  12.157 25.152 12.337 25.56 ;
     RECT  12.121 42.192 12.563 42.216 ;
     RECT  11.657 18.384 12.764 21.96 ;
     RECT  12.337 23.04 12.764 25.56 ;
     RECT  12.764 18.384 12.767 25.56 ;
     RECT  11.987 35.856 12.985 40.728 ;
     RECT  12.985 35.52 13.165 40.728 ;
     RECT  12.337 6.24 13.208 9 ;
     RECT  12.233 14.112 13.208 17.112 ;
     RECT  12.767 18.384 13.208 25.608 ;
     RECT  9.971 27.648 13.208 27.672 ;
     RECT  13.165 35.52 13.208 41.208 ;
     RECT  12.613 42.816 13.285 43.032 ;
     RECT  13.208 2.148 13.312 41.208 ;
     RECT  13.312 2.418 13.429 41.208 ;
     RECT  13.429 2.418 13.504 41.256 ;
     RECT  13.504 35.52 13.565 41.256 ;
     RECT  13.565 35.52 13.601 41.016 ;
     RECT  13.285 42.816 13.619 43.08 ;
     RECT  13.504 14.112 13.637 16.536 ;
     RECT  13.619 43.056 13.997 43.08 ;
     RECT  13.504 21.408 14.069 26.328 ;
     RECT  13.601 36.24 14.213 41.016 ;
     RECT  14.213 36.24 14.249 40.92 ;
     RECT  14.249 36.24 14.537 40.584 ;
     RECT  14.069 21.408 14.641 24.216 ;
     RECT  13.637 14.352 14.677 16.536 ;
     RECT  13.504 17.52 14.677 19.656 ;
     RECT  14.677 14.352 14.681 19.656 ;
     RECT  14.537 36.24 14.785 40.488 ;
     RECT  14.641 21.168 14.893 24.216 ;
     RECT  14.785 35.808 14.924 40.488 ;
     RECT  14.681 14.352 14.933 19.608 ;
     RECT  13.504 32.256 15.011 32.472 ;
     RECT  14.924 35.376 15.011 40.488 ;
     RECT  13.504 6.096 15.068 9 ;
     RECT  15.011 35.424 15.107 40.488 ;
     RECT  15.068 6 15.109 9 ;
     RECT  15.109 5.088 15.155 9 ;
     RECT  15.107 35.424 15.221 35.832 ;
     RECT  15.221 35.424 15.257 35.448 ;
     RECT  14.933 14.736 15.437 19.608 ;
     RECT  15.155 6.672 15.445 9 ;
     RECT  15.289 12.048 15.469 12.072 ;
     RECT  15.425 10.272 15.509 10.296 ;
     RECT  15.445 6.672 15.541 9.048 ;
     RECT  15.145 13.152 15.613 13.176 ;
     RECT  15.613 13.056 15.731 13.176 ;
     RECT  14.069 25.296 15.757 26.328 ;
     RECT  15.469 11.856 15.829 12.072 ;
     RECT  15.731 13.056 15.829 13.08 ;
     RECT  14.893 20.976 15.877 24.216 ;
     RECT  15.757 25.2 15.877 26.328 ;
     RECT  15.829 11.856 15.937 13.08 ;
     RECT  15.107 37.056 15.971 40.488 ;
     RECT  15.685 0.144 15.973 0.168 ;
     RECT  15.155 5.088 15.985 5.688 ;
     RECT  13.504 3.6 16.013 3.624 ;
     RECT  15.985 5.088 16.013 5.112 ;
     RECT  15.973 0.144 16.037 0.6 ;
     RECT  15.437 15.312 16.121 19.608 ;
     RECT  15.937 11.76 16.157 13.08 ;
     RECT  16.121 18.096 16.157 19.608 ;
     RECT  16.157 12.528 16.193 13.08 ;
     RECT  15.971 37.056 16.229 39.912 ;
     RECT  16.037 0.096 16.403 0.6 ;
     RECT  15.877 20.976 16.513 26.328 ;
     RECT  16.157 18.24 16.541 19.608 ;
     RECT  16.513 20.88 16.541 26.328 ;
     RECT  16.403 0.096 16.691 0.552 ;
     RECT  16.193 12.528 16.733 12.552 ;
     RECT  16.691 0.096 16.883 0.12 ;
     RECT  16.153 1.728 16.909 1.752 ;
     RECT  16.229 37.92 16.913 39.672 ;
     RECT  16.121 15.312 16.981 17.112 ;
     RECT  16.729 4.512 17.017 4.536 ;
     RECT  15.541 6.672 17.017 9.096 ;
     RECT  17.017 6.48 17.053 9.096 ;
     RECT  13.504 27.648 17.197 27.672 ;
     RECT  16.541 18.24 17.201 26.328 ;
     RECT  17.053 6.384 17.233 9.096 ;
     RECT  16.909 1.728 17.305 1.8 ;
     RECT  16.441 2.832 17.305 2.856 ;
     RECT  17.201 18.768 17.345 26.328 ;
     RECT  17.345 25.632 17.363 26.328 ;
     RECT  17.017 4.128 17.413 4.536 ;
     RECT  17.233 6 17.413 9.096 ;
     RECT  16.981 14.976 17.413 17.112 ;
     RECT  17.345 18.768 17.459 24.504 ;
     RECT  17.413 14.064 17.5 17.112 ;
     RECT  17.305 1.728 17.521 2.856 ;
     RECT  17.413 4.128 17.521 9.096 ;
     RECT  17.5 15.504 17.557 17.112 ;
     RECT  17.363 25.68 17.605 26.328 ;
     RECT  17.197 27.648 17.605 27.864 ;
     RECT  17.521 1.728 17.653 9.096 ;
     RECT  17.5 14.064 17.665 14.232 ;
     RECT  17.665 13.584 17.845 14.232 ;
     RECT  15.011 32.256 18.061 32.28 ;
     RECT  17.621 11.424 18.097 11.448 ;
     RECT  17.773 34.896 18.169 34.92 ;
     RECT  18.097 10.848 18.205 11.448 ;
     RECT  18.205 10.848 18.385 11.784 ;
     RECT  18.169 34.176 18.457 34.92 ;
     RECT  18.061 32.256 18.469 33.096 ;
     RECT  18.457 34.176 18.469 35.496 ;
     RECT  17.845 12.768 18.565 14.232 ;
     RECT  17.557 29.328 18.601 29.352 ;
     RECT  17.653 1.728 18.608 9.288 ;
     RECT  18.385 10.272 18.608 11.784 ;
     RECT  18.565 12.768 18.608 14.424 ;
     RECT  17.557 15.504 18.608 17.64 ;
     RECT  17.459 18.768 18.608 20.088 ;
     RECT  17.459 21.12 18.608 24.504 ;
     RECT  17.605 25.68 18.608 27.864 ;
     RECT  18.601 29.328 18.608 30.12 ;
     RECT  18.469 32.256 18.608 35.496 ;
     RECT  16.913 37.92 18.608 38.76 ;
     RECT  18.608 1.728 18.712 41.052 ;
     RECT  18.712 1.728 18.904 40.782 ;
     RECT  18.904 1.728 18.929 31.272 ;
     RECT  18.929 1.776 19.109 31.272 ;
     RECT  19.109 20.976 19.187 31.272 ;
     RECT  19.109 10.176 19.253 19.992 ;
     RECT  19.109 1.776 19.325 9.048 ;
     RECT  18.904 32.256 19.379 34.92 ;
     RECT  19.187 28.416 19.541 31.272 ;
     RECT  19.325 2.256 19.577 9.048 ;
     RECT  19.379 32.256 19.649 34.728 ;
     RECT  19.253 10.608 19.685 19.992 ;
     RECT  19.649 33.648 19.865 34.728 ;
     RECT  19.685 11.376 19.937 19.992 ;
     RECT  19.541 28.416 19.955 29.688 ;
     RECT  19.865 33.648 19.973 33.864 ;
     RECT  19.973 33.744 20.009 33.864 ;
     RECT  19.033 0.576 20.041 0.6 ;
     RECT  19.937 12.768 20.189 19.992 ;
     RECT  20.189 13.056 20.233 19.992 ;
     RECT  20.233 13.248 20.257 19.992 ;
     RECT  19.187 20.976 20.257 26.856 ;
     RECT  19.937 11.376 20.261 11.736 ;
     RECT  20.257 13.248 20.333 26.856 ;
     RECT  19.541 30.816 20.369 31.272 ;
     RECT  20.041 0.576 20.389 1.176 ;
     RECT  19.577 2.256 20.389 8.808 ;
     RECT  20.389 0.576 20.485 8.808 ;
     RECT  20.261 11.376 20.513 11.496 ;
     RECT  20.009 33.84 20.549 33.864 ;
     RECT  20.369 31.248 20.581 31.272 ;
     RECT  19.649 32.256 20.581 32.28 ;
     RECT  20.485 0.528 20.585 8.808 ;
     RECT  20.333 13.248 20.627 26.52 ;
     RECT  20.581 31.248 20.627 32.28 ;
     RECT  20.585 4.128 20.636 8.808 ;
     RECT  20.585 0.528 20.665 2.952 ;
     RECT  20.636 4.128 20.723 9.048 ;
     RECT  20.545 28.128 20.765 28.152 ;
     RECT  20.665 0.528 20.797 2.856 ;
     RECT  20.797 0.432 20.873 2.856 ;
     RECT  20.873 0.432 20.965 2.52 ;
     RECT  20.627 13.248 21.017 21.672 ;
     RECT  20.965 0.096 21.107 2.52 ;
     RECT  21.107 1.68 21.125 2.52 ;
     RECT  20.513 11.376 21.349 11.4 ;
     RECT  21.125 1.68 21.446 2.232 ;
     RECT  20.723 4.128 21.449 8.52 ;
     RECT  20.627 22.8 21.481 26.52 ;
     RECT  21.017 13.248 21.539 20.664 ;
     RECT  21.539 13.248 21.589 18.744 ;
     RECT  21.446 1.728 21.593 2.232 ;
     RECT  21.449 4.128 21.629 6.936 ;
     RECT  21.017 21.648 21.637 21.672 ;
     RECT  21.481 22.8 21.637 26.616 ;
     RECT  21.589 12.48 21.701 18.744 ;
     RECT  21.701 14.832 21.779 18.744 ;
     RECT  20.627 31.248 21.841 32.088 ;
     RECT  21.349 11.136 21.917 11.4 ;
     RECT  21.637 21.648 21.923 26.616 ;
     RECT  21.917 11.136 21.949 11.16 ;
     RECT  21.923 21.648 21.964 22.824 ;
     RECT  21.107 0.096 22.117 0.36 ;
     RECT  19.955 29.232 22.165 29.688 ;
     RECT  21.841 31.248 22.165 32.52 ;
     RECT  21.949 10.32 22.213 11.16 ;
     RECT  21.449 8.496 22.259 8.52 ;
     RECT  22.093 27.888 22.345 27.912 ;
     RECT  21.779 14.832 22.349 17.928 ;
     RECT  22.165 29.232 22.489 32.52 ;
     RECT  21.445 33.888 22.489 33.912 ;
     RECT  22.117 0.096 22.501 0.504 ;
     RECT  22.213 9.696 22.561 11.16 ;
     RECT  22.489 29.232 22.595 33.912 ;
     RECT  21.593 2.208 22.597 2.232 ;
     RECT  21.629 4.128 22.597 6.888 ;
     RECT  22.595 29.232 22.601 32.52 ;
     RECT  22.561 9.12 22.645 11.16 ;
     RECT  21.923 23.856 22.645 26.616 ;
     RECT  22.345 27.888 22.645 28.248 ;
     RECT  22.645 23.856 22.673 28.248 ;
     RECT  21.539 19.776 22.705 20.664 ;
     RECT  21.964 21.648 22.705 22.296 ;
     RECT  21.701 12.48 22.777 13.704 ;
     RECT  22.597 1.728 22.813 2.232 ;
     RECT  22.597 3.312 22.813 6.888 ;
     RECT  22.349 14.832 22.817 14.856 ;
     RECT  22.501 0.096 22.885 0.552 ;
     RECT  22.777 12.288 22.961 13.704 ;
     RECT  22.705 19.776 22.993 22.296 ;
     RECT  22.961 12.48 22.997 13.704 ;
     RECT  22.813 1.728 23.029 6.888 ;
     RECT  22.673 23.856 23.093 27.336 ;
     RECT  22.349 16.032 23.125 17.928 ;
     RECT  22.997 12.768 23.173 13.704 ;
     RECT  22.601 29.232 23.209 31.752 ;
     RECT  22.993 19.776 23.317 22.344 ;
     RECT  23.093 23.376 23.317 27.336 ;
     RECT  22.885 0.096 23.465 0.6 ;
     RECT  23.465 0.096 23.609 0.552 ;
     RECT  23.317 19.776 23.677 27.336 ;
     RECT  23.209 28.512 23.677 31.752 ;
     RECT  23.125 16.032 23.845 18.792 ;
     RECT  23.677 19.776 23.845 31.752 ;
     RECT  23.029 1.728 24.008 6.984 ;
     RECT  22.645 9.696 24.008 11.16 ;
     RECT  23.173 12.768 24.008 14.232 ;
     RECT  23.845 16.032 24.008 31.752 ;
     RECT  22.595 33.888 24.008 33.912 ;
     RECT  18.904 37.968 24.008 38.76 ;
     RECT  24.008 1.728 24.077 41.052 ;
     RECT  24.077 2.064 24.304 41.052 ;
     RECT  24.304 18.72 24.419 19.8 ;
     RECT  24.304 22.032 24.419 24.648 ;
     RECT  24.304 13.392 24.473 13.656 ;
     RECT  24.304 40.32 24.505 41.052 ;
     RECT  24.304 20.976 24.545 21 ;
     RECT  24.505 40.32 24.577 41.304 ;
     RECT  24.473 13.392 24.581 13.608 ;
     RECT  24.304 15.984 24.689 17.64 ;
     RECT  24.577 40.32 24.721 41.88 ;
     RECT  24.419 22.032 24.755 24.504 ;
     RECT  24.755 22.032 24.761 23.448 ;
     RECT  24.689 16.896 24.797 17.64 ;
     RECT  24.581 13.392 24.947 13.416 ;
     RECT  24.304 10.944 24.988 11.4 ;
     RECT  24.721 40.32 25.009 41.928 ;
     RECT  24.761 22.464 25.013 23.448 ;
     RECT  24.755 24.432 25.013 24.504 ;
     RECT  24.304 25.824 25.013 27.192 ;
     RECT  24.304 28.272 25.049 31.752 ;
     RECT  25.013 24.432 25.085 24.456 ;
     RECT  25.013 22.8 25.121 23.448 ;
     RECT  25.049 28.272 25.121 30.408 ;
     RECT  25.121 29.856 25.193 30.408 ;
     RECT  25.013 26.064 25.265 27.192 ;
     RECT  24.419 19.536 25.388 19.8 ;
     RECT  25.388 18.24 25.405 19.8 ;
     RECT  24.304 37.968 25.405 39.24 ;
     RECT  25.009 40.32 25.405 41.976 ;
     RECT  25.405 37.968 25.441 41.976 ;
     RECT  25.405 18.24 25.475 20.952 ;
     RECT  25.121 22.848 25.475 23.448 ;
     RECT  24.304 2.064 25.697 4.776 ;
     RECT  25.475 18.24 25.697 18.264 ;
     RECT  25.475 19.248 25.715 20.952 ;
     RECT  24.797 16.896 25.765 17.064 ;
     RECT  25.549 43.152 25.765 43.176 ;
     RECT  25.715 19.248 25.949 20.184 ;
     RECT  25.441 37.968 26.017 42.024 ;
     RECT  25.475 23.424 26.053 23.448 ;
     RECT  26.053 14.832 26.089 14.856 ;
     RECT  25.697 2.544 26.129 4.776 ;
     RECT  26.089 14.448 26.161 14.856 ;
     RECT  26.129 2.544 26.165 3.672 ;
     RECT  26.129 4.752 26.165 4.776 ;
     RECT  26.161 14.352 26.197 14.856 ;
     RECT  26.017 37.968 26.233 42.072 ;
     RECT  26.165 2.592 26.237 3.672 ;
     RECT  25.949 20.016 26.273 20.184 ;
     RECT  23.609 0.096 26.309 0.504 ;
     RECT  26.237 2.784 26.309 3.672 ;
     RECT  26.197 14.352 26.309 14.952 ;
     RECT  25.049 31.728 26.309 31.752 ;
     RECT  26.309 3.648 26.381 3.672 ;
     RECT  26.309 14.352 26.489 14.472 ;
     RECT  25.513 35.856 26.588 35.88 ;
     RECT  26.309 0.144 26.597 0.504 ;
     RECT  26.233 37.968 26.629 42.12 ;
     RECT  25.765 43.104 26.629 43.176 ;
     RECT  26.588 35.664 26.675 35.88 ;
     RECT  26.053 23.424 26.701 23.592 ;
     RECT  25.193 30.384 26.737 30.408 ;
     RECT  26.489 14.448 26.741 14.472 ;
     RECT  26.161 21.168 26.809 21.768 ;
     RECT  25.765 16.896 26.867 17.208 ;
     RECT  26.675 35.856 26.869 35.88 ;
     RECT  25.265 26.256 26.881 27.192 ;
     RECT  26.701 23.424 26.885 24.504 ;
     RECT  26.737 30.288 26.885 30.408 ;
     RECT  26.828 31.824 26.915 31.848 ;
     RECT  26.869 35.856 26.915 36.12 ;
     RECT  26.809 21.072 26.921 21.768 ;
     RECT  26.821 18.192 27.011 18.216 ;
     RECT  26.597 0.48 27.029 0.504 ;
     RECT  26.921 21.072 27.137 21.672 ;
     RECT  26.881 25.632 27.203 27.192 ;
     RECT  26.629 37.584 27.313 43.176 ;
     RECT  26.885 23.424 27.529 23.736 ;
     RECT  26.867 16.896 27.785 16.92 ;
     RECT  27.137 21.072 27.785 21.096 ;
     RECT  28.172 21.264 28.213 21.288 ;
     RECT  27.529 22.992 28.213 23.736 ;
     RECT  27.203 25.632 28.213 26.28 ;
     RECT  28.213 21.264 28.393 23.736 ;
     RECT  28.213 25.008 28.393 26.28 ;
     RECT  24.304 33.888 28.453 33.912 ;
     RECT  26.273 20.016 28.789 20.04 ;
     RECT  27.313 37.44 28.897 43.176 ;
     RECT  28.393 31.536 29.005 31.56 ;
     RECT  28.393 21.264 29.077 26.28 ;
     RECT  26.885 30.384 29.077 30.408 ;
     RECT  29.005 31.536 29.077 31.704 ;
     RECT  26.915 36.096 29.113 36.12 ;
     RECT  28.897 37.344 29.113 43.176 ;
     RECT  28.789 20.016 29.269 20.088 ;
     RECT  29.077 30.384 29.269 31.704 ;
     RECT  24.988 11.136 29.408 11.4 ;
     RECT  29.269 19.824 29.408 20.088 ;
     RECT  29.077 21.12 29.408 26.28 ;
     RECT  29.269 30.384 29.408 32.04 ;
     RECT  28.453 33.024 29.408 33.912 ;
     RECT  29.185 34.896 29.408 34.92 ;
     RECT  29.113 36.096 29.408 43.176 ;
     RECT  29.408 2.148 29.512 43.176 ;
     RECT  29.512 2.418 29.549 43.176 ;
     RECT  29.549 2.418 29.704 43.08 ;
     RECT  29.704 23.328 29.837 24.984 ;
     RECT  29.704 33.936 29.843 43.08 ;
     RECT  29.837 23.328 29.881 24.6 ;
     RECT  29.843 34.128 29.881 43.08 ;
     RECT  29.704 19.824 29.981 20.088 ;
     RECT  29.704 27.36 29.981 27.384 ;
     RECT  29.881 23.328 30.017 24.072 ;
     RECT  29.704 21.072 30.341 21.096 ;
     RECT  29.704 26.256 30.755 26.28 ;
     RECT  29.881 34.128 30.853 42.792 ;
     RECT  30.853 34.128 30.898 42.984 ;
     RECT  29.981 20.064 31.021 20.088 ;
     RECT  31.021 20.064 31.061 20.52 ;
     RECT  30.017 23.376 31.061 24.072 ;
     RECT  30.898 34.128 31.091 43.08 ;
     RECT  31.273 28.944 31.309 28.968 ;
     RECT  31.091 34.128 31.309 41.016 ;
     RECT  31.309 33.648 31.457 41.016 ;
     RECT  31.309 28.608 31.525 28.968 ;
     RECT  29.704 30.384 31.525 32.04 ;
     RECT  31.525 28.032 31.637 28.968 ;
     RECT  31.457 36.24 31.709 41.016 ;
     RECT  31.061 23.568 31.717 24.072 ;
     RECT  30.805 25.344 31.717 25.464 ;
     RECT  31.457 33.648 31.745 35.064 ;
     RECT  31.717 23.568 31.763 25.464 ;
     RECT  31.525 30.384 31.763 32.184 ;
     RECT  31.745 34.8 31.811 35.064 ;
     RECT  31.811 34.944 31.817 35.064 ;
     RECT  31.817 34.944 31.853 34.968 ;
     RECT  31.777 21.936 31.961 21.96 ;
     RECT  31.763 24 32.033 25.464 ;
     RECT  31.637 28.032 32.065 28.2 ;
     RECT  31.091 42.096 32.101 43.08 ;
     RECT  32.065 27.84 32.137 28.2 ;
     RECT  32.101 42 32.213 43.08 ;
     RECT  31.763 30.912 32.281 32.184 ;
     RECT  31.745 33.648 32.281 33.816 ;
     RECT  32.213 42.096 32.393 43.08 ;
     RECT  32.033 25.008 32.425 25.464 ;
     RECT  32.137 27.6 32.497 28.2 ;
     RECT  32.393 42.144 32.501 43.08 ;
     RECT  32.497 27.408 32.677 28.2 ;
     RECT  32.677 27.408 32.681 28.872 ;
     RECT  32.501 42.192 32.717 43.08 ;
     RECT  32.717 42.192 32.723 43.032 ;
     RECT  32.425 25.008 32.749 25.56 ;
     RECT  32.281 30.912 32.821 33.816 ;
     RECT  32.723 43.008 32.833 43.032 ;
     RECT  32.033 24 32.929 24.024 ;
     RECT  32.681 27.6 33.005 28.872 ;
     RECT  31.709 40.992 33.048 41.016 ;
     RECT  32.749 25.008 33.059 25.704 ;
     RECT  32.821 30.72 33.109 33.816 ;
     RECT  33.059 25.008 33.149 25.56 ;
     RECT  33.048 40.944 33.203 41.016 ;
     RECT  33.109 30.72 33.325 33.912 ;
     RECT  31.709 36.24 33.325 39.912 ;
     RECT  31.061 20.496 33.356 20.52 ;
     RECT  32.929 23.664 33.365 24.024 ;
     RECT  33.356 20.208 33.397 20.52 ;
     RECT  33.005 27.936 33.437 28.872 ;
     RECT  33.397 20.208 33.443 21.144 ;
     RECT  33.325 30.72 33.469 34.728 ;
     RECT  33.469 30.624 33.505 34.728 ;
     RECT  33.325 36.096 33.505 39.912 ;
     RECT  33.443 21.12 33.577 21.144 ;
     RECT  33.505 30.624 33.685 39.912 ;
     RECT  33.437 27.936 33.725 28.056 ;
     RECT  33.149 25.536 33.761 25.56 ;
     RECT  33.685 30.576 33.937 39.912 ;
     RECT  33.577 29.424 34.153 29.496 ;
     RECT  33.937 30.576 34.153 40.488 ;
     RECT  33.365 23.904 34.297 24.024 ;
     RECT  33.577 21.12 34.808 21.672 ;
     RECT  34.213 22.752 34.808 22.776 ;
     RECT  34.297 23.904 34.808 24.504 ;
     RECT  34.556 25.728 34.808 25.752 ;
     RECT  33.725 28.032 34.808 28.056 ;
     RECT  34.153 29.424 34.808 40.488 ;
     RECT  34.808 2.148 34.912 41.052 ;
     RECT  34.912 2.418 35.104 41.052 ;
     RECT  35.104 23.904 35.165 23.928 ;
     RECT  35.104 29.04 35.341 41.052 ;
     RECT  35.341 29.04 35.507 41.256 ;
     RECT  35.507 29.616 36.713 41.256 ;
     RECT  36.713 29.616 36.785 31.8 ;
     RECT  36.713 32.784 37.141 41.256 ;
     RECT  37.141 32.784 37.393 41.832 ;
     RECT  36.785 29.664 37.825 31.8 ;
     RECT  37.393 32.784 37.825 42.024 ;
     RECT  37.825 29.664 39.013 42.024 ;
     RECT  39.013 29.52 39.985 42.024 ;
     RECT  39.985 29.232 40.208 42.024 ;
     RECT  40.208 2.148 40.312 42.024 ;
     RECT  40.312 2.418 40.504 42.024 ;
     RECT  40.504 29.136 41.317 42.024 ;
     RECT  41.317 29.136 43.164 42.12 ;
    LAYER M5 ;
     RECT  9.936 0.016 10.248 0.131 ;
     RECT  16.08 0.016 22.92 0.131 ;
     RECT  16.176 0.131 22.92 0.325 ;
     RECT  16.176 0.325 23.064 0.373 ;
     RECT  10.032 0.131 10.248 1.763 ;
     RECT  16.176 0.373 23.64 1.763 ;
     RECT  16.176 1.763 22.056 1.811 ;
     RECT  10.128 1.763 10.152 1.859 ;
     RECT  23.04 1.763 23.64 2.137 ;
     RECT  2.4 2.137 2.52 2.151 ;
     RECT  7.8 2.137 7.92 2.151 ;
     RECT  13.2 2.137 13.32 2.151 ;
     RECT  23.04 2.137 24.12 2.151 ;
     RECT  29.4 2.137 29.52 2.151 ;
     RECT  34.8 2.137 34.92 2.151 ;
     RECT  40.2 2.137 40.32 2.151 ;
     RECT  17.424 1.811 18.912 2.291 ;
     RECT  23.04 2.151 24.312 2.485 ;
     RECT  17.712 2.291 18.912 2.867 ;
     RECT  19.92 1.811 22.056 2.867 ;
     RECT  20.592 2.867 22.056 2.963 ;
     RECT  20.688 2.963 22.056 3.301 ;
     RECT  23.04 2.485 24.648 3.301 ;
     RECT  18.192 2.867 18.912 3.443 ;
     RECT  18.288 3.443 18.912 3.925 ;
     RECT  20.688 3.301 24.648 4.117 ;
     RECT  9.936 4.165 9.96 4.213 ;
     RECT  10.944 3.397 10.968 4.213 ;
     RECT  9.936 4.213 10.968 4.837 ;
     RECT  18.288 3.925 19.08 5.171 ;
     RECT  18.288 5.171 19.032 5.219 ;
     RECT  15.12 5.077 15.144 5.653 ;
     RECT  16.176 1.811 16.2 5.653 ;
     RECT  18.48 5.219 19.032 5.747 ;
     RECT  15.12 5.653 16.2 6.035 ;
     RECT  7.8 2.151 8.112 6.229 ;
     RECT  7.8 6.229 8.856 6.661 ;
     RECT  9.936 4.837 11.112 6.661 ;
     RECT  18.48 5.747 18.912 6.707 ;
     RECT  20.688 4.117 24.84 6.899 ;
     RECT  22.608 6.899 24.84 6.995 ;
     RECT  13.2 2.151 13.512 7.189 ;
     RECT  20.688 6.899 21.384 7.619 ;
     RECT  15.936 6.035 16.2 7.717 ;
     RECT  18.6 6.707 18.912 7.861 ;
     RECT  14.784 7.237 14.808 7.909 ;
     RECT  15.936 7.717 16.296 7.909 ;
     RECT  18.6 7.861 19.176 7.909 ;
     RECT  14.784 7.909 16.296 8.195 ;
     RECT  15.456 8.195 16.296 8.435 ;
     RECT  13.2 7.189 13.656 8.483 ;
     RECT  21.36 7.619 21.384 8.485 ;
     RECT  22.608 6.995 23.016 8.485 ;
     RECT  17.808 7.909 19.176 8.533 ;
     RECT  21.36 8.485 23.016 9.013 ;
     RECT  20.688 9.013 23.016 9.731 ;
     RECT  5.664 8.677 5.688 10.213 ;
     RECT  15.456 8.435 16.2 10.307 ;
     RECT  2.4 2.151 2.712 10.453 ;
     RECT  7.8 6.661 11.112 10.837 ;
     RECT  2.4 10.453 3.432 10.883 ;
     RECT  24 6.995 24.84 10.933 ;
     RECT  5.328 10.213 5.688 11.029 ;
     RECT  4.416 11.029 5.688 11.317 ;
     RECT  29.4 2.151 29.712 11.317 ;
     RECT  17.664 8.533 19.176 11.365 ;
     RECT  20.688 9.731 21.384 11.365 ;
     RECT  17.664 11.365 21.384 11.459 ;
     RECT  4.368 11.317 5.688 11.797 ;
     RECT  0.528 11.893 0.552 12.179 ;
     RECT  7.8 10.837 11.544 12.227 ;
     RECT  4.368 11.797 6.552 12.469 ;
     RECT  7.8 12.227 11.064 12.469 ;
     RECT  18.6 11.459 21.384 12.757 ;
     RECT  2.4 10.883 3.288 12.901 ;
     RECT  2.4 12.901 3.384 12.997 ;
     RECT  4.368 12.469 11.064 12.997 ;
     RECT  16.176 10.307 16.2 13.045 ;
     RECT  18.192 12.757 21.384 13.283 ;
     RECT  18.192 13.283 20.904 13.715 ;
     RECT  22.608 9.731 23.016 13.715 ;
     RECT  0.144 12.709 0.168 13.859 ;
     RECT  2.4 12.997 11.064 14.291 ;
     RECT  3.84 14.291 11.064 14.725 ;
     RECT  13.2 8.483 13.512 14.725 ;
     RECT  13.056 14.725 13.512 14.773 ;
     RECT  18.6 13.715 20.904 14.773 ;
     RECT  12.96 14.773 13.512 15.253 ;
     RECT  3.84 14.725 11.832 15.395 ;
     RECT  12.96 15.253 14.136 15.445 ;
     RECT  3.84 15.395 11.064 15.491 ;
     RECT  15.696 13.045 16.2 15.541 ;
     RECT  3.888 15.491 11.064 15.587 ;
     RECT  12.24 15.445 14.136 15.829 ;
     RECT  15.648 15.541 16.2 15.829 ;
     RECT  0.336 15.781 0.36 15.925 ;
     RECT  12.24 15.829 16.2 15.971 ;
     RECT  0.24 15.925 0.36 16.019 ;
     RECT  4.608 15.587 11.064 16.019 ;
     RECT  17.424 14.965 17.448 16.019 ;
     RECT  18.6 14.773 21.624 16.069 ;
     RECT  2.4 14.291 2.712 16.261 ;
     RECT  0.24 16.019 0.264 16.357 ;
     RECT  12.24 15.971 13.608 16.357 ;
     RECT  2.4 16.261 2.856 16.501 ;
     RECT  18.48 16.069 21.624 16.501 ;
     RECT  0.192 16.357 0.264 16.547 ;
     RECT  12.048 16.357 13.608 16.547 ;
     RECT  18.48 16.501 21.864 16.885 ;
     RECT  17.616 16.885 21.864 16.933 ;
     RECT  22.992 13.715 23.016 16.933 ;
     RECT  0.24 16.547 0.264 16.979 ;
     RECT  17.616 16.933 23.016 16.979 ;
     RECT  4.992 16.019 11.064 16.981 ;
     RECT  2.4 16.501 3.432 17.029 ;
     RECT  4.512 16.981 11.064 17.029 ;
     RECT  24 10.933 24.936 17.029 ;
     RECT  15.36 15.971 16.2 17.075 ;
     RECT  24 17.029 25.656 17.075 ;
     RECT  12.048 16.547 13.512 17.509 ;
     RECT  14.688 17.077 14.712 17.509 ;
     RECT  22.752 16.979 23.016 17.939 ;
     RECT  26.832 17.077 26.856 18.181 ;
     RECT  26.832 18.181 27 18.227 ;
     RECT  12.048 17.509 14.712 18.229 ;
     RECT  25.632 17.075 25.656 18.275 ;
     RECT  17.616 16.979 21.624 18.709 ;
     RECT  12.048 18.229 14.856 18.755 ;
     RECT  16.176 17.075 16.2 18.757 ;
     RECT  22.992 17.939 23.016 18.757 ;
     RECT  24 17.075 24.456 18.757 ;
     RECT  12.048 18.755 14.232 18.851 ;
     RECT  16.176 18.757 16.584 19.093 ;
     RECT  17.616 18.709 21.768 19.093 ;
     RECT  25.44 18.565 25.464 19.621 ;
     RECT  0.144 19.621 0.168 19.811 ;
     RECT  16.176 19.093 21.768 19.813 ;
     RECT  22.992 18.757 24.456 19.813 ;
     RECT  2.4 17.029 11.064 19.861 ;
     RECT  12.048 18.851 13.608 19.861 ;
     RECT  26.976 18.227 27 20.051 ;
     RECT  28.8 11.317 29.712 20.099 ;
     RECT  16.176 19.813 24.456 20.627 ;
     RECT  25.44 19.621 25.704 20.963 ;
     RECT  2.4 19.861 13.608 21.155 ;
     RECT  33.408 20.197 33.432 21.155 ;
     RECT  2.4 21.155 3.144 21.203 ;
     RECT  4.416 21.155 13.608 21.203 ;
     RECT  29.28 20.099 29.712 21.203 ;
     RECT  12.768 21.203 13.608 21.251 ;
     RECT  2.4 21.203 2.808 21.299 ;
     RECT  4.416 21.203 11.448 21.299 ;
     RECT  12.816 21.251 13.608 21.443 ;
     RECT  16.176 20.627 21.912 21.683 ;
     RECT  16.176 21.683 17.544 21.971 ;
     RECT  16.608 21.971 17.544 22.067 ;
     RECT  4.416 21.299 11.064 22.165 ;
     RECT  3.696 22.165 11.064 22.259 ;
     RECT  28.224 21.253 28.248 22.259 ;
     RECT  16.8 22.067 17.544 22.499 ;
     RECT  2.4 21.299 2.712 22.645 ;
     RECT  3.696 22.259 10.968 22.645 ;
     RECT  17.136 22.499 17.544 22.741 ;
     RECT  18.6 21.683 21.912 22.741 ;
     RECT  34.8 2.151 35.112 22.741 ;
     RECT  22.992 20.627 24.456 22.837 ;
     RECT  25.44 20.963 25.464 22.837 ;
     RECT  22.992 22.837 25.464 22.883 ;
     RECT  12.816 21.443 13.512 23.029 ;
     RECT  17.136 22.741 21.912 23.075 ;
     RECT  22.992 22.883 24.744 23.411 ;
     RECT  24 23.411 24.744 23.891 ;
     RECT  17.328 23.075 21.912 23.939 ;
     RECT  34.224 22.741 35.112 23.939 ;
     RECT  29.4 21.203 29.712 24.037 ;
     RECT  22.992 23.411 23.016 24.179 ;
     RECT  12.768 23.029 13.512 24.181 ;
     RECT  12.768 24.181 13.992 24.371 ;
     RECT  29.4 24.037 29.832 24.469 ;
     RECT  17.328 23.939 21.672 24.563 ;
     RECT  31.728 23.557 31.752 24.563 ;
     RECT  28.656 24.469 29.832 24.611 ;
     RECT  24 23.891 24.408 24.659 ;
     RECT  17.328 24.563 21.48 24.707 ;
     RECT  24 24.659 24.312 24.709 ;
     RECT  28.656 24.611 29.712 24.995 ;
     RECT  15.36 24.037 15.384 25.045 ;
     RECT  0.144 22.021 0.168 25.141 ;
     RECT  12.816 24.371 13.992 25.619 ;
     RECT  13.2 25.619 13.992 25.715 ;
     RECT  33.024 24.997 33.048 25.715 ;
     RECT  0.144 25.141 0.264 25.763 ;
     RECT  17.328 24.707 21.384 25.957 ;
     RECT  22.656 25.621 22.68 25.957 ;
     RECT  15.36 25.045 15.912 26.003 ;
     RECT  15.36 26.003 15.384 26.051 ;
     RECT  17.328 25.957 22.68 26.147 ;
     RECT  13.2 25.715 13.8 26.339 ;
     RECT  0.192 25.763 0.264 26.483 ;
     RECT  0.192 26.483 0.216 26.675 ;
     RECT  27.168 23.701 27.192 27.157 ;
     RECT  22.656 26.147 22.68 27.203 ;
     RECT  26.88 27.157 27.192 27.203 ;
     RECT  0.144 26.725 0.168 27.635 ;
     RECT  23.664 24.709 24.312 28.981 ;
     RECT  34.608 23.939 35.112 29.029 ;
     RECT  17.328 26.147 21.384 29.267 ;
     RECT  23.664 28.981 24.648 29.315 ;
     RECT  17.328 29.267 19.32 29.363 ;
     RECT  24 29.315 24.648 29.603 ;
     RECT  20.592 29.267 21.384 29.699 ;
     RECT  34.608 29.029 35.496 30.181 ;
     RECT  40.2 2.151 40.512 30.613 ;
     RECT  34.176 30.181 35.496 30.851 ;
     RECT  24 29.603 24.552 30.899 ;
     RECT  43.008 30.853 43.032 31.043 ;
     RECT  29.4 24.995 29.712 31.285 ;
     RECT  0.144 30.181 0.168 31.429 ;
     RECT  29.28 31.285 29.712 31.525 ;
     RECT  0.144 31.429 0.216 32.291 ;
     RECT  20.592 29.699 20.616 32.291 ;
     RECT  0.288 32.293 0.312 32.435 ;
     RECT  22.176 30.181 22.2 32.531 ;
     RECT  18.6 29.363 19.32 33.013 ;
     RECT  2.4 22.645 10.968 33.107 ;
     RECT  18.6 33.013 19.512 33.541 ;
     RECT  2.4 33.107 10.248 33.683 ;
     RECT  18.48 33.541 19.512 33.875 ;
     RECT  26.88 27.203 26.904 33.877 ;
     RECT  22.56 33.013 22.584 33.923 ;
     RECT  28.464 31.525 29.712 33.923 ;
     RECT  29.4 33.923 29.712 33.925 ;
     RECT  30.72 26.245 30.744 33.925 ;
     RECT  18.48 33.875 19.368 34.211 ;
     RECT  9.648 33.683 10.248 34.213 ;
     RECT  34.8 30.851 35.496 34.357 ;
     RECT  2.4 33.683 8.232 34.789 ;
     RECT  9.648 34.213 10.44 34.789 ;
     RECT  31.728 30.373 31.752 34.789 ;
     RECT  18.6 34.211 19.368 34.931 ;
     RECT  29.4 33.925 30.744 34.933 ;
     RECT  31.728 34.789 31.8 34.933 ;
     RECT  29.4 34.933 31.8 34.979 ;
     RECT  14.976 32.437 15 35.413 ;
     RECT  0.144 33.397 0.168 35.459 ;
     RECT  34.608 34.357 35.496 35.461 ;
     RECT  26.64 33.877 26.904 35.699 ;
     RECT  2.4 34.789 10.44 35.939 ;
     RECT  11.76 35.317 11.784 35.939 ;
     RECT  34.224 35.461 35.496 35.939 ;
     RECT  40.2 30.613 40.632 35.939 ;
     RECT  2.4 35.939 9.576 36.035 ;
     RECT  26.88 35.699 26.904 36.131 ;
     RECT  2.4 36.035 8.568 36.179 ;
     RECT  29.4 34.979 31.752 36.229 ;
     RECT  14.976 35.413 15.096 36.275 ;
     RECT  13.2 26.339 13.512 36.373 ;
     RECT  2.4 36.179 4.344 36.515 ;
     RECT  2.4 36.515 2.808 36.563 ;
     RECT  38.304 36.709 38.328 36.757 ;
     RECT  38.304 36.757 38.76 36.851 ;
     RECT  29.4 36.229 32.424 36.853 ;
     RECT  38.736 36.851 38.76 36.947 ;
     RECT  15.072 36.275 15.096 37.043 ;
     RECT  5.52 36.179 8.568 37.091 ;
     RECT  12.528 36.373 13.512 37.285 ;
     RECT  3.84 36.515 4.2 37.477 ;
     RECT  5.52 37.091 8.112 37.477 ;
     RECT  29.28 36.853 32.424 37.571 ;
     RECT  3.84 37.477 8.112 37.573 ;
     RECT  9.552 36.035 9.576 37.907 ;
     RECT  17.328 29.363 17.352 38.003 ;
     RECT  40.2 35.939 40.512 38.053 ;
     RECT  2.4 36.563 2.712 38.101 ;
     RECT  3.792 37.573 8.112 38.101 ;
     RECT  10.704 37.861 10.728 38.101 ;
     RECT  40.2 38.053 40.632 38.195 ;
     RECT  2.4 38.101 8.112 38.437 ;
     RECT  9.264 38.389 9.384 38.437 ;
     RECT  10.704 38.101 11.4 38.437 ;
     RECT  12.528 37.285 13.656 38.437 ;
     RECT  10.704 38.437 13.656 38.533 ;
     RECT  10.608 38.533 13.656 38.677 ;
     RECT  34.8 35.939 35.496 38.819 ;
     RECT  15.888 38.629 15.912 39.205 ;
     RECT  10.608 38.677 13.752 39.253 ;
     RECT  15.888 39.205 15.96 39.395 ;
     RECT  29.28 37.571 31.752 39.395 ;
     RECT  0.144 36.517 0.168 39.539 ;
     RECT  2.4 38.437 9.384 39.589 ;
     RECT  10.608 39.253 14.232 39.589 ;
     RECT  40.2 38.195 40.512 39.589 ;
     RECT  40.2 39.589 40.632 39.731 ;
     RECT  2.4 39.589 14.232 39.923 ;
     RECT  30.96 39.395 31.752 39.923 ;
     RECT  2.4 39.923 14.184 40.499 ;
     RECT  15.936 39.395 15.96 40.499 ;
     RECT  4.896 40.499 4.92 40.547 ;
     RECT  6.624 40.499 14.184 40.547 ;
     RECT  2.4 40.499 3.432 40.595 ;
     RECT  7.8 40.547 14.184 40.595 ;
     RECT  28.176 40.549 28.2 40.597 ;
     RECT  29.28 39.395 29.928 40.597 ;
     RECT  2.4 40.595 3.336 40.643 ;
     RECT  6.624 40.547 6.648 40.643 ;
     RECT  30.96 39.923 31.32 40.693 ;
     RECT  30.912 40.693 31.32 40.981 ;
     RECT  33.072 40.933 33.096 40.981 ;
     RECT  28.176 40.597 29.928 41.029 ;
     RECT  2.4 40.643 2.712 41.049 ;
     RECT  18.6 34.931 18.912 41.049 ;
     RECT  24 30.899 24.312 41.049 ;
     RECT  34.8 38.819 35.112 41.049 ;
     RECT  40.2 39.731 40.512 41.049 ;
     RECT  2.4 41.049 2.52 41.063 ;
     RECT  7.8 40.595 13.992 41.063 ;
     RECT  18.6 41.049 18.72 41.063 ;
     RECT  24 41.049 24.12 41.063 ;
     RECT  34.8 41.049 34.92 41.063 ;
     RECT  40.2 41.049 40.32 41.063 ;
     RECT  27.12 41.029 29.928 41.269 ;
     RECT  30.912 40.981 31.848 41.269 ;
     RECT  27.12 41.269 31.848 41.989 ;
     RECT  32.88 40.981 33.192 41.989 ;
     RECT  7.92 41.063 13.992 43.152 ;
     RECT  27.12 41.989 33.192 43.152 ;
  END
END ot_qwen_tp8_pv_wide_ctl
END LIBRARY
